VERSION 5.7 ;
  NOWIREEXTENSIONATPIN ON ;
  DIVIDERCHAR "/" ;
  BUSBITCHARS "[]" ;
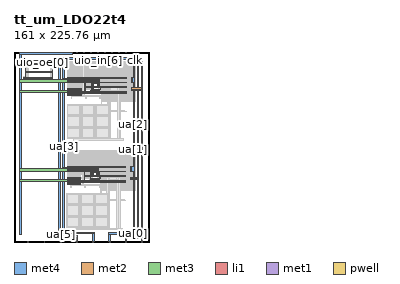
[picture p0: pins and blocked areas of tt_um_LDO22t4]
MACRO tt_um_LDO22t4
  CLASS BLOCK ;
  FOREIGN tt_um_LDO22t4 ;
  ORIGIN 0.000 0.000 ;
  SIZE 161.000 BY 225.760 ;
  PIN clk
    PORT
      LAYER met4 ;
        RECT 143.830 224.760 144.130 225.760 ;
    END
  END clk
  PIN ena
    PORT
      LAYER met4 ;
        RECT 146.590 224.760 146.890 225.760 ;
    END
  END ena
  PIN rst_n
    PORT
      LAYER met4 ;
        RECT 141.070 224.760 141.370 225.760 ;
    END
  END rst_n
  PIN ua[0]
    PORT
      LAYER met2 ;
        RECT 139.680 181.740 153.265 183.020 ;
        RECT 139.700 179.535 153.265 181.740 ;
      LAYER met3 ;
        RECT 151.310 181.805 153.190 182.970 ;
      LAYER met4 ;
        RECT 151.265 0.995 153.265 214.950 ;
        RECT 151.810 0.000 152.710 0.995 ;
    END
  END ua[0]
  PIN ua[1]
    PORT
      LAYER met2 ;
        RECT 138.825 75.945 148.495 77.225 ;
        RECT 138.860 73.740 148.495 75.945 ;
      LAYER met3 ;
        RECT 146.595 76.025 148.470 77.170 ;
      LAYER met4 ;
        RECT 146.495 5.725 148.495 214.950 ;
        RECT 132.110 3.725 148.495 5.725 ;
        RECT 132.110 2.850 134.110 3.725 ;
        RECT 132.110 1.000 134.105 2.850 ;
        RECT 132.490 0.000 133.390 1.000 ;
    END
  END ua[1]
  PIN ua[2]
    PORT
      LAYER li1 ;
        RECT 42.845 213.690 45.005 214.040 ;
      LAYER met1 ;
        RECT 42.870 213.380 44.975 214.340 ;
      LAYER met2 ;
        RECT 44.655 213.380 50.280 214.340 ;
      LAYER met3 ;
        RECT 48.260 213.380 50.280 219.085 ;
        RECT 139.090 189.435 140.555 195.880 ;
        RECT 138.345 83.450 139.665 89.480 ;
      LAYER met4 ;
        RECT 48.260 217.160 143.725 219.085 ;
        RECT 141.725 194.975 143.725 217.160 ;
        RECT 139.245 189.520 143.725 194.975 ;
        RECT 141.725 89.175 143.725 189.520 ;
        RECT 138.410 83.720 143.725 89.175 ;
        RECT 141.725 10.910 143.725 83.720 ;
        RECT 112.690 8.910 143.725 10.910 ;
        RECT 112.690 1.000 114.690 8.910 ;
        RECT 113.170 0.000 114.070 1.000 ;
    END
  END ua[2]
  PIN ua[3]
    ANTENNAGATEAREA 2.000000 ;
    PORT
      LAYER li1 ;
        RECT 67.580 192.650 68.370 192.820 ;
        RECT 68.870 192.650 69.660 192.820 ;
        RECT 67.580 191.600 68.370 191.770 ;
        RECT 68.870 191.600 69.660 191.770 ;
        RECT 66.740 86.855 67.530 87.025 ;
        RECT 68.030 86.855 68.820 87.025 ;
        RECT 66.740 85.805 67.530 85.975 ;
        RECT 68.030 85.805 68.820 85.975 ;
      LAYER met1 ;
        RECT 67.655 192.850 68.295 192.940 ;
        RECT 68.945 192.850 69.585 192.940 ;
        RECT 67.600 192.620 68.350 192.850 ;
        RECT 68.890 192.620 69.640 192.850 ;
        RECT 67.600 191.570 68.350 191.800 ;
        RECT 68.890 191.570 69.640 191.800 ;
        RECT 67.655 191.480 68.295 191.570 ;
        RECT 68.945 191.480 69.585 191.570 ;
        RECT 66.815 87.055 67.455 87.145 ;
        RECT 68.105 87.055 68.745 87.145 ;
        RECT 66.760 86.825 67.510 87.055 ;
        RECT 68.050 86.825 68.800 87.055 ;
        RECT 66.760 85.775 67.510 86.005 ;
        RECT 68.050 85.775 68.800 86.005 ;
        RECT 66.815 85.685 67.455 85.775 ;
        RECT 68.105 85.685 68.745 85.775 ;
      LAYER met2 ;
        RECT 57.830 193.080 68.780 194.150 ;
        RECT 57.830 193.075 64.395 193.080 ;
        RECT 68.460 192.940 68.780 193.080 ;
        RECT 67.655 192.620 69.585 192.940 ;
        RECT 68.415 191.800 68.715 192.620 ;
        RECT 67.655 191.480 69.585 191.800 ;
        RECT 57.830 87.285 67.940 88.355 ;
        RECT 57.830 87.280 64.390 87.285 ;
        RECT 57.830 87.255 63.160 87.280 ;
        RECT 67.620 87.145 67.940 87.285 ;
        RECT 66.815 86.825 68.745 87.145 ;
        RECT 67.575 86.005 67.875 86.825 ;
        RECT 66.815 85.685 68.745 86.005 ;
      LAYER met3 ;
        RECT 57.835 193.100 59.830 193.715 ;
        RECT 57.820 87.280 59.835 87.920 ;
      LAYER met4 ;
        RECT 57.830 12.630 59.830 214.950 ;
        RECT 57.830 11.815 59.835 12.630 ;
        RECT 57.830 9.815 95.175 11.815 ;
        RECT 93.180 0.995 95.175 9.815 ;
        RECT 93.850 0.000 94.750 0.995 ;
    END
  END ua[3]
  PIN ua[4]
    PORT
      LAYER li1 ;
        RECT 42.845 212.860 45.005 213.210 ;
        RECT 42.845 209.000 45.005 209.350 ;
      LAYER met1 ;
        RECT 44.960 213.160 46.310 213.165 ;
        RECT 42.870 212.475 46.310 213.160 ;
        RECT 45.410 209.740 46.310 212.475 ;
        RECT 42.870 209.050 46.310 209.740 ;
        RECT 44.835 209.045 46.310 209.050 ;
      LAYER met2 ;
        RECT 45.460 212.560 45.735 212.570 ;
        RECT 45.425 209.605 55.060 212.560 ;
        RECT 45.460 209.565 45.735 209.605 ;
      LAYER met3 ;
        RECT 53.105 210.420 55.015 212.490 ;
      LAYER met4 ;
        RECT 53.050 7.790 55.060 214.950 ;
        RECT 73.975 7.795 75.980 7.800 ;
        RECT 56.660 7.790 75.980 7.795 ;
        RECT 53.050 5.790 75.980 7.790 ;
        RECT 73.975 1.000 75.980 5.790 ;
        RECT 74.530 0.000 75.430 1.000 ;
    END
  END ua[4]
  PIN ua[5]
    PORT
      LAYER met4 ;
        RECT 55.210 0.000 56.110 0.990 ;
    END
  END ua[5]
  PIN ua[6]
    PORT
      LAYER met4 ;
        RECT 35.890 0.000 36.790 1.000 ;
    END
  END ua[6]
  PIN ua[7]
    PORT
      LAYER met4 ;
        RECT 16.570 0.000 17.470 1.000 ;
    END
  END ua[7]
  PIN ui_in[0]
    PORT
      LAYER met4 ;
        RECT 138.310 224.760 138.610 225.760 ;
    END
  END ui_in[0]
  PIN ui_in[1]
    PORT
      LAYER met4 ;
        RECT 135.550 224.760 135.850 225.760 ;
    END
  END ui_in[1]
  PIN ui_in[2]
    PORT
      LAYER met4 ;
        RECT 132.790 224.760 133.090 225.760 ;
    END
  END ui_in[2]
  PIN ui_in[3]
    PORT
      LAYER met4 ;
        RECT 130.030 224.760 130.330 225.760 ;
    END
  END ui_in[3]
  PIN ui_in[4]
    PORT
      LAYER met4 ;
        RECT 127.270 224.760 127.570 225.760 ;
    END
  END ui_in[4]
  PIN ui_in[5]
    PORT
      LAYER met4 ;
        RECT 124.510 224.760 124.810 225.760 ;
    END
  END ui_in[5]
  PIN ui_in[6]
    PORT
      LAYER met4 ;
        RECT 121.750 224.760 122.050 225.760 ;
    END
  END ui_in[6]
  PIN ui_in[7]
    PORT
      LAYER met4 ;
        RECT 118.990 224.760 119.290 225.760 ;
    END
  END ui_in[7]
  PIN uio_in[0]
    PORT
      LAYER met4 ;
        RECT 116.230 224.760 116.530 225.760 ;
    END
  END uio_in[0]
  PIN uio_in[1]
    PORT
      LAYER met4 ;
        RECT 113.470 224.760 113.770 225.760 ;
    END
  END uio_in[1]
  PIN uio_in[2]
    PORT
      LAYER met4 ;
        RECT 110.710 224.760 111.010 225.760 ;
    END
  END uio_in[2]
  PIN uio_in[3]
    PORT
      LAYER met4 ;
        RECT 107.950 224.760 108.250 225.760 ;
    END
  END uio_in[3]
  PIN uio_in[4]
    PORT
      LAYER met4 ;
        RECT 105.190 224.760 105.490 225.760 ;
    END
  END uio_in[4]
  PIN uio_in[5]
    PORT
      LAYER met4 ;
        RECT 102.430 224.760 102.730 225.760 ;
    END
  END uio_in[5]
  PIN uio_in[6]
    PORT
      LAYER met4 ;
        RECT 99.670 224.760 99.970 225.760 ;
    END
  END uio_in[6]
  PIN uio_in[7]
    PORT
      LAYER met4 ;
        RECT 96.910 224.760 97.210 225.760 ;
    END
  END uio_in[7]
  PIN uio_oe[0]
    ANTENNAGATEAREA 80.379997 ;
    ANTENNADIFFAREA 155.779800 ;
    PORT
      LAYER pwell ;
        RECT 13.815 215.220 45.785 215.650 ;
        RECT 13.815 211.680 14.245 215.220 ;
        RECT 45.355 211.680 45.785 215.220 ;
        RECT 13.815 211.250 45.785 211.680 ;
        RECT 13.815 210.530 45.785 210.960 ;
        RECT 13.815 202.840 14.245 210.530 ;
        RECT 45.355 202.840 45.785 210.530 ;
        RECT 13.815 202.410 45.785 202.840 ;
        RECT 13.815 201.690 45.785 202.120 ;
        RECT 13.815 194.830 14.245 201.690 ;
        RECT 45.355 194.830 45.785 201.690 ;
        RECT 13.815 194.400 45.785 194.830 ;
        RECT 63.975 194.620 101.335 195.050 ;
        RECT 63.975 189.800 64.405 194.620 ;
        RECT 72.855 189.800 73.285 194.620 ;
        RECT 89.465 189.800 89.895 194.620 ;
        RECT 100.905 189.800 101.335 194.620 ;
        RECT 63.975 189.370 101.335 189.800 ;
        RECT 64.135 176.320 79.615 182.415 ;
        RECT 64.135 176.230 65.275 176.320 ;
        RECT 76.825 176.230 79.615 176.320 ;
        RECT 64.095 174.220 71.665 176.230 ;
        RECT 72.220 174.220 79.790 176.230 ;
        RECT 63.135 88.825 100.495 89.255 ;
        RECT 63.135 84.005 63.565 88.825 ;
        RECT 72.015 84.005 72.445 88.825 ;
        RECT 88.625 84.005 89.055 88.825 ;
        RECT 100.065 84.005 100.495 88.825 ;
        RECT 63.135 83.575 100.495 84.005 ;
        RECT 63.295 70.525 78.775 76.620 ;
        RECT 63.295 70.435 64.435 70.525 ;
        RECT 75.985 70.435 78.775 70.525 ;
        RECT 63.255 68.425 70.825 70.435 ;
        RECT 71.380 68.425 78.950 70.435 ;
      LAYER li1 ;
        RECT 14.585 215.520 45.020 215.525 ;
        RECT 13.945 215.350 45.655 215.520 ;
        RECT 13.945 211.550 14.115 215.350 ;
        RECT 45.485 211.550 45.655 215.350 ;
        RECT 13.945 210.660 45.655 211.550 ;
        RECT 13.945 202.710 14.115 210.660 ;
        RECT 45.485 202.710 45.655 210.660 ;
        RECT 13.945 201.820 45.655 202.710 ;
        RECT 13.945 194.700 14.115 201.820 ;
        RECT 45.485 194.700 45.655 201.820 ;
        RECT 13.945 194.530 45.655 194.700 ;
        RECT 64.105 194.750 101.205 194.920 ;
        RECT 64.105 189.670 64.275 194.750 ;
        RECT 64.665 194.410 64.835 194.750 ;
        RECT 65.955 194.410 66.125 194.750 ;
        RECT 67.245 194.410 67.415 194.750 ;
        RECT 68.535 194.410 68.705 194.750 ;
        RECT 69.825 194.410 69.995 194.750 ;
        RECT 71.115 194.410 71.285 194.750 ;
        RECT 72.405 194.410 72.575 194.750 ;
        RECT 64.665 194.240 72.575 194.410 ;
        RECT 64.665 193.360 64.835 194.240 ;
        RECT 65.955 193.360 66.125 194.240 ;
        RECT 67.245 193.360 67.415 194.240 ;
        RECT 68.535 193.360 68.705 194.240 ;
        RECT 69.825 193.360 69.995 194.240 ;
        RECT 71.115 193.360 71.285 194.240 ;
        RECT 72.405 193.360 72.575 194.240 ;
        RECT 64.665 193.190 72.575 193.360 ;
        RECT 64.665 191.060 72.575 191.230 ;
        RECT 64.665 190.180 64.835 191.060 ;
        RECT 65.955 190.180 66.125 191.060 ;
        RECT 67.245 190.180 67.415 191.060 ;
        RECT 68.535 190.180 68.705 191.060 ;
        RECT 69.825 190.180 69.995 191.060 ;
        RECT 71.115 190.180 71.285 191.060 ;
        RECT 72.405 190.180 72.575 191.060 ;
        RECT 64.665 190.010 72.575 190.180 ;
        RECT 64.665 189.670 64.835 190.010 ;
        RECT 65.955 189.670 66.125 190.010 ;
        RECT 67.245 189.670 67.415 190.010 ;
        RECT 68.535 189.670 68.705 190.010 ;
        RECT 69.825 189.670 69.995 190.010 ;
        RECT 71.115 189.670 71.285 190.010 ;
        RECT 72.985 189.670 73.155 194.750 ;
        RECT 73.535 194.410 73.705 194.750 ;
        RECT 74.825 194.410 74.995 194.750 ;
        RECT 76.115 194.410 76.285 194.750 ;
        RECT 77.405 194.410 77.575 194.750 ;
        RECT 78.695 194.410 78.865 194.750 ;
        RECT 79.985 194.410 80.155 194.750 ;
        RECT 82.565 194.410 82.735 194.750 ;
        RECT 83.855 194.410 84.025 194.750 ;
        RECT 85.145 194.410 85.315 194.750 ;
        RECT 86.435 194.410 86.605 194.750 ;
        RECT 87.725 194.410 87.895 194.750 ;
        RECT 89.015 194.410 89.185 194.750 ;
        RECT 73.535 194.240 89.185 194.410 ;
        RECT 73.535 193.360 73.705 194.240 ;
        RECT 74.825 193.360 74.995 194.240 ;
        RECT 76.115 193.360 76.285 194.240 ;
        RECT 77.405 193.360 77.575 194.240 ;
        RECT 78.695 193.360 78.865 194.240 ;
        RECT 79.985 193.360 80.155 194.240 ;
        RECT 81.275 193.360 81.445 194.240 ;
        RECT 82.565 193.360 82.735 194.240 ;
        RECT 83.855 193.360 84.025 194.240 ;
        RECT 85.145 193.360 85.315 194.240 ;
        RECT 86.435 193.360 86.605 194.240 ;
        RECT 87.725 193.360 87.895 194.240 ;
        RECT 89.015 193.360 89.185 194.240 ;
        RECT 73.535 193.190 89.185 193.360 ;
        RECT 73.870 192.650 74.660 192.820 ;
        RECT 88.060 192.650 88.850 192.820 ;
        RECT 73.535 191.940 73.705 192.480 ;
        RECT 74.825 191.940 74.995 192.480 ;
        RECT 77.405 191.940 77.575 192.480 ;
        RECT 79.985 191.940 80.155 192.480 ;
        RECT 82.565 191.940 82.735 192.480 ;
        RECT 85.145 191.940 85.315 192.480 ;
        RECT 87.725 191.940 87.895 192.480 ;
        RECT 89.015 191.940 89.185 192.480 ;
        RECT 73.870 191.600 74.660 191.770 ;
        RECT 88.060 191.600 88.850 191.770 ;
        RECT 73.535 191.060 89.185 191.230 ;
        RECT 73.535 190.180 73.705 191.060 ;
        RECT 74.825 190.180 74.995 191.060 ;
        RECT 76.115 190.180 76.285 191.060 ;
        RECT 77.405 190.180 77.575 191.060 ;
        RECT 78.695 190.180 78.865 191.060 ;
        RECT 79.985 190.180 80.155 191.060 ;
        RECT 81.275 190.180 81.445 191.060 ;
        RECT 82.565 190.180 82.735 191.060 ;
        RECT 83.855 190.180 84.025 191.060 ;
        RECT 85.145 190.180 85.315 191.060 ;
        RECT 86.435 190.180 86.605 191.060 ;
        RECT 87.725 190.180 87.895 191.060 ;
        RECT 89.015 190.180 89.185 191.060 ;
        RECT 73.535 190.010 89.185 190.180 ;
        RECT 73.535 189.670 73.705 190.010 ;
        RECT 74.825 189.670 74.995 190.010 ;
        RECT 76.115 189.670 76.285 190.010 ;
        RECT 77.405 189.670 77.575 190.010 ;
        RECT 78.695 189.670 78.865 190.010 ;
        RECT 79.985 189.670 80.155 190.010 ;
        RECT 81.275 189.670 81.445 190.010 ;
        RECT 82.565 189.670 82.735 190.010 ;
        RECT 83.855 189.670 84.025 190.010 ;
        RECT 85.145 189.670 85.315 190.010 ;
        RECT 86.435 189.670 86.605 190.010 ;
        RECT 87.725 189.670 87.895 190.010 ;
        RECT 89.015 189.670 89.185 190.010 ;
        RECT 89.595 189.670 89.765 194.750 ;
        RECT 90.135 194.410 90.305 194.750 ;
        RECT 91.425 194.410 91.595 194.750 ;
        RECT 92.715 194.410 92.885 194.750 ;
        RECT 94.005 194.410 94.175 194.750 ;
        RECT 95.295 194.410 95.465 194.750 ;
        RECT 96.585 194.410 96.755 194.750 ;
        RECT 97.875 194.410 98.045 194.750 ;
        RECT 99.165 194.410 99.335 194.750 ;
        RECT 100.455 194.410 100.625 194.750 ;
        RECT 90.135 194.240 100.625 194.410 ;
        RECT 90.135 193.360 90.305 194.240 ;
        RECT 91.425 193.360 91.595 194.240 ;
        RECT 92.715 193.360 92.885 194.240 ;
        RECT 94.005 193.360 94.175 194.240 ;
        RECT 95.295 193.360 95.465 194.240 ;
        RECT 96.585 193.360 96.755 194.240 ;
        RECT 97.875 193.360 98.045 194.240 ;
        RECT 99.165 193.360 99.335 194.240 ;
        RECT 100.455 193.360 100.625 194.240 ;
        RECT 90.135 193.190 100.625 193.360 ;
        RECT 90.470 192.650 91.260 192.820 ;
        RECT 99.500 192.650 100.290 192.820 ;
        RECT 90.135 191.940 90.305 192.480 ;
        RECT 91.425 191.940 91.595 192.480 ;
        RECT 94.005 191.940 94.175 192.480 ;
        RECT 96.585 191.940 96.755 192.480 ;
        RECT 99.165 191.940 99.335 192.480 ;
        RECT 100.455 191.940 100.625 192.480 ;
        RECT 90.470 191.600 91.260 191.770 ;
        RECT 99.500 191.600 100.290 191.770 ;
        RECT 90.135 191.060 100.625 191.230 ;
        RECT 90.135 190.180 90.305 191.060 ;
        RECT 91.425 190.180 91.595 191.060 ;
        RECT 92.715 190.180 92.885 191.060 ;
        RECT 94.005 190.180 94.175 191.060 ;
        RECT 95.295 190.180 95.465 191.060 ;
        RECT 96.585 190.180 96.755 191.060 ;
        RECT 97.875 190.180 98.045 191.060 ;
        RECT 99.165 190.180 99.335 191.060 ;
        RECT 100.455 190.180 100.625 191.060 ;
        RECT 90.135 190.010 100.625 190.180 ;
        RECT 90.135 189.670 90.305 190.010 ;
        RECT 91.425 189.670 91.595 190.010 ;
        RECT 92.715 189.670 92.885 190.010 ;
        RECT 94.005 189.670 94.175 190.010 ;
        RECT 95.295 189.670 95.465 190.010 ;
        RECT 96.585 189.670 96.755 190.010 ;
        RECT 97.875 189.670 98.045 190.010 ;
        RECT 99.165 189.670 99.335 190.010 ;
        RECT 100.455 189.670 100.625 190.010 ;
        RECT 101.035 189.670 101.205 194.750 ;
        RECT 64.105 189.500 101.205 189.670 ;
        RECT 92.085 187.840 101.925 188.010 ;
        RECT 92.085 187.360 92.255 187.840 ;
        RECT 101.755 187.360 101.925 187.840 ;
        RECT 92.085 187.010 94.895 187.360 ;
        RECT 99.115 187.010 101.925 187.360 ;
        RECT 92.085 185.700 92.255 187.010 ;
        RECT 101.755 185.700 101.925 187.010 ;
        RECT 92.085 185.350 94.895 185.700 ;
        RECT 99.115 185.350 101.925 185.700 ;
        RECT 92.085 184.870 92.255 185.350 ;
        RECT 101.755 184.870 101.925 185.350 ;
        RECT 92.085 184.150 101.925 184.870 ;
        RECT 91.555 183.980 103.145 184.150 ;
        RECT 91.555 183.500 91.725 183.980 ;
        RECT 91.555 183.150 94.365 183.500 ;
        RECT 64.275 182.115 79.610 182.285 ;
        RECT 64.275 176.515 64.445 182.115 ;
        RECT 65.190 181.600 68.890 181.770 ;
        RECT 64.850 180.720 65.020 181.430 ;
        RECT 66.140 180.720 66.310 181.430 ;
        RECT 67.430 180.550 67.600 181.600 ;
        RECT 68.720 180.550 68.890 181.600 ;
        RECT 65.190 180.380 68.890 180.550 ;
        RECT 69.280 181.520 77.410 181.690 ;
        RECT 77.920 181.520 78.700 181.690 ;
        RECT 69.280 180.640 69.450 181.520 ;
        RECT 70.570 180.640 70.740 181.520 ;
        RECT 71.860 180.640 72.030 181.520 ;
        RECT 73.150 180.640 73.320 181.520 ;
        RECT 74.440 180.640 74.610 181.520 ;
        RECT 75.000 180.640 75.170 181.520 ;
        RECT 76.290 180.640 76.460 181.520 ;
        RECT 77.580 180.810 77.750 181.350 ;
        RECT 78.870 180.810 79.040 181.350 ;
        RECT 69.280 180.470 77.410 180.640 ;
        RECT 77.920 180.470 78.700 180.640 ;
        RECT 65.190 179.840 65.970 180.010 ;
        RECT 77.920 179.760 78.700 179.930 ;
        RECT 64.850 178.960 65.020 179.670 ;
        RECT 66.140 178.960 66.310 179.670 ;
        RECT 70.570 179.050 70.740 179.590 ;
        RECT 73.150 179.050 73.320 179.590 ;
        RECT 77.580 179.050 77.750 179.590 ;
        RECT 78.870 179.050 79.040 179.590 ;
        RECT 65.190 178.620 65.970 178.790 ;
        RECT 77.920 178.710 78.700 178.880 ;
        RECT 65.190 178.080 68.890 178.250 ;
        RECT 64.850 177.200 65.020 177.910 ;
        RECT 66.140 177.200 66.310 177.910 ;
        RECT 67.430 177.030 67.600 178.080 ;
        RECT 68.720 177.030 68.890 178.080 ;
        RECT 65.190 176.860 68.890 177.030 ;
        RECT 69.280 178.000 77.410 178.170 ;
        RECT 77.890 178.000 78.730 178.170 ;
        RECT 69.280 177.120 69.450 178.000 ;
        RECT 70.570 177.120 70.740 178.000 ;
        RECT 71.860 177.120 72.030 178.000 ;
        RECT 73.150 177.120 73.320 178.000 ;
        RECT 74.440 177.120 74.610 178.000 ;
        RECT 75.000 177.120 75.170 178.000 ;
        RECT 76.290 177.120 76.460 178.000 ;
        RECT 77.580 177.290 77.750 177.830 ;
        RECT 78.870 177.290 79.040 177.830 ;
        RECT 69.280 176.950 77.410 177.120 ;
        RECT 77.890 176.950 78.730 177.120 ;
        RECT 79.440 176.515 79.610 182.115 ;
        RECT 91.555 181.840 91.725 183.150 ;
        RECT 91.555 181.490 94.365 181.840 ;
        RECT 91.555 181.010 91.725 181.490 ;
        RECT 102.975 181.010 103.145 183.980 ;
        RECT 91.555 180.840 103.145 181.010 ;
        RECT 91.555 180.290 101.995 180.840 ;
        RECT 91.285 180.120 101.995 180.290 ;
        RECT 91.285 179.640 91.455 180.120 ;
        RECT 101.825 179.640 101.995 180.120 ;
        RECT 91.285 179.290 94.095 179.640 ;
        RECT 99.185 179.290 101.995 179.640 ;
        RECT 91.285 177.980 91.455 179.290 ;
        RECT 101.825 178.810 101.995 179.290 ;
        RECT 99.185 178.460 101.995 178.810 ;
        RECT 101.825 177.980 101.995 178.460 ;
        RECT 91.285 177.630 94.095 177.980 ;
        RECT 99.185 177.630 101.995 177.980 ;
        RECT 91.285 177.150 91.455 177.630 ;
        RECT 101.825 177.150 101.995 177.630 ;
        RECT 91.285 176.980 101.995 177.150 ;
        RECT 64.275 176.045 79.610 176.515 ;
        RECT 64.275 175.880 71.485 176.045 ;
        RECT 64.275 174.570 64.445 175.880 ;
        RECT 71.315 174.570 71.485 175.880 ;
        RECT 64.275 174.400 71.485 174.570 ;
        RECT 72.400 175.880 79.610 176.045 ;
        RECT 72.400 174.570 72.570 175.880 ;
        RECT 79.440 174.570 79.610 175.880 ;
        RECT 72.400 174.400 79.610 174.570 ;
        RECT 63.265 88.955 100.365 89.125 ;
        RECT 63.265 83.875 63.435 88.955 ;
        RECT 63.825 88.615 63.995 88.955 ;
        RECT 65.115 88.615 65.285 88.955 ;
        RECT 66.405 88.615 66.575 88.955 ;
        RECT 67.695 88.615 67.865 88.955 ;
        RECT 68.985 88.615 69.155 88.955 ;
        RECT 70.275 88.615 70.445 88.955 ;
        RECT 71.565 88.615 71.735 88.955 ;
        RECT 63.825 88.445 71.735 88.615 ;
        RECT 63.825 87.565 63.995 88.445 ;
        RECT 65.115 87.565 65.285 88.445 ;
        RECT 66.405 87.565 66.575 88.445 ;
        RECT 67.695 87.565 67.865 88.445 ;
        RECT 68.985 87.565 69.155 88.445 ;
        RECT 70.275 87.565 70.445 88.445 ;
        RECT 71.565 87.565 71.735 88.445 ;
        RECT 63.825 87.395 71.735 87.565 ;
        RECT 63.825 85.265 71.735 85.435 ;
        RECT 63.825 84.385 63.995 85.265 ;
        RECT 65.115 84.385 65.285 85.265 ;
        RECT 66.405 84.385 66.575 85.265 ;
        RECT 67.695 84.385 67.865 85.265 ;
        RECT 68.985 84.385 69.155 85.265 ;
        RECT 70.275 84.385 70.445 85.265 ;
        RECT 71.565 84.385 71.735 85.265 ;
        RECT 63.825 84.215 71.735 84.385 ;
        RECT 63.825 83.875 63.995 84.215 ;
        RECT 65.115 83.875 65.285 84.215 ;
        RECT 66.405 83.875 66.575 84.215 ;
        RECT 67.695 83.875 67.865 84.215 ;
        RECT 68.985 83.875 69.155 84.215 ;
        RECT 70.275 83.875 70.445 84.215 ;
        RECT 72.145 83.875 72.315 88.955 ;
        RECT 72.695 88.615 72.865 88.955 ;
        RECT 73.985 88.615 74.155 88.955 ;
        RECT 75.275 88.615 75.445 88.955 ;
        RECT 76.565 88.615 76.735 88.955 ;
        RECT 77.855 88.615 78.025 88.955 ;
        RECT 79.145 88.615 79.315 88.955 ;
        RECT 81.725 88.615 81.895 88.955 ;
        RECT 83.015 88.615 83.185 88.955 ;
        RECT 84.305 88.615 84.475 88.955 ;
        RECT 85.595 88.615 85.765 88.955 ;
        RECT 86.885 88.615 87.055 88.955 ;
        RECT 88.175 88.615 88.345 88.955 ;
        RECT 72.695 88.445 88.345 88.615 ;
        RECT 72.695 87.565 72.865 88.445 ;
        RECT 73.985 87.565 74.155 88.445 ;
        RECT 75.275 87.565 75.445 88.445 ;
        RECT 76.565 87.565 76.735 88.445 ;
        RECT 77.855 87.565 78.025 88.445 ;
        RECT 79.145 87.565 79.315 88.445 ;
        RECT 80.435 87.565 80.605 88.445 ;
        RECT 81.725 87.565 81.895 88.445 ;
        RECT 83.015 87.565 83.185 88.445 ;
        RECT 84.305 87.565 84.475 88.445 ;
        RECT 85.595 87.565 85.765 88.445 ;
        RECT 86.885 87.565 87.055 88.445 ;
        RECT 88.175 87.565 88.345 88.445 ;
        RECT 72.695 87.395 88.345 87.565 ;
        RECT 73.030 86.855 73.820 87.025 ;
        RECT 87.220 86.855 88.010 87.025 ;
        RECT 72.695 86.145 72.865 86.685 ;
        RECT 73.985 86.145 74.155 86.685 ;
        RECT 76.565 86.145 76.735 86.685 ;
        RECT 79.145 86.145 79.315 86.685 ;
        RECT 81.725 86.145 81.895 86.685 ;
        RECT 84.305 86.145 84.475 86.685 ;
        RECT 86.885 86.145 87.055 86.685 ;
        RECT 88.175 86.145 88.345 86.685 ;
        RECT 73.030 85.805 73.820 85.975 ;
        RECT 87.220 85.805 88.010 85.975 ;
        RECT 72.695 85.265 88.345 85.435 ;
        RECT 72.695 84.385 72.865 85.265 ;
        RECT 73.985 84.385 74.155 85.265 ;
        RECT 75.275 84.385 75.445 85.265 ;
        RECT 76.565 84.385 76.735 85.265 ;
        RECT 77.855 84.385 78.025 85.265 ;
        RECT 79.145 84.385 79.315 85.265 ;
        RECT 80.435 84.385 80.605 85.265 ;
        RECT 81.725 84.385 81.895 85.265 ;
        RECT 83.015 84.385 83.185 85.265 ;
        RECT 84.305 84.385 84.475 85.265 ;
        RECT 85.595 84.385 85.765 85.265 ;
        RECT 86.885 84.385 87.055 85.265 ;
        RECT 88.175 84.385 88.345 85.265 ;
        RECT 72.695 84.215 88.345 84.385 ;
        RECT 72.695 83.875 72.865 84.215 ;
        RECT 73.985 83.875 74.155 84.215 ;
        RECT 75.275 83.875 75.445 84.215 ;
        RECT 76.565 83.875 76.735 84.215 ;
        RECT 77.855 83.875 78.025 84.215 ;
        RECT 79.145 83.875 79.315 84.215 ;
        RECT 80.435 83.875 80.605 84.215 ;
        RECT 81.725 83.875 81.895 84.215 ;
        RECT 83.015 83.875 83.185 84.215 ;
        RECT 84.305 83.875 84.475 84.215 ;
        RECT 85.595 83.875 85.765 84.215 ;
        RECT 86.885 83.875 87.055 84.215 ;
        RECT 88.175 83.875 88.345 84.215 ;
        RECT 88.755 83.875 88.925 88.955 ;
        RECT 89.295 88.615 89.465 88.955 ;
        RECT 90.585 88.615 90.755 88.955 ;
        RECT 91.875 88.615 92.045 88.955 ;
        RECT 93.165 88.615 93.335 88.955 ;
        RECT 94.455 88.615 94.625 88.955 ;
        RECT 95.745 88.615 95.915 88.955 ;
        RECT 97.035 88.615 97.205 88.955 ;
        RECT 98.325 88.615 98.495 88.955 ;
        RECT 99.615 88.615 99.785 88.955 ;
        RECT 89.295 88.445 99.785 88.615 ;
        RECT 89.295 87.565 89.465 88.445 ;
        RECT 90.585 87.565 90.755 88.445 ;
        RECT 91.875 87.565 92.045 88.445 ;
        RECT 93.165 87.565 93.335 88.445 ;
        RECT 94.455 87.565 94.625 88.445 ;
        RECT 95.745 87.565 95.915 88.445 ;
        RECT 97.035 87.565 97.205 88.445 ;
        RECT 98.325 87.565 98.495 88.445 ;
        RECT 99.615 87.565 99.785 88.445 ;
        RECT 89.295 87.395 99.785 87.565 ;
        RECT 89.630 86.855 90.420 87.025 ;
        RECT 98.660 86.855 99.450 87.025 ;
        RECT 89.295 86.145 89.465 86.685 ;
        RECT 90.585 86.145 90.755 86.685 ;
        RECT 93.165 86.145 93.335 86.685 ;
        RECT 95.745 86.145 95.915 86.685 ;
        RECT 98.325 86.145 98.495 86.685 ;
        RECT 99.615 86.145 99.785 86.685 ;
        RECT 89.630 85.805 90.420 85.975 ;
        RECT 98.660 85.805 99.450 85.975 ;
        RECT 89.295 85.265 99.785 85.435 ;
        RECT 89.295 84.385 89.465 85.265 ;
        RECT 90.585 84.385 90.755 85.265 ;
        RECT 91.875 84.385 92.045 85.265 ;
        RECT 93.165 84.385 93.335 85.265 ;
        RECT 94.455 84.385 94.625 85.265 ;
        RECT 95.745 84.385 95.915 85.265 ;
        RECT 97.035 84.385 97.205 85.265 ;
        RECT 98.325 84.385 98.495 85.265 ;
        RECT 99.615 84.385 99.785 85.265 ;
        RECT 89.295 84.215 99.785 84.385 ;
        RECT 89.295 83.875 89.465 84.215 ;
        RECT 90.585 83.875 90.755 84.215 ;
        RECT 91.875 83.875 92.045 84.215 ;
        RECT 93.165 83.875 93.335 84.215 ;
        RECT 94.455 83.875 94.625 84.215 ;
        RECT 95.745 83.875 95.915 84.215 ;
        RECT 97.035 83.875 97.205 84.215 ;
        RECT 98.325 83.875 98.495 84.215 ;
        RECT 99.615 83.875 99.785 84.215 ;
        RECT 100.195 83.875 100.365 88.955 ;
        RECT 63.265 83.705 100.365 83.875 ;
        RECT 91.245 82.045 101.085 82.215 ;
        RECT 91.245 81.565 91.415 82.045 ;
        RECT 100.915 81.565 101.085 82.045 ;
        RECT 91.245 81.215 94.055 81.565 ;
        RECT 98.275 81.215 101.085 81.565 ;
        RECT 91.245 79.905 91.415 81.215 ;
        RECT 100.915 79.905 101.085 81.215 ;
        RECT 91.245 79.555 94.055 79.905 ;
        RECT 98.275 79.555 101.085 79.905 ;
        RECT 91.245 79.075 91.415 79.555 ;
        RECT 100.915 79.075 101.085 79.555 ;
        RECT 91.245 78.355 101.085 79.075 ;
        RECT 90.715 78.185 102.305 78.355 ;
        RECT 90.715 77.705 90.885 78.185 ;
        RECT 90.715 77.355 93.525 77.705 ;
        RECT 63.435 76.320 78.770 76.490 ;
        RECT 63.435 70.720 63.605 76.320 ;
        RECT 64.350 75.805 68.050 75.975 ;
        RECT 64.010 74.925 64.180 75.635 ;
        RECT 65.300 74.925 65.470 75.635 ;
        RECT 66.590 74.755 66.760 75.805 ;
        RECT 67.880 74.755 68.050 75.805 ;
        RECT 64.350 74.585 68.050 74.755 ;
        RECT 68.440 75.725 76.570 75.895 ;
        RECT 77.080 75.725 77.860 75.895 ;
        RECT 68.440 74.845 68.610 75.725 ;
        RECT 69.730 74.845 69.900 75.725 ;
        RECT 71.020 74.845 71.190 75.725 ;
        RECT 72.310 74.845 72.480 75.725 ;
        RECT 73.600 74.845 73.770 75.725 ;
        RECT 74.160 74.845 74.330 75.725 ;
        RECT 75.450 74.845 75.620 75.725 ;
        RECT 76.740 75.015 76.910 75.555 ;
        RECT 78.030 75.015 78.200 75.555 ;
        RECT 68.440 74.675 76.570 74.845 ;
        RECT 77.080 74.675 77.860 74.845 ;
        RECT 64.350 74.045 65.130 74.215 ;
        RECT 77.080 73.965 77.860 74.135 ;
        RECT 64.010 73.165 64.180 73.875 ;
        RECT 65.300 73.165 65.470 73.875 ;
        RECT 69.730 73.255 69.900 73.795 ;
        RECT 72.310 73.255 72.480 73.795 ;
        RECT 76.740 73.255 76.910 73.795 ;
        RECT 78.030 73.255 78.200 73.795 ;
        RECT 64.350 72.825 65.130 72.995 ;
        RECT 77.080 72.915 77.860 73.085 ;
        RECT 64.350 72.285 68.050 72.455 ;
        RECT 64.010 71.405 64.180 72.115 ;
        RECT 65.300 71.405 65.470 72.115 ;
        RECT 66.590 71.235 66.760 72.285 ;
        RECT 67.880 71.235 68.050 72.285 ;
        RECT 64.350 71.065 68.050 71.235 ;
        RECT 68.440 72.205 76.570 72.375 ;
        RECT 77.050 72.205 77.890 72.375 ;
        RECT 68.440 71.325 68.610 72.205 ;
        RECT 69.730 71.325 69.900 72.205 ;
        RECT 71.020 71.325 71.190 72.205 ;
        RECT 72.310 71.325 72.480 72.205 ;
        RECT 73.600 71.325 73.770 72.205 ;
        RECT 74.160 71.325 74.330 72.205 ;
        RECT 75.450 71.325 75.620 72.205 ;
        RECT 76.740 71.495 76.910 72.035 ;
        RECT 78.030 71.495 78.200 72.035 ;
        RECT 68.440 71.155 76.570 71.325 ;
        RECT 77.050 71.155 77.890 71.325 ;
        RECT 78.600 70.720 78.770 76.320 ;
        RECT 90.715 76.045 90.885 77.355 ;
        RECT 90.715 75.695 93.525 76.045 ;
        RECT 90.715 75.215 90.885 75.695 ;
        RECT 102.135 75.215 102.305 78.185 ;
        RECT 90.715 75.045 102.305 75.215 ;
        RECT 90.715 74.495 101.155 75.045 ;
        RECT 90.445 74.325 101.155 74.495 ;
        RECT 90.445 73.845 90.615 74.325 ;
        RECT 100.985 73.845 101.155 74.325 ;
        RECT 90.445 73.495 93.255 73.845 ;
        RECT 98.345 73.495 101.155 73.845 ;
        RECT 90.445 72.185 90.615 73.495 ;
        RECT 100.985 73.015 101.155 73.495 ;
        RECT 98.345 72.665 101.155 73.015 ;
        RECT 100.985 72.185 101.155 72.665 ;
        RECT 90.445 71.835 93.255 72.185 ;
        RECT 98.345 71.835 101.155 72.185 ;
        RECT 90.445 71.355 90.615 71.835 ;
        RECT 100.985 71.355 101.155 71.835 ;
        RECT 90.445 71.185 101.155 71.355 ;
        RECT 63.435 70.250 78.770 70.720 ;
        RECT 63.435 70.085 70.645 70.250 ;
        RECT 63.435 68.775 63.605 70.085 ;
        RECT 70.475 68.775 70.645 70.085 ;
        RECT 63.435 68.605 70.645 68.775 ;
        RECT 71.560 70.085 78.770 70.250 ;
        RECT 71.560 68.775 71.730 70.085 ;
        RECT 78.600 68.775 78.770 70.085 ;
        RECT 71.560 68.605 78.770 68.775 ;
      LAYER met1 ;
        RECT 14.485 215.235 45.070 215.655 ;
        RECT 67.170 194.995 67.490 195.000 ;
        RECT 14.315 194.390 45.120 194.830 ;
        RECT 63.990 189.755 64.350 194.995 ;
        RECT 66.300 194.690 68.365 194.995 ;
        RECT 68.875 194.690 70.950 194.995 ;
        RECT 71.620 194.690 80.860 194.995 ;
        RECT 81.770 194.700 91.670 194.995 ;
        RECT 67.170 194.680 67.490 194.690 ;
        RECT 69.750 194.675 70.070 194.690 ;
        RECT 72.900 194.600 73.220 194.690 ;
        RECT 64.635 191.030 66.155 191.260 ;
        RECT 64.635 190.210 64.865 191.030 ;
        RECT 65.925 190.210 66.155 191.030 ;
        RECT 64.635 189.980 66.155 190.210 ;
        RECT 64.635 189.755 64.865 189.980 ;
        RECT 65.925 189.755 66.155 189.980 ;
        RECT 68.505 189.755 68.735 191.785 ;
        RECT 71.085 191.030 72.605 191.260 ;
        RECT 71.085 190.210 71.315 191.030 ;
        RECT 72.375 190.210 72.605 191.030 ;
        RECT 71.085 189.980 72.605 190.210 ;
        RECT 72.955 190.070 73.185 194.600 ;
        RECT 73.460 194.440 73.780 194.690 ;
        RECT 74.750 194.440 75.070 194.690 ;
        RECT 77.330 194.440 77.650 194.690 ;
        RECT 79.910 194.440 80.230 194.690 ;
        RECT 82.495 194.440 82.815 194.700 ;
        RECT 85.070 194.440 85.390 194.700 ;
        RECT 87.650 194.440 87.970 194.700 ;
        RECT 88.940 194.440 89.260 194.700 ;
        RECT 73.460 194.355 81.090 194.440 ;
        RECT 73.505 194.210 81.090 194.355 ;
        RECT 81.630 194.355 89.260 194.440 ;
        RECT 81.630 194.210 89.215 194.355 ;
        RECT 73.505 193.390 73.735 194.210 ;
        RECT 74.795 193.390 75.025 194.210 ;
        RECT 76.085 193.390 76.315 194.210 ;
        RECT 77.375 193.390 77.605 194.210 ;
        RECT 78.665 193.390 78.895 194.210 ;
        RECT 79.955 193.390 80.185 194.210 ;
        RECT 82.535 193.390 82.765 194.210 ;
        RECT 83.825 193.390 84.055 194.210 ;
        RECT 85.115 193.390 85.345 194.210 ;
        RECT 86.405 193.390 86.635 194.210 ;
        RECT 87.695 193.390 87.925 194.210 ;
        RECT 88.985 193.390 89.215 194.210 ;
        RECT 73.505 193.160 81.110 193.390 ;
        RECT 81.630 193.160 89.215 193.390 ;
        RECT 73.505 192.850 73.735 193.160 ;
        RECT 74.795 192.850 75.025 193.160 ;
        RECT 73.505 192.620 75.025 192.850 ;
        RECT 73.505 191.800 73.735 192.620 ;
        RECT 74.795 191.800 75.025 192.620 ;
        RECT 73.505 191.570 75.025 191.800 ;
        RECT 73.505 191.260 73.735 191.570 ;
        RECT 74.795 191.260 75.025 191.570 ;
        RECT 73.505 191.030 75.025 191.260 ;
        RECT 73.505 190.210 73.735 191.030 ;
        RECT 74.795 190.210 75.025 191.030 ;
        RECT 73.505 190.070 75.025 190.210 ;
        RECT 77.375 190.070 77.605 193.160 ;
        RECT 79.955 190.070 80.185 193.160 ;
        RECT 82.535 190.070 82.765 193.160 ;
        RECT 85.115 190.070 85.345 193.160 ;
        RECT 87.695 192.850 87.925 193.160 ;
        RECT 88.985 192.850 89.215 193.160 ;
        RECT 87.695 192.620 89.215 192.850 ;
        RECT 87.695 191.800 87.925 192.620 ;
        RECT 88.985 191.800 89.215 192.620 ;
        RECT 87.695 191.570 89.215 191.800 ;
        RECT 87.695 191.260 87.925 191.570 ;
        RECT 88.985 191.260 89.215 191.570 ;
        RECT 87.695 191.030 89.215 191.260 ;
        RECT 87.695 190.210 87.925 191.030 ;
        RECT 88.985 190.210 89.215 191.030 ;
        RECT 87.695 190.070 89.215 190.210 ;
        RECT 71.085 189.755 71.315 189.980 ;
        RECT 72.375 189.755 72.605 189.980 ;
        RECT 72.900 189.755 73.220 190.070 ;
        RECT 73.450 189.980 75.060 190.070 ;
        RECT 73.450 189.755 73.770 189.980 ;
        RECT 74.740 189.755 75.060 189.980 ;
        RECT 77.320 189.755 77.640 190.070 ;
        RECT 79.900 189.755 80.220 190.070 ;
        RECT 82.485 189.755 82.805 190.070 ;
        RECT 85.065 189.755 85.385 190.070 ;
        RECT 87.645 189.980 89.255 190.070 ;
        RECT 87.645 189.755 87.965 189.980 ;
        RECT 88.935 189.755 89.255 189.980 ;
        RECT 89.565 189.755 89.795 194.700 ;
        RECT 90.060 194.440 90.380 194.700 ;
        RECT 91.350 194.440 91.670 194.700 ;
        RECT 93.065 194.695 95.115 194.995 ;
        RECT 95.655 194.695 97.705 194.995 ;
        RECT 98.245 194.700 101.300 195.000 ;
        RECT 90.060 194.355 91.670 194.440 ;
        RECT 93.930 194.355 94.250 194.695 ;
        RECT 96.515 194.355 96.835 194.695 ;
        RECT 99.090 194.495 99.410 194.700 ;
        RECT 100.375 194.495 100.695 194.700 ;
        RECT 99.090 194.355 100.695 194.495 ;
        RECT 90.105 194.210 91.625 194.355 ;
        RECT 90.105 193.390 90.335 194.210 ;
        RECT 91.395 193.390 91.625 194.210 ;
        RECT 90.105 193.160 91.625 193.390 ;
        RECT 90.105 192.850 90.335 193.160 ;
        RECT 91.395 192.850 91.625 193.160 ;
        RECT 90.105 192.620 91.625 192.850 ;
        RECT 90.105 191.800 90.335 192.620 ;
        RECT 91.395 191.800 91.625 192.620 ;
        RECT 90.105 191.570 91.625 191.800 ;
        RECT 90.105 191.260 90.335 191.570 ;
        RECT 91.395 191.260 91.625 191.570 ;
        RECT 90.105 191.030 91.625 191.260 ;
        RECT 90.105 190.210 90.335 191.030 ;
        RECT 91.395 190.210 91.625 191.030 ;
        RECT 90.105 190.070 91.625 190.210 ;
        RECT 93.975 190.070 94.205 194.355 ;
        RECT 96.555 190.070 96.785 194.355 ;
        RECT 99.135 194.210 100.655 194.355 ;
        RECT 99.135 193.390 99.365 194.210 ;
        RECT 100.425 193.390 100.655 194.210 ;
        RECT 99.135 193.160 100.655 193.390 ;
        RECT 99.135 192.850 99.365 193.160 ;
        RECT 100.425 192.850 100.655 193.160 ;
        RECT 99.135 192.620 100.655 192.850 ;
        RECT 99.135 191.800 99.365 192.620 ;
        RECT 100.425 191.800 100.655 192.620 ;
        RECT 99.135 191.570 100.655 191.800 ;
        RECT 99.135 191.260 99.365 191.570 ;
        RECT 100.425 191.260 100.655 191.570 ;
        RECT 99.135 191.030 100.655 191.260 ;
        RECT 99.135 190.210 99.365 191.030 ;
        RECT 100.425 190.210 100.655 191.030 ;
        RECT 99.135 190.070 100.655 190.210 ;
        RECT 90.060 189.980 91.665 190.070 ;
        RECT 90.060 189.755 90.380 189.980 ;
        RECT 91.345 189.755 91.665 189.980 ;
        RECT 93.925 189.755 94.245 190.070 ;
        RECT 96.505 189.755 96.825 190.070 ;
        RECT 99.090 189.980 100.700 190.070 ;
        RECT 99.090 189.755 99.410 189.980 ;
        RECT 100.380 189.755 100.700 189.980 ;
        RECT 63.990 189.430 80.895 189.755 ;
        RECT 81.700 189.435 100.700 189.755 ;
        RECT 100.940 189.435 101.300 194.700 ;
        RECT 82.485 189.430 82.805 189.435 ;
        RECT 79.955 189.420 80.185 189.430 ;
        RECT 64.190 182.340 64.510 182.395 ;
        RECT 64.190 182.050 65.235 182.340 ;
        RECT 65.880 182.335 66.500 182.345 ;
        RECT 65.870 182.065 66.500 182.335 ;
        RECT 70.480 182.085 70.830 182.345 ;
        RECT 65.880 182.055 66.500 182.065 ;
        RECT 64.190 176.570 64.510 182.050 ;
        RECT 64.820 181.800 65.050 182.050 ;
        RECT 66.110 181.800 66.350 182.055 ;
        RECT 64.820 181.570 66.350 181.800 ;
        RECT 64.820 180.580 65.050 181.570 ;
        RECT 66.110 180.580 66.350 181.570 ;
        RECT 64.820 180.350 66.350 180.580 ;
        RECT 64.820 180.040 65.050 180.350 ;
        RECT 66.110 180.040 66.350 180.350 ;
        RECT 64.820 179.810 66.350 180.040 ;
        RECT 64.820 178.820 65.050 179.810 ;
        RECT 66.110 178.830 66.350 179.810 ;
        RECT 66.110 178.820 66.340 178.830 ;
        RECT 64.820 178.590 66.340 178.820 ;
        RECT 64.820 178.280 65.050 178.590 ;
        RECT 66.110 178.280 66.340 178.590 ;
        RECT 64.820 178.050 66.340 178.280 ;
        RECT 64.820 177.255 65.050 178.050 ;
        RECT 64.760 177.060 65.080 177.255 ;
        RECT 66.110 177.220 66.340 178.050 ;
        RECT 70.540 177.270 70.770 182.085 ;
        RECT 72.925 182.060 73.545 182.350 ;
        RECT 73.120 177.270 73.350 182.060 ;
        RECT 77.355 182.055 77.975 182.345 ;
        RECT 78.635 182.070 79.680 182.360 ;
        RECT 77.520 181.720 77.780 182.055 ;
        RECT 78.840 181.720 79.070 182.070 ;
        RECT 76.645 181.490 79.070 181.720 ;
        RECT 77.520 180.670 77.780 181.490 ;
        RECT 78.840 180.670 79.070 181.490 ;
        RECT 76.645 180.440 79.070 180.670 ;
        RECT 77.520 179.960 77.780 180.440 ;
        RECT 78.840 179.960 79.070 180.440 ;
        RECT 77.520 179.730 79.070 179.960 ;
        RECT 77.520 178.910 77.780 179.730 ;
        RECT 78.840 178.910 79.070 179.730 ;
        RECT 77.520 178.680 79.070 178.910 ;
        RECT 77.520 178.200 77.780 178.680 ;
        RECT 78.840 178.200 79.070 178.680 ;
        RECT 76.645 177.970 79.070 178.200 ;
        RECT 77.520 177.270 77.780 177.970 ;
        RECT 78.840 177.285 79.070 177.970 ;
        RECT 66.065 177.060 66.385 177.220 ;
        RECT 64.760 176.830 66.385 177.060 ;
        RECT 70.505 176.950 70.825 177.270 ;
        RECT 64.760 176.570 65.080 176.830 ;
        RECT 66.065 176.575 66.385 176.830 ;
        RECT 64.190 176.280 65.265 176.570 ;
        RECT 65.920 176.310 66.510 176.575 ;
        RECT 70.500 176.565 70.820 176.950 ;
        RECT 73.075 176.565 73.395 177.270 ;
        RECT 77.490 177.150 77.810 177.270 ;
        RECT 78.795 177.150 79.115 177.285 ;
        RECT 76.645 176.965 79.115 177.150 ;
        RECT 76.645 176.920 79.120 176.965 ;
        RECT 77.490 176.575 77.810 176.920 ;
        RECT 78.800 176.585 79.120 176.920 ;
        RECT 79.360 176.585 79.680 182.070 ;
        RECT 70.350 176.315 70.940 176.565 ;
        RECT 72.940 176.310 73.530 176.565 ;
        RECT 77.350 176.285 77.940 176.575 ;
        RECT 78.640 176.295 79.680 176.585 ;
        RECT 84.295 176.550 84.615 189.435 ;
        RECT 85.065 189.430 85.385 189.435 ;
        RECT 87.645 189.430 87.965 189.435 ;
        RECT 88.935 189.430 89.255 189.435 ;
        RECT 90.060 189.430 90.380 189.435 ;
        RECT 91.345 189.430 91.665 189.435 ;
        RECT 93.925 189.430 94.245 189.435 ;
        RECT 96.505 189.430 96.825 189.435 ;
        RECT 99.090 189.430 99.410 189.435 ;
        RECT 100.380 189.430 100.700 189.435 ;
        RECT 92.165 184.150 101.795 184.810 ;
        RECT 99.210 178.510 101.315 178.760 ;
        RECT 91.965 177.680 94.070 177.930 ;
        RECT 99.210 177.680 101.315 177.930 ;
        RECT 91.525 176.905 101.755 177.220 ;
        RECT 64.190 174.845 64.510 176.280 ;
        RECT 79.360 174.810 79.680 176.295 ;
        RECT 66.330 89.200 66.650 89.205 ;
        RECT 63.150 83.960 63.510 89.200 ;
        RECT 65.460 88.895 67.525 89.200 ;
        RECT 68.035 88.895 70.110 89.200 ;
        RECT 70.780 88.895 80.020 89.200 ;
        RECT 80.930 88.905 90.830 89.200 ;
        RECT 66.330 88.885 66.650 88.895 ;
        RECT 68.910 88.880 69.230 88.895 ;
        RECT 72.060 88.805 72.380 88.895 ;
        RECT 63.795 85.235 65.315 85.465 ;
        RECT 63.795 84.415 64.025 85.235 ;
        RECT 65.085 84.415 65.315 85.235 ;
        RECT 63.795 84.185 65.315 84.415 ;
        RECT 63.795 83.960 64.025 84.185 ;
        RECT 65.085 83.960 65.315 84.185 ;
        RECT 67.665 83.960 67.895 85.990 ;
        RECT 70.245 85.235 71.765 85.465 ;
        RECT 70.245 84.415 70.475 85.235 ;
        RECT 71.535 84.415 71.765 85.235 ;
        RECT 70.245 84.185 71.765 84.415 ;
        RECT 72.115 84.275 72.345 88.805 ;
        RECT 72.620 88.645 72.940 88.895 ;
        RECT 73.910 88.645 74.230 88.895 ;
        RECT 76.490 88.645 76.810 88.895 ;
        RECT 79.070 88.645 79.390 88.895 ;
        RECT 81.655 88.645 81.975 88.905 ;
        RECT 84.230 88.645 84.550 88.905 ;
        RECT 86.810 88.645 87.130 88.905 ;
        RECT 88.100 88.645 88.420 88.905 ;
        RECT 72.620 88.560 80.250 88.645 ;
        RECT 72.665 88.415 80.250 88.560 ;
        RECT 80.790 88.560 88.420 88.645 ;
        RECT 80.790 88.415 88.375 88.560 ;
        RECT 72.665 87.595 72.895 88.415 ;
        RECT 73.955 87.595 74.185 88.415 ;
        RECT 75.245 87.595 75.475 88.415 ;
        RECT 76.535 87.595 76.765 88.415 ;
        RECT 77.825 87.595 78.055 88.415 ;
        RECT 79.115 87.595 79.345 88.415 ;
        RECT 81.695 87.595 81.925 88.415 ;
        RECT 82.985 87.595 83.215 88.415 ;
        RECT 84.275 87.595 84.505 88.415 ;
        RECT 85.565 87.595 85.795 88.415 ;
        RECT 86.855 87.595 87.085 88.415 ;
        RECT 88.145 87.595 88.375 88.415 ;
        RECT 72.665 87.365 80.270 87.595 ;
        RECT 80.790 87.365 88.375 87.595 ;
        RECT 72.665 87.055 72.895 87.365 ;
        RECT 73.955 87.055 74.185 87.365 ;
        RECT 72.665 86.825 74.185 87.055 ;
        RECT 72.665 86.005 72.895 86.825 ;
        RECT 73.955 86.005 74.185 86.825 ;
        RECT 72.665 85.775 74.185 86.005 ;
        RECT 72.665 85.465 72.895 85.775 ;
        RECT 73.955 85.465 74.185 85.775 ;
        RECT 72.665 85.235 74.185 85.465 ;
        RECT 72.665 84.415 72.895 85.235 ;
        RECT 73.955 84.415 74.185 85.235 ;
        RECT 72.665 84.275 74.185 84.415 ;
        RECT 76.535 84.275 76.765 87.365 ;
        RECT 79.115 84.275 79.345 87.365 ;
        RECT 81.695 84.275 81.925 87.365 ;
        RECT 84.275 84.275 84.505 87.365 ;
        RECT 86.855 87.055 87.085 87.365 ;
        RECT 88.145 87.055 88.375 87.365 ;
        RECT 86.855 86.825 88.375 87.055 ;
        RECT 86.855 86.005 87.085 86.825 ;
        RECT 88.145 86.005 88.375 86.825 ;
        RECT 86.855 85.775 88.375 86.005 ;
        RECT 86.855 85.465 87.085 85.775 ;
        RECT 88.145 85.465 88.375 85.775 ;
        RECT 86.855 85.235 88.375 85.465 ;
        RECT 86.855 84.415 87.085 85.235 ;
        RECT 88.145 84.415 88.375 85.235 ;
        RECT 86.855 84.275 88.375 84.415 ;
        RECT 70.245 83.960 70.475 84.185 ;
        RECT 71.535 83.960 71.765 84.185 ;
        RECT 72.060 83.960 72.380 84.275 ;
        RECT 72.610 84.185 74.220 84.275 ;
        RECT 72.610 83.960 72.930 84.185 ;
        RECT 73.900 83.960 74.220 84.185 ;
        RECT 76.480 83.960 76.800 84.275 ;
        RECT 79.060 83.960 79.380 84.275 ;
        RECT 81.645 83.960 81.965 84.275 ;
        RECT 84.225 83.960 84.545 84.275 ;
        RECT 86.805 84.185 88.415 84.275 ;
        RECT 86.805 83.960 87.125 84.185 ;
        RECT 88.095 83.960 88.415 84.185 ;
        RECT 88.725 83.960 88.955 88.905 ;
        RECT 89.220 88.645 89.540 88.905 ;
        RECT 90.510 88.645 90.830 88.905 ;
        RECT 92.225 88.900 94.275 89.200 ;
        RECT 94.815 88.900 96.865 89.200 ;
        RECT 97.405 88.905 100.460 89.205 ;
        RECT 89.220 88.560 90.830 88.645 ;
        RECT 93.090 88.560 93.410 88.900 ;
        RECT 95.675 88.560 95.995 88.900 ;
        RECT 98.250 88.700 98.570 88.905 ;
        RECT 99.535 88.700 99.855 88.905 ;
        RECT 98.250 88.560 99.855 88.700 ;
        RECT 89.265 88.415 90.785 88.560 ;
        RECT 89.265 87.595 89.495 88.415 ;
        RECT 90.555 87.595 90.785 88.415 ;
        RECT 89.265 87.365 90.785 87.595 ;
        RECT 89.265 87.055 89.495 87.365 ;
        RECT 90.555 87.055 90.785 87.365 ;
        RECT 89.265 86.825 90.785 87.055 ;
        RECT 89.265 86.005 89.495 86.825 ;
        RECT 90.555 86.005 90.785 86.825 ;
        RECT 89.265 85.775 90.785 86.005 ;
        RECT 89.265 85.465 89.495 85.775 ;
        RECT 90.555 85.465 90.785 85.775 ;
        RECT 89.265 85.235 90.785 85.465 ;
        RECT 89.265 84.415 89.495 85.235 ;
        RECT 90.555 84.415 90.785 85.235 ;
        RECT 89.265 84.275 90.785 84.415 ;
        RECT 93.135 84.275 93.365 88.560 ;
        RECT 95.715 84.275 95.945 88.560 ;
        RECT 98.295 88.415 99.815 88.560 ;
        RECT 98.295 87.595 98.525 88.415 ;
        RECT 99.585 87.595 99.815 88.415 ;
        RECT 98.295 87.365 99.815 87.595 ;
        RECT 98.295 87.055 98.525 87.365 ;
        RECT 99.585 87.055 99.815 87.365 ;
        RECT 98.295 86.825 99.815 87.055 ;
        RECT 98.295 86.005 98.525 86.825 ;
        RECT 99.585 86.005 99.815 86.825 ;
        RECT 98.295 85.775 99.815 86.005 ;
        RECT 98.295 85.465 98.525 85.775 ;
        RECT 99.585 85.465 99.815 85.775 ;
        RECT 98.295 85.235 99.815 85.465 ;
        RECT 98.295 84.415 98.525 85.235 ;
        RECT 99.585 84.415 99.815 85.235 ;
        RECT 98.295 84.275 99.815 84.415 ;
        RECT 89.220 84.185 90.825 84.275 ;
        RECT 89.220 83.960 89.540 84.185 ;
        RECT 90.505 83.960 90.825 84.185 ;
        RECT 93.085 83.960 93.405 84.275 ;
        RECT 95.665 83.960 95.985 84.275 ;
        RECT 98.250 84.185 99.860 84.275 ;
        RECT 98.250 83.960 98.570 84.185 ;
        RECT 99.540 83.960 99.860 84.185 ;
        RECT 63.150 83.635 80.055 83.960 ;
        RECT 80.860 83.640 99.860 83.960 ;
        RECT 100.100 83.640 100.460 88.905 ;
        RECT 81.645 83.635 81.965 83.640 ;
        RECT 79.115 83.625 79.345 83.635 ;
        RECT 63.350 76.545 63.670 76.600 ;
        RECT 63.350 76.255 64.395 76.545 ;
        RECT 65.040 76.540 65.660 76.550 ;
        RECT 65.030 76.270 65.660 76.540 ;
        RECT 69.640 76.290 69.990 76.550 ;
        RECT 65.040 76.260 65.660 76.270 ;
        RECT 63.350 70.775 63.670 76.255 ;
        RECT 63.980 76.005 64.210 76.255 ;
        RECT 65.270 76.005 65.510 76.260 ;
        RECT 63.980 75.775 65.510 76.005 ;
        RECT 63.980 74.785 64.210 75.775 ;
        RECT 65.270 74.785 65.510 75.775 ;
        RECT 63.980 74.555 65.510 74.785 ;
        RECT 63.980 74.245 64.210 74.555 ;
        RECT 65.270 74.245 65.510 74.555 ;
        RECT 63.980 74.015 65.510 74.245 ;
        RECT 63.980 73.025 64.210 74.015 ;
        RECT 65.270 73.035 65.510 74.015 ;
        RECT 65.270 73.025 65.500 73.035 ;
        RECT 63.980 72.795 65.500 73.025 ;
        RECT 63.980 72.485 64.210 72.795 ;
        RECT 65.270 72.485 65.500 72.795 ;
        RECT 63.980 72.255 65.500 72.485 ;
        RECT 63.980 71.460 64.210 72.255 ;
        RECT 63.920 71.265 64.240 71.460 ;
        RECT 65.270 71.425 65.500 72.255 ;
        RECT 69.700 71.475 69.930 76.290 ;
        RECT 72.085 76.265 72.705 76.555 ;
        RECT 72.280 71.475 72.510 76.265 ;
        RECT 76.515 76.260 77.135 76.550 ;
        RECT 77.795 76.275 78.840 76.565 ;
        RECT 76.680 75.925 76.940 76.260 ;
        RECT 78.000 75.925 78.230 76.275 ;
        RECT 75.805 75.695 78.230 75.925 ;
        RECT 76.680 74.875 76.940 75.695 ;
        RECT 78.000 74.875 78.230 75.695 ;
        RECT 75.805 74.645 78.230 74.875 ;
        RECT 76.680 74.165 76.940 74.645 ;
        RECT 78.000 74.165 78.230 74.645 ;
        RECT 76.680 73.935 78.230 74.165 ;
        RECT 76.680 73.115 76.940 73.935 ;
        RECT 78.000 73.115 78.230 73.935 ;
        RECT 76.680 72.885 78.230 73.115 ;
        RECT 76.680 72.405 76.940 72.885 ;
        RECT 78.000 72.405 78.230 72.885 ;
        RECT 75.805 72.175 78.230 72.405 ;
        RECT 76.680 71.475 76.940 72.175 ;
        RECT 78.000 71.490 78.230 72.175 ;
        RECT 65.225 71.265 65.545 71.425 ;
        RECT 63.920 71.035 65.545 71.265 ;
        RECT 69.665 71.155 69.985 71.475 ;
        RECT 63.920 70.775 64.240 71.035 ;
        RECT 65.225 70.780 65.545 71.035 ;
        RECT 63.350 70.485 64.425 70.775 ;
        RECT 65.080 70.515 65.670 70.780 ;
        RECT 69.660 70.770 69.980 71.155 ;
        RECT 72.235 70.770 72.555 71.475 ;
        RECT 76.650 71.355 76.970 71.475 ;
        RECT 77.955 71.355 78.275 71.490 ;
        RECT 75.805 71.170 78.275 71.355 ;
        RECT 75.805 71.125 78.280 71.170 ;
        RECT 76.650 70.780 76.970 71.125 ;
        RECT 77.960 70.790 78.280 71.125 ;
        RECT 78.520 70.790 78.840 76.275 ;
        RECT 69.510 70.520 70.100 70.770 ;
        RECT 72.100 70.515 72.690 70.770 ;
        RECT 76.510 70.490 77.100 70.780 ;
        RECT 77.800 70.500 78.840 70.790 ;
        RECT 83.455 70.755 83.775 83.640 ;
        RECT 84.225 83.635 84.545 83.640 ;
        RECT 86.805 83.635 87.125 83.640 ;
        RECT 88.095 83.635 88.415 83.640 ;
        RECT 89.220 83.635 89.540 83.640 ;
        RECT 90.505 83.635 90.825 83.640 ;
        RECT 93.085 83.635 93.405 83.640 ;
        RECT 95.665 83.635 95.985 83.640 ;
        RECT 98.250 83.635 98.570 83.640 ;
        RECT 99.540 83.635 99.860 83.640 ;
        RECT 91.325 78.355 100.955 79.015 ;
        RECT 98.370 72.715 100.475 72.965 ;
        RECT 91.125 71.885 93.230 72.135 ;
        RECT 98.370 71.885 100.475 72.135 ;
        RECT 90.685 71.110 100.915 71.425 ;
        RECT 63.350 69.050 63.670 70.485 ;
        RECT 78.520 69.015 78.840 70.500 ;
      LAYER met2 ;
        RECT 6.845 215.705 8.700 215.725 ;
        RECT 6.770 215.185 45.020 215.705 ;
        RECT 6.845 215.175 8.700 215.185 ;
        RECT 67.170 194.995 67.490 195.000 ;
        RECT 10.700 194.340 45.070 194.880 ;
        RECT 63.915 194.355 133.800 194.995 ;
        RECT 63.915 189.430 133.800 190.070 ;
        RECT 84.295 183.715 133.800 185.005 ;
        RECT 77.560 178.150 133.800 178.820 ;
        RECT 63.915 176.550 133.800 177.350 ;
        RECT 66.330 89.200 66.650 89.205 ;
        RECT 63.075 88.560 132.960 89.200 ;
        RECT 63.075 83.635 132.960 84.275 ;
        RECT 83.455 77.920 132.960 79.210 ;
        RECT 76.720 72.355 132.960 73.025 ;
        RECT 63.075 70.755 132.960 71.555 ;
      LAYER met3 ;
        RECT 6.795 215.190 8.750 215.735 ;
        RECT 63.915 192.795 64.380 195.060 ;
        RECT 6.770 189.900 64.380 192.795 ;
        RECT 63.915 189.430 64.380 189.900 ;
        RECT 64.680 189.430 65.145 195.060 ;
        RECT 65.445 189.430 65.910 195.060 ;
        RECT 66.210 193.855 66.675 195.060 ;
        RECT 67.185 189.430 67.650 195.060 ;
        RECT 67.950 189.430 68.415 195.060 ;
        RECT 68.715 189.430 69.180 195.060 ;
        RECT 69.480 189.430 69.945 195.060 ;
        RECT 70.245 193.860 70.710 195.060 ;
        RECT 71.055 189.430 71.520 195.060 ;
        RECT 71.820 189.430 72.285 195.060 ;
        RECT 72.585 189.430 73.050 195.060 ;
        RECT 73.350 189.430 73.815 195.060 ;
        RECT 74.115 189.430 74.580 195.060 ;
        RECT 75.235 193.860 75.700 195.060 ;
        RECT 76.410 189.430 76.875 195.060 ;
        RECT 77.175 189.430 77.640 195.060 ;
        RECT 77.940 189.430 78.405 195.060 ;
        RECT 78.705 189.430 79.170 195.060 ;
        RECT 79.470 189.430 79.935 195.060 ;
        RECT 80.235 189.430 80.700 195.060 ;
        RECT 81.000 189.430 81.465 195.060 ;
        RECT 83.800 189.430 84.265 195.060 ;
        RECT 84.565 189.430 85.030 195.060 ;
        RECT 85.330 189.430 85.795 195.060 ;
        RECT 86.095 189.430 86.560 195.060 ;
        RECT 86.875 193.860 87.340 195.060 ;
        RECT 87.645 189.430 88.110 195.060 ;
        RECT 88.410 189.430 88.875 195.060 ;
        RECT 89.175 189.430 89.640 195.060 ;
        RECT 89.940 189.430 90.405 195.060 ;
        RECT 90.705 189.430 91.170 195.060 ;
        RECT 91.470 189.430 91.935 195.060 ;
        RECT 92.235 189.430 92.700 195.060 ;
        RECT 93.000 189.430 93.465 195.060 ;
        RECT 93.765 189.430 94.230 195.060 ;
        RECT 94.530 189.430 94.995 195.060 ;
        RECT 95.295 189.430 95.760 195.060 ;
        RECT 96.060 189.430 96.525 195.060 ;
        RECT 96.825 189.430 97.290 195.060 ;
        RECT 97.590 189.430 98.055 195.060 ;
        RECT 98.355 189.430 98.820 195.060 ;
        RECT 99.120 189.430 99.585 195.060 ;
        RECT 99.885 189.430 100.350 195.060 ;
        RECT 100.650 189.430 101.115 195.060 ;
        RECT 9.400 180.435 57.000 180.440 ;
        RECT 63.915 180.435 64.380 182.295 ;
        RECT 6.770 177.540 64.380 180.435 ;
        RECT 63.915 174.865 64.380 177.540 ;
        RECT 64.680 174.865 65.145 182.295 ;
        RECT 65.445 174.865 65.910 182.295 ;
        RECT 66.305 174.865 66.770 180.795 ;
        RECT 67.185 174.865 67.650 182.295 ;
        RECT 67.950 174.865 68.415 182.295 ;
        RECT 68.715 174.865 69.180 182.295 ;
        RECT 69.480 174.865 69.945 182.295 ;
        RECT 70.245 174.865 70.710 180.795 ;
        RECT 71.055 174.865 71.520 182.295 ;
        RECT 71.820 174.865 72.285 182.295 ;
        RECT 72.585 174.865 73.050 182.295 ;
        RECT 73.350 174.865 73.815 182.295 ;
        RECT 74.115 174.865 74.580 182.295 ;
        RECT 74.880 174.865 75.345 182.295 ;
        RECT 75.645 174.865 76.110 182.295 ;
        RECT 76.410 174.865 76.875 182.295 ;
        RECT 77.175 174.865 77.640 182.295 ;
        RECT 77.940 174.865 78.405 182.295 ;
        RECT 78.705 174.865 79.170 182.295 ;
        RECT 79.470 174.865 79.935 182.295 ;
        RECT 9.645 86.905 57.245 86.910 ;
        RECT 63.075 86.905 63.540 89.265 ;
        RECT 6.770 84.010 63.540 86.905 ;
        RECT 63.075 83.635 63.540 84.010 ;
        RECT 63.840 83.635 64.305 89.265 ;
        RECT 64.605 83.635 65.070 89.265 ;
        RECT 65.370 88.060 65.835 89.265 ;
        RECT 66.345 83.635 66.810 89.265 ;
        RECT 67.110 83.635 67.575 89.265 ;
        RECT 67.875 83.635 68.340 89.265 ;
        RECT 68.640 83.635 69.105 89.265 ;
        RECT 69.405 88.065 69.870 89.265 ;
        RECT 70.215 83.635 70.680 89.265 ;
        RECT 70.980 83.635 71.445 89.265 ;
        RECT 71.745 83.635 72.210 89.265 ;
        RECT 72.510 83.635 72.975 89.265 ;
        RECT 73.275 83.635 73.740 89.265 ;
        RECT 74.395 88.065 74.860 89.265 ;
        RECT 75.570 83.635 76.035 89.265 ;
        RECT 76.335 83.635 76.800 89.265 ;
        RECT 77.100 83.635 77.565 89.265 ;
        RECT 77.865 83.635 78.330 89.265 ;
        RECT 78.630 83.635 79.095 89.265 ;
        RECT 79.395 83.635 79.860 89.265 ;
        RECT 80.160 83.635 80.625 89.265 ;
        RECT 82.960 83.635 83.425 89.265 ;
        RECT 83.725 83.635 84.190 89.265 ;
        RECT 84.490 83.635 84.955 89.265 ;
        RECT 85.255 83.635 85.720 89.265 ;
        RECT 86.035 88.065 86.500 89.265 ;
        RECT 86.805 83.635 87.270 89.265 ;
        RECT 87.570 83.635 88.035 89.265 ;
        RECT 88.335 83.635 88.800 89.265 ;
        RECT 89.100 83.635 89.565 89.265 ;
        RECT 89.865 83.635 90.330 89.265 ;
        RECT 90.630 83.635 91.095 89.265 ;
        RECT 91.395 83.635 91.860 89.265 ;
        RECT 92.160 83.635 92.625 89.265 ;
        RECT 92.925 83.635 93.390 89.265 ;
        RECT 93.690 83.635 94.155 89.265 ;
        RECT 94.455 83.635 94.920 89.265 ;
        RECT 95.220 83.635 95.685 89.265 ;
        RECT 95.985 83.635 96.450 89.265 ;
        RECT 96.750 83.635 97.215 89.265 ;
        RECT 97.515 83.635 97.980 89.265 ;
        RECT 98.280 83.635 98.745 89.265 ;
        RECT 99.045 83.635 99.510 89.265 ;
        RECT 99.810 83.635 100.275 89.265 ;
        RECT 9.645 74.485 57.245 74.490 ;
        RECT 63.075 74.485 63.540 76.500 ;
        RECT 6.770 71.590 63.540 74.485 ;
        RECT 63.075 69.070 63.540 71.590 ;
        RECT 63.840 69.070 64.305 76.500 ;
        RECT 64.605 69.070 65.070 76.500 ;
        RECT 65.465 69.070 65.930 75.000 ;
        RECT 66.345 69.070 66.810 76.500 ;
        RECT 67.110 69.070 67.575 76.500 ;
        RECT 67.875 69.070 68.340 76.500 ;
        RECT 68.640 69.070 69.105 76.500 ;
        RECT 69.405 69.070 69.870 75.000 ;
        RECT 70.215 69.070 70.680 76.500 ;
        RECT 70.980 69.070 71.445 76.500 ;
        RECT 71.745 69.070 72.210 76.500 ;
        RECT 72.510 69.070 72.975 76.500 ;
        RECT 73.275 69.070 73.740 76.500 ;
        RECT 74.040 69.070 74.505 76.500 ;
        RECT 74.805 69.070 75.270 76.500 ;
        RECT 75.570 69.070 76.035 76.500 ;
        RECT 76.335 69.070 76.800 76.500 ;
        RECT 77.100 69.070 77.565 76.500 ;
        RECT 77.865 69.070 78.330 76.500 ;
        RECT 78.630 69.070 79.095 76.500 ;
      LAYER met4 ;
        RECT 30.670 224.760 30.970 225.760 ;
        RECT 33.430 224.760 33.730 225.760 ;
        RECT 36.190 224.760 36.490 225.760 ;
        RECT 38.950 224.760 39.250 225.760 ;
        RECT 41.710 224.760 42.010 225.760 ;
        RECT 44.470 224.760 44.770 225.760 ;
        RECT 47.230 224.760 47.530 225.760 ;
        RECT 49.990 224.760 50.290 225.760 ;
        RECT 52.750 224.760 53.050 225.760 ;
        RECT 55.510 224.760 55.810 225.760 ;
        RECT 58.270 224.760 58.570 225.760 ;
        RECT 61.030 224.760 61.330 225.760 ;
        RECT 63.790 224.760 64.090 225.760 ;
        RECT 66.550 224.760 66.850 225.760 ;
        RECT 69.310 224.760 69.610 225.760 ;
        RECT 6.770 222.835 69.610 224.760 ;
        RECT 6.770 8.490 8.770 222.835 ;
    END
  END uio_oe[0]
  PIN uio_out[0]
    PORT
      LAYER met4 ;
        RECT 72.070 224.760 72.370 225.760 ;
    END
  END uio_out[0]
  PIN uo_out[0]
    PORT
      LAYER met4 ;
        RECT 94.150 224.760 94.450 225.760 ;
    END
  END uo_out[0]
  PIN uo_out[1]
    PORT
      LAYER met4 ;
        RECT 91.390 224.760 91.690 225.760 ;
    END
  END uo_out[1]
  PIN uo_out[2]
    PORT
      LAYER met4 ;
        RECT 88.630 224.760 88.930 225.760 ;
    END
  END uo_out[2]
  PIN uo_out[3]
    PORT
      LAYER met4 ;
        RECT 85.870 224.760 86.170 225.760 ;
    END
  END uo_out[3]
  PIN uo_out[4]
    PORT
      LAYER met4 ;
        RECT 83.110 224.760 83.410 225.760 ;
    END
  END uo_out[4]
  PIN uo_out[5]
    PORT
      LAYER met4 ;
        RECT 80.350 224.760 80.650 225.760 ;
    END
  END uo_out[5]
  PIN uo_out[6]
    PORT
      LAYER met4 ;
        RECT 77.590 224.760 77.890 225.760 ;
    END
  END uo_out[6]
  PIN uo_out[7]
    PORT
      LAYER met4 ;
        RECT 74.830 224.760 75.130 225.760 ;
    END
  END uo_out[7]
  OBS
      LAYER nwell ;
        RECT 63.915 195.050 144.625 214.600 ;
      LAYER pwell ;
        RECT 64.475 193.420 72.765 194.180 ;
        RECT 73.345 193.420 89.375 194.180 ;
        RECT 89.945 193.420 100.815 194.180 ;
        RECT 64.475 191.830 72.765 192.590 ;
        RECT 73.345 191.830 89.375 192.590 ;
        RECT 89.945 191.830 100.815 192.590 ;
        RECT 64.475 190.240 72.765 191.000 ;
        RECT 73.345 190.240 89.375 191.000 ;
        RECT 89.945 190.240 100.815 191.000 ;
      LAYER nwell ;
        RECT 64.650 182.415 79.610 189.370 ;
        RECT 103.875 166.410 144.625 195.050 ;
        RECT 63.075 89.255 143.785 108.805 ;
      LAYER pwell ;
        RECT 63.635 87.625 71.925 88.385 ;
        RECT 72.505 87.625 88.535 88.385 ;
        RECT 89.105 87.625 99.975 88.385 ;
        RECT 63.635 86.035 71.925 86.795 ;
        RECT 72.505 86.035 88.535 86.795 ;
        RECT 89.105 86.035 99.975 86.795 ;
        RECT 63.635 84.445 71.925 85.205 ;
        RECT 72.505 84.445 88.535 85.205 ;
        RECT 89.105 84.445 99.975 85.205 ;
      LAYER nwell ;
        RECT 63.810 76.620 78.770 83.575 ;
        RECT 103.035 60.615 143.785 89.255 ;
      LAYER li1 ;
        RECT 14.595 214.520 16.755 214.870 ;
        RECT 42.845 214.520 45.005 214.870 ;
        RECT 64.095 214.250 103.785 214.420 ;
        RECT 14.595 213.690 16.755 214.040 ;
        RECT 14.595 212.860 16.755 213.210 ;
        RECT 14.595 212.030 16.755 212.380 ;
        RECT 42.845 212.030 45.005 212.380 ;
        RECT 14.595 209.830 16.755 210.180 ;
        RECT 42.845 209.830 45.005 210.180 ;
        RECT 14.595 209.000 16.755 209.350 ;
        RECT 14.595 208.170 16.755 208.520 ;
        RECT 42.845 208.170 45.005 208.520 ;
        RECT 14.595 207.340 16.755 207.690 ;
        RECT 42.845 207.340 45.005 207.690 ;
        RECT 14.595 206.510 16.755 206.860 ;
        RECT 42.845 206.510 45.005 206.860 ;
        RECT 14.595 205.680 16.755 206.030 ;
        RECT 42.845 205.680 45.005 206.030 ;
        RECT 14.595 204.850 16.755 205.200 ;
        RECT 42.845 204.850 45.005 205.200 ;
        RECT 14.595 204.020 16.755 204.370 ;
        RECT 42.845 204.020 45.005 204.370 ;
        RECT 14.595 203.190 16.755 203.540 ;
        RECT 42.845 203.190 45.005 203.540 ;
        RECT 64.095 201.550 64.265 214.250 ;
        RECT 64.975 213.740 65.815 213.910 ;
        RECT 66.265 213.740 67.105 213.910 ;
        RECT 67.475 213.740 69.765 213.910 ;
        RECT 70.055 213.740 71.055 213.910 ;
        RECT 71.345 213.740 72.345 213.910 ;
        RECT 64.665 208.485 64.835 213.525 ;
        RECT 65.955 208.485 66.125 213.525 ;
        RECT 67.245 208.485 67.415 213.525 ;
        RECT 68.535 208.270 68.705 213.740 ;
        RECT 69.825 208.485 69.995 213.525 ;
        RECT 71.115 208.485 71.285 213.525 ;
        RECT 72.405 208.485 72.575 213.525 ;
        RECT 64.975 208.100 65.815 208.270 ;
        RECT 66.265 208.100 67.105 208.270 ;
        RECT 67.475 208.100 69.765 208.270 ;
        RECT 70.055 208.100 71.055 208.270 ;
        RECT 71.345 208.100 72.345 208.270 ;
        RECT 64.895 207.560 65.895 207.730 ;
        RECT 66.290 207.560 67.080 207.730 ;
        RECT 67.580 207.560 68.370 207.730 ;
        RECT 68.870 207.560 69.660 207.730 ;
        RECT 70.160 207.560 70.950 207.730 ;
        RECT 71.345 207.560 72.345 207.730 ;
        RECT 64.665 202.305 64.835 207.345 ;
        RECT 65.955 202.305 66.125 207.345 ;
        RECT 67.245 202.305 67.415 207.345 ;
        RECT 68.535 202.305 68.705 207.345 ;
        RECT 69.825 202.305 69.995 207.345 ;
        RECT 71.115 202.305 71.285 207.345 ;
        RECT 72.405 202.305 72.575 207.345 ;
        RECT 64.895 201.920 65.895 202.090 ;
        RECT 66.290 201.920 67.080 202.090 ;
        RECT 67.580 201.920 68.370 202.090 ;
        RECT 68.870 201.920 69.660 202.090 ;
        RECT 70.160 201.920 70.950 202.090 ;
        RECT 71.345 201.920 72.345 202.090 ;
        RECT 72.975 201.550 73.145 214.250 ;
        RECT 73.545 213.910 73.715 214.250 ;
        RECT 76.125 213.910 76.295 214.250 ;
        RECT 77.415 213.910 77.585 214.250 ;
        RECT 78.705 213.910 78.875 214.250 ;
        RECT 79.995 213.910 80.165 214.250 ;
        RECT 81.285 213.910 81.455 214.250 ;
        RECT 82.575 213.910 82.745 214.250 ;
        RECT 83.865 213.910 84.035 214.250 ;
        RECT 85.155 213.910 85.325 214.250 ;
        RECT 86.445 213.910 86.615 214.250 ;
        RECT 87.735 213.910 87.905 214.250 ;
        RECT 89.025 213.910 89.195 214.250 ;
        RECT 90.315 213.910 90.485 214.250 ;
        RECT 91.605 213.910 91.775 214.250 ;
        RECT 73.545 213.740 91.775 213.910 ;
        RECT 73.545 208.270 73.715 213.740 ;
        RECT 74.835 208.485 75.005 213.525 ;
        RECT 76.125 208.270 76.295 213.740 ;
        RECT 77.415 208.270 77.585 213.740 ;
        RECT 78.705 208.270 78.875 213.740 ;
        RECT 79.995 208.270 80.165 213.740 ;
        RECT 81.285 208.270 81.455 213.740 ;
        RECT 82.575 208.270 82.745 213.740 ;
        RECT 83.865 208.270 84.035 213.740 ;
        RECT 85.155 208.270 85.325 213.740 ;
        RECT 86.445 208.270 86.615 213.740 ;
        RECT 87.735 208.270 87.905 213.740 ;
        RECT 89.025 208.270 89.195 213.740 ;
        RECT 90.315 208.270 90.485 213.740 ;
        RECT 91.605 208.270 91.775 213.740 ;
        RECT 73.545 208.100 91.775 208.270 ;
        RECT 73.775 207.560 74.775 207.730 ;
        RECT 75.170 207.560 75.960 207.730 ;
        RECT 76.460 207.560 77.250 207.730 ;
        RECT 77.750 207.560 78.540 207.730 ;
        RECT 79.040 207.560 79.830 207.730 ;
        RECT 80.330 207.560 81.120 207.730 ;
        RECT 81.620 207.560 82.410 207.730 ;
        RECT 82.910 207.560 83.700 207.730 ;
        RECT 84.200 207.560 84.990 207.730 ;
        RECT 85.490 207.560 86.280 207.730 ;
        RECT 86.780 207.560 87.570 207.730 ;
        RECT 88.070 207.560 88.860 207.730 ;
        RECT 89.360 207.560 90.150 207.730 ;
        RECT 90.545 207.560 91.545 207.730 ;
        RECT 73.545 202.305 73.715 207.345 ;
        RECT 74.835 202.305 75.005 207.345 ;
        RECT 76.125 202.305 76.295 207.345 ;
        RECT 77.415 202.305 77.585 207.345 ;
        RECT 78.705 202.305 78.875 207.345 ;
        RECT 79.995 202.305 80.165 207.345 ;
        RECT 81.285 202.305 81.455 207.345 ;
        RECT 82.575 202.305 82.745 207.345 ;
        RECT 83.865 202.305 84.035 207.345 ;
        RECT 85.155 202.305 85.325 207.345 ;
        RECT 86.445 202.305 86.615 207.345 ;
        RECT 87.735 202.305 87.905 207.345 ;
        RECT 89.025 202.305 89.195 207.345 ;
        RECT 90.315 202.305 90.485 207.345 ;
        RECT 91.605 202.305 91.775 207.345 ;
        RECT 73.775 201.920 74.775 202.090 ;
        RECT 75.170 201.920 75.960 202.090 ;
        RECT 76.460 201.920 77.250 202.090 ;
        RECT 77.750 201.920 78.540 202.090 ;
        RECT 79.040 201.920 79.830 202.090 ;
        RECT 80.330 201.920 81.120 202.090 ;
        RECT 81.620 201.920 82.410 202.090 ;
        RECT 82.910 201.920 83.700 202.090 ;
        RECT 84.200 201.920 84.990 202.090 ;
        RECT 85.490 201.920 86.280 202.090 ;
        RECT 86.780 201.920 87.570 202.090 ;
        RECT 88.070 201.920 88.860 202.090 ;
        RECT 89.360 201.920 90.150 202.090 ;
        RECT 90.545 201.920 91.545 202.090 ;
        RECT 92.155 201.550 92.345 214.250 ;
        RECT 92.725 213.910 92.895 214.250 ;
        RECT 94.015 213.910 94.185 214.250 ;
        RECT 95.305 213.910 95.475 214.250 ;
        RECT 96.595 213.910 96.765 214.250 ;
        RECT 97.885 213.910 98.055 214.250 ;
        RECT 99.175 213.910 99.345 214.250 ;
        RECT 100.465 213.910 100.635 214.250 ;
        RECT 101.755 213.910 101.925 214.250 ;
        RECT 103.045 213.910 103.215 214.250 ;
        RECT 92.725 213.740 103.215 213.910 ;
        RECT 92.725 208.270 92.895 213.740 ;
        RECT 94.015 208.270 94.185 213.740 ;
        RECT 95.305 208.270 95.475 213.740 ;
        RECT 96.595 208.270 96.765 213.740 ;
        RECT 97.885 208.270 98.055 213.740 ;
        RECT 99.175 208.270 99.345 213.740 ;
        RECT 100.465 208.270 100.635 213.740 ;
        RECT 101.755 208.270 101.925 213.740 ;
        RECT 103.045 208.270 103.215 213.740 ;
        RECT 92.725 208.100 103.215 208.270 ;
        RECT 92.955 207.560 93.955 207.730 ;
        RECT 94.350 207.560 95.140 207.730 ;
        RECT 95.640 207.560 96.430 207.730 ;
        RECT 96.930 207.560 97.720 207.730 ;
        RECT 98.220 207.560 99.010 207.730 ;
        RECT 99.510 207.560 100.300 207.730 ;
        RECT 100.800 207.560 101.590 207.730 ;
        RECT 101.985 207.560 102.985 207.730 ;
        RECT 92.725 202.305 92.895 207.345 ;
        RECT 94.015 202.305 94.185 207.345 ;
        RECT 95.305 202.305 95.475 207.345 ;
        RECT 96.595 202.305 96.765 207.345 ;
        RECT 97.885 202.305 98.055 207.345 ;
        RECT 99.175 202.305 99.345 207.345 ;
        RECT 100.465 202.305 100.635 207.345 ;
        RECT 101.755 202.305 101.925 207.345 ;
        RECT 103.045 202.305 103.215 207.345 ;
        RECT 92.955 201.920 93.955 202.090 ;
        RECT 94.350 201.920 95.140 202.090 ;
        RECT 95.640 201.920 96.430 202.090 ;
        RECT 96.930 201.920 97.720 202.090 ;
        RECT 98.220 201.920 99.010 202.090 ;
        RECT 99.510 201.920 100.300 202.090 ;
        RECT 100.800 201.920 101.590 202.090 ;
        RECT 101.985 201.920 102.985 202.090 ;
        RECT 103.615 201.550 103.785 214.250 ;
        RECT 64.095 201.380 103.785 201.550 ;
        RECT 14.595 200.990 16.755 201.340 ;
        RECT 42.845 200.990 45.005 201.340 ;
        RECT 14.595 200.160 16.755 200.510 ;
        RECT 42.845 200.160 45.005 200.510 ;
        RECT 14.595 199.330 16.755 199.680 ;
        RECT 42.845 199.330 45.005 199.680 ;
        RECT 14.595 198.500 16.755 198.850 ;
        RECT 42.845 198.500 45.005 198.850 ;
        RECT 14.595 197.670 16.755 198.020 ;
        RECT 42.845 197.670 45.005 198.020 ;
        RECT 14.595 196.840 16.755 197.190 ;
        RECT 42.845 196.840 45.005 197.190 ;
        RECT 14.595 196.010 16.755 196.360 ;
        RECT 42.845 196.010 45.005 196.360 ;
        RECT 64.095 195.910 64.265 201.380 ;
        RECT 64.665 196.125 64.835 201.165 ;
        RECT 65.955 195.910 66.125 201.380 ;
        RECT 67.245 195.910 67.415 201.380 ;
        RECT 68.535 195.910 68.705 201.380 ;
        RECT 69.825 195.910 69.995 201.380 ;
        RECT 71.115 195.910 71.285 201.380 ;
        RECT 72.405 196.125 72.575 201.165 ;
        RECT 72.975 195.910 73.145 201.380 ;
        RECT 73.545 195.910 73.715 201.380 ;
        RECT 74.835 195.910 75.005 201.380 ;
        RECT 76.125 195.910 76.295 201.380 ;
        RECT 77.415 195.910 77.585 201.380 ;
        RECT 78.705 195.910 78.875 201.380 ;
        RECT 79.995 195.910 80.165 201.380 ;
        RECT 81.285 195.910 81.455 201.380 ;
        RECT 82.575 195.910 82.745 201.380 ;
        RECT 83.865 195.910 84.035 201.380 ;
        RECT 85.155 195.910 85.325 201.380 ;
        RECT 86.445 195.910 86.615 201.380 ;
        RECT 87.735 195.910 87.905 201.380 ;
        RECT 89.025 195.910 89.195 201.380 ;
        RECT 90.315 195.910 90.485 201.380 ;
        RECT 91.605 195.910 91.775 201.380 ;
        RECT 92.155 195.910 92.345 201.380 ;
        RECT 92.725 195.910 92.895 201.380 ;
        RECT 94.015 195.910 94.185 201.380 ;
        RECT 95.305 195.910 95.475 201.380 ;
        RECT 96.595 195.910 96.765 201.380 ;
        RECT 97.885 195.910 98.055 201.380 ;
        RECT 99.175 195.910 99.345 201.380 ;
        RECT 100.465 195.910 100.635 201.380 ;
        RECT 101.755 195.910 101.925 201.380 ;
        RECT 103.045 195.910 103.215 201.380 ;
        RECT 103.615 195.910 103.785 201.380 ;
        RECT 64.095 195.740 103.785 195.910 ;
        RECT 14.595 195.180 16.755 195.530 ;
        RECT 42.845 195.180 45.005 195.530 ;
        RECT 64.095 195.400 64.265 195.740 ;
        RECT 72.975 195.400 73.145 195.740 ;
        RECT 73.545 195.400 73.715 195.740 ;
        RECT 74.835 195.400 75.005 195.740 ;
        RECT 76.125 195.400 76.295 195.740 ;
        RECT 77.415 195.400 77.585 195.740 ;
        RECT 78.705 195.400 78.875 195.740 ;
        RECT 79.995 195.400 80.165 195.740 ;
        RECT 81.285 195.400 81.455 195.740 ;
        RECT 82.575 195.400 82.745 195.740 ;
        RECT 83.865 195.400 84.035 195.740 ;
        RECT 85.155 195.400 85.325 195.740 ;
        RECT 86.445 195.400 86.615 195.740 ;
        RECT 87.735 195.400 87.905 195.740 ;
        RECT 89.025 195.400 89.195 195.740 ;
        RECT 90.315 195.400 90.485 195.740 ;
        RECT 91.605 195.400 91.775 195.740 ;
        RECT 92.155 195.400 92.345 195.740 ;
        RECT 92.725 195.400 92.895 195.740 ;
        RECT 94.015 195.400 94.185 195.740 ;
        RECT 95.305 195.400 95.475 195.740 ;
        RECT 96.595 195.400 96.765 195.740 ;
        RECT 97.885 195.400 98.055 195.740 ;
        RECT 99.175 195.400 99.345 195.740 ;
        RECT 100.465 195.400 100.635 195.740 ;
        RECT 101.755 195.400 101.925 195.740 ;
        RECT 103.045 195.400 103.215 195.740 ;
        RECT 103.615 195.400 103.785 195.740 ;
        RECT 64.095 195.230 103.785 195.400 ;
        RECT 104.055 214.250 144.445 214.420 ;
        RECT 65.000 192.650 65.790 192.820 ;
        RECT 66.290 192.650 67.080 192.820 ;
        RECT 70.160 192.650 70.950 192.820 ;
        RECT 71.450 192.650 72.240 192.820 ;
        RECT 75.160 192.650 75.950 192.820 ;
        RECT 76.450 192.650 77.240 192.820 ;
        RECT 77.740 192.650 78.530 192.820 ;
        RECT 79.030 192.650 79.820 192.820 ;
        RECT 80.320 192.650 81.110 192.820 ;
        RECT 81.610 192.650 82.400 192.820 ;
        RECT 82.900 192.650 83.690 192.820 ;
        RECT 84.190 192.650 84.980 192.820 ;
        RECT 85.480 192.650 86.270 192.820 ;
        RECT 86.770 192.650 87.560 192.820 ;
        RECT 91.760 192.650 92.550 192.820 ;
        RECT 93.050 192.650 93.840 192.820 ;
        RECT 94.340 192.650 95.130 192.820 ;
        RECT 95.630 192.650 96.420 192.820 ;
        RECT 96.920 192.650 97.710 192.820 ;
        RECT 98.210 192.650 99.000 192.820 ;
        RECT 64.665 191.940 64.835 192.480 ;
        RECT 65.955 191.940 66.125 192.480 ;
        RECT 67.245 191.940 67.415 192.480 ;
        RECT 68.535 191.940 68.705 192.480 ;
        RECT 69.825 191.940 69.995 192.480 ;
        RECT 71.115 191.940 71.285 192.480 ;
        RECT 72.405 191.940 72.575 192.480 ;
        RECT 76.115 191.940 76.285 192.480 ;
        RECT 78.695 191.940 78.865 192.480 ;
        RECT 81.275 191.940 81.445 192.480 ;
        RECT 83.855 191.940 84.025 192.480 ;
        RECT 86.435 191.940 86.605 192.480 ;
        RECT 92.715 191.940 92.885 192.480 ;
        RECT 95.295 191.940 95.465 192.480 ;
        RECT 97.875 191.940 98.045 192.480 ;
        RECT 65.000 191.600 65.790 191.770 ;
        RECT 66.290 191.600 67.080 191.770 ;
        RECT 70.160 191.600 70.950 191.770 ;
        RECT 71.450 191.600 72.240 191.770 ;
        RECT 75.160 191.600 75.950 191.770 ;
        RECT 76.450 191.600 77.240 191.770 ;
        RECT 77.740 191.600 78.530 191.770 ;
        RECT 79.030 191.600 79.820 191.770 ;
        RECT 80.320 191.600 81.110 191.770 ;
        RECT 81.610 191.600 82.400 191.770 ;
        RECT 82.900 191.600 83.690 191.770 ;
        RECT 84.190 191.600 84.980 191.770 ;
        RECT 85.480 191.600 86.270 191.770 ;
        RECT 86.770 191.600 87.560 191.770 ;
        RECT 91.760 191.600 92.550 191.770 ;
        RECT 93.050 191.600 93.840 191.770 ;
        RECT 94.340 191.600 95.130 191.770 ;
        RECT 95.630 191.600 96.420 191.770 ;
        RECT 96.920 191.600 97.710 191.770 ;
        RECT 98.210 191.600 99.000 191.770 ;
        RECT 64.830 189.020 79.430 189.190 ;
        RECT 64.830 182.765 65.000 189.020 ;
        RECT 71.120 188.505 72.580 188.675 ;
        RECT 71.120 188.160 71.290 188.505 ;
        RECT 65.710 187.990 71.290 188.160 ;
        RECT 65.400 187.235 65.570 187.775 ;
        RECT 66.690 187.235 66.860 187.775 ;
        RECT 67.980 187.020 68.150 187.990 ;
        RECT 69.270 187.020 69.440 187.990 ;
        RECT 70.560 187.055 70.730 187.990 ;
        RECT 71.120 187.235 71.290 187.990 ;
        RECT 72.410 187.235 72.580 188.505 ;
        RECT 73.280 188.085 74.120 188.255 ;
        RECT 75.130 188.210 75.970 188.380 ;
        RECT 76.420 188.210 77.260 188.380 ;
        RECT 77.710 188.210 78.550 188.380 ;
        RECT 72.970 187.330 73.140 187.870 ;
        RECT 74.260 187.330 74.430 187.870 ;
        RECT 74.820 187.365 74.990 187.995 ;
        RECT 76.110 187.365 76.280 187.995 ;
        RECT 77.400 187.365 77.570 187.995 ;
        RECT 78.690 187.365 78.860 187.995 ;
        RECT 71.120 187.065 72.580 187.235 ;
        RECT 71.120 187.055 71.290 187.065 ;
        RECT 70.220 187.020 71.290 187.055 ;
        RECT 65.710 186.885 71.290 187.020 ;
        RECT 73.280 186.945 74.120 187.115 ;
        RECT 75.130 186.980 75.970 187.150 ;
        RECT 76.420 186.980 77.260 187.150 ;
        RECT 77.710 186.980 78.550 187.150 ;
        RECT 65.710 186.850 70.390 186.885 ;
        RECT 71.460 186.525 72.240 186.695 ;
        RECT 74.820 186.575 76.280 186.610 ;
        RECT 65.710 186.310 66.550 186.480 ;
        RECT 67.030 186.310 67.810 186.480 ;
        RECT 68.320 186.310 69.100 186.480 ;
        RECT 69.270 186.310 70.730 186.480 ;
        RECT 73.310 186.440 76.280 186.575 ;
        RECT 76.450 186.440 77.230 186.610 ;
        RECT 77.710 186.440 78.550 186.610 ;
        RECT 73.310 186.405 74.990 186.440 ;
        RECT 65.400 185.555 65.570 186.095 ;
        RECT 66.690 185.555 66.860 186.095 ;
        RECT 67.980 185.555 68.150 186.095 ;
        RECT 69.270 185.340 69.440 186.310 ;
        RECT 70.560 185.340 70.730 186.310 ;
        RECT 71.120 185.470 71.290 186.310 ;
        RECT 72.410 185.470 72.580 186.310 ;
        RECT 72.970 185.650 73.140 186.190 ;
        RECT 74.260 185.650 74.430 186.190 ;
        RECT 74.820 185.435 74.990 186.405 ;
        RECT 65.710 185.170 66.550 185.340 ;
        RECT 67.030 185.170 67.810 185.340 ;
        RECT 68.320 185.170 69.100 185.340 ;
        RECT 69.270 185.170 70.730 185.340 ;
        RECT 73.310 185.380 74.990 185.435 ;
        RECT 76.110 185.380 76.280 186.440 ;
        RECT 77.400 185.595 77.570 186.225 ;
        RECT 78.690 185.595 78.860 186.225 ;
        RECT 73.310 185.265 76.280 185.380 ;
        RECT 71.460 185.085 72.240 185.255 ;
        RECT 74.820 185.210 76.280 185.265 ;
        RECT 76.450 185.210 77.230 185.380 ;
        RECT 77.710 185.210 78.550 185.380 ;
        RECT 72.970 184.840 74.995 184.895 ;
        RECT 65.710 184.715 70.730 184.800 ;
        RECT 72.970 184.725 78.550 184.840 ;
        RECT 65.710 184.630 72.580 184.715 ;
        RECT 65.400 183.875 65.570 184.415 ;
        RECT 66.690 183.875 66.860 184.415 ;
        RECT 67.980 183.660 68.150 184.630 ;
        RECT 69.270 183.660 69.440 184.630 ;
        RECT 70.560 184.545 72.580 184.630 ;
        RECT 70.560 183.660 70.730 184.545 ;
        RECT 71.120 183.660 71.290 184.545 ;
        RECT 65.710 183.490 71.290 183.660 ;
        RECT 71.120 183.275 71.290 183.490 ;
        RECT 72.410 183.275 72.580 184.545 ;
        RECT 72.970 183.755 73.140 184.725 ;
        RECT 74.260 183.755 74.430 184.725 ;
        RECT 74.820 184.670 78.550 184.725 ;
        RECT 74.820 183.755 74.990 184.670 ;
        RECT 72.970 183.610 74.990 183.755 ;
        RECT 76.110 183.610 76.280 184.670 ;
        RECT 77.400 183.825 77.570 184.455 ;
        RECT 78.690 183.825 78.860 184.455 ;
        RECT 72.970 183.585 78.550 183.610 ;
        RECT 74.820 183.440 78.550 183.585 ;
        RECT 71.120 183.105 72.580 183.275 ;
        RECT 74.870 182.765 75.065 182.770 ;
        RECT 79.260 182.765 79.430 189.020 ;
        RECT 92.735 186.180 94.895 186.530 ;
        RECT 99.115 186.180 101.275 186.530 ;
        RECT 100.335 183.150 102.495 183.500 ;
        RECT 64.830 182.595 79.430 182.765 ;
        RECT 92.205 182.320 94.365 182.670 ;
        RECT 100.335 182.320 102.495 182.670 ;
        RECT 100.335 181.490 102.495 181.840 ;
        RECT 66.480 179.840 67.260 180.010 ;
        RECT 67.740 179.840 68.580 180.010 ;
        RECT 69.620 179.760 70.400 179.930 ;
        RECT 70.910 179.760 72.030 179.930 ;
        RECT 72.200 179.760 72.980 179.930 ;
        RECT 73.490 179.760 74.270 179.930 ;
        RECT 75.000 179.760 76.460 179.930 ;
        RECT 76.630 179.760 77.410 179.930 ;
        RECT 67.430 178.960 67.600 179.670 ;
        RECT 68.720 178.960 68.890 179.670 ;
        RECT 69.280 179.050 69.450 179.590 ;
        RECT 71.860 178.880 72.030 179.760 ;
        RECT 74.440 179.050 74.610 179.590 ;
        RECT 75.000 178.880 75.170 179.760 ;
        RECT 76.290 178.880 76.460 179.760 ;
        RECT 66.480 178.620 67.260 178.790 ;
        RECT 67.740 178.620 68.580 178.790 ;
        RECT 69.620 178.710 70.400 178.880 ;
        RECT 70.910 178.710 72.030 178.880 ;
        RECT 72.200 178.710 72.980 178.880 ;
        RECT 73.490 178.710 74.270 178.880 ;
        RECT 75.000 178.710 76.460 178.880 ;
        RECT 76.630 178.710 77.410 178.880 ;
        RECT 91.935 178.460 94.095 178.810 ;
        RECT 64.925 175.050 67.085 175.400 ;
        RECT 68.675 175.050 70.835 175.400 ;
        RECT 73.050 175.050 75.210 175.400 ;
        RECT 76.800 175.050 78.960 175.400 ;
        RECT 104.055 166.760 104.225 214.250 ;
        RECT 104.855 213.740 105.855 213.910 ;
        RECT 106.145 213.740 107.145 213.910 ;
        RECT 107.435 213.740 108.435 213.910 ;
        RECT 108.725 213.740 109.725 213.910 ;
        RECT 110.015 213.740 111.015 213.910 ;
        RECT 111.305 213.740 112.305 213.910 ;
        RECT 112.595 213.740 113.595 213.910 ;
        RECT 113.885 213.740 114.885 213.910 ;
        RECT 115.175 213.740 116.175 213.910 ;
        RECT 116.465 213.740 117.465 213.910 ;
        RECT 117.755 213.740 118.755 213.910 ;
        RECT 119.045 213.740 120.045 213.910 ;
        RECT 120.335 213.740 121.335 213.910 ;
        RECT 121.625 213.740 122.625 213.910 ;
        RECT 122.915 213.740 123.915 213.910 ;
        RECT 104.625 167.485 104.795 213.525 ;
        RECT 105.915 167.485 106.085 213.525 ;
        RECT 107.205 167.485 107.375 213.525 ;
        RECT 108.495 167.485 108.665 213.525 ;
        RECT 109.785 167.485 109.955 213.525 ;
        RECT 111.075 167.485 111.245 213.525 ;
        RECT 112.365 167.485 112.535 213.525 ;
        RECT 113.655 167.485 113.825 213.525 ;
        RECT 114.945 167.485 115.115 213.525 ;
        RECT 116.235 167.485 116.405 213.525 ;
        RECT 117.525 167.485 117.695 213.525 ;
        RECT 118.815 167.485 118.985 213.525 ;
        RECT 120.105 167.485 120.275 213.525 ;
        RECT 121.395 167.485 121.565 213.525 ;
        RECT 122.685 167.485 122.855 213.525 ;
        RECT 123.975 167.485 124.145 213.525 ;
        RECT 104.855 167.100 105.855 167.270 ;
        RECT 106.145 167.100 107.145 167.270 ;
        RECT 107.435 167.100 108.435 167.270 ;
        RECT 108.725 167.100 109.725 167.270 ;
        RECT 110.015 167.100 111.015 167.270 ;
        RECT 111.305 167.100 112.305 167.270 ;
        RECT 112.595 167.100 113.595 167.270 ;
        RECT 113.885 167.100 114.885 167.270 ;
        RECT 115.175 167.100 116.175 167.270 ;
        RECT 116.465 167.100 117.465 167.270 ;
        RECT 117.755 167.100 118.755 167.270 ;
        RECT 119.045 167.100 120.045 167.270 ;
        RECT 120.335 167.100 121.335 167.270 ;
        RECT 121.625 167.100 122.625 167.270 ;
        RECT 122.915 167.100 123.915 167.270 ;
        RECT 124.545 166.760 124.715 214.250 ;
        RECT 104.055 166.590 124.715 166.760 ;
        RECT 125.075 166.760 125.245 214.250 ;
        RECT 125.875 213.740 126.875 213.910 ;
        RECT 127.165 213.740 128.165 213.910 ;
        RECT 128.455 213.740 129.455 213.910 ;
        RECT 129.745 213.740 130.745 213.910 ;
        RECT 131.035 213.740 132.035 213.910 ;
        RECT 132.325 213.740 133.325 213.910 ;
        RECT 133.615 213.740 134.615 213.910 ;
        RECT 134.905 213.740 135.905 213.910 ;
        RECT 136.195 213.740 137.195 213.910 ;
        RECT 137.485 213.740 138.485 213.910 ;
        RECT 138.775 213.740 139.775 213.910 ;
        RECT 140.065 213.740 141.065 213.910 ;
        RECT 141.355 213.740 142.355 213.910 ;
        RECT 142.645 213.740 143.645 213.910 ;
        RECT 125.645 167.485 125.815 213.525 ;
        RECT 126.935 167.485 127.105 213.525 ;
        RECT 128.225 167.485 128.395 213.525 ;
        RECT 129.515 167.485 129.685 213.525 ;
        RECT 130.805 167.485 130.975 213.525 ;
        RECT 132.095 167.485 132.265 213.525 ;
        RECT 133.385 167.485 133.555 213.525 ;
        RECT 134.675 167.485 134.845 213.525 ;
        RECT 135.965 167.485 136.135 213.525 ;
        RECT 137.255 167.485 137.425 213.525 ;
        RECT 138.545 167.485 138.715 213.525 ;
        RECT 139.835 167.485 140.005 213.525 ;
        RECT 141.125 167.485 141.295 213.525 ;
        RECT 142.415 167.485 142.585 213.525 ;
        RECT 143.705 167.485 143.875 213.525 ;
        RECT 125.875 167.100 126.875 167.270 ;
        RECT 127.165 167.100 128.165 167.270 ;
        RECT 128.455 167.100 129.455 167.270 ;
        RECT 129.745 167.100 130.745 167.270 ;
        RECT 131.035 167.100 132.035 167.270 ;
        RECT 132.325 167.100 133.325 167.270 ;
        RECT 133.615 167.100 134.615 167.270 ;
        RECT 134.905 167.100 135.905 167.270 ;
        RECT 136.195 167.100 137.195 167.270 ;
        RECT 137.485 167.100 138.485 167.270 ;
        RECT 138.775 167.100 139.775 167.270 ;
        RECT 140.065 167.100 141.065 167.270 ;
        RECT 141.355 167.100 142.355 167.270 ;
        RECT 142.645 167.100 143.645 167.270 ;
        RECT 144.275 166.760 144.445 214.250 ;
        RECT 125.075 166.590 144.445 166.760 ;
        RECT 63.255 108.455 102.945 108.625 ;
        RECT 63.255 95.755 63.425 108.455 ;
        RECT 64.135 107.945 64.975 108.115 ;
        RECT 65.425 107.945 66.265 108.115 ;
        RECT 66.635 107.945 68.925 108.115 ;
        RECT 69.215 107.945 70.215 108.115 ;
        RECT 70.505 107.945 71.505 108.115 ;
        RECT 63.825 102.690 63.995 107.730 ;
        RECT 65.115 102.690 65.285 107.730 ;
        RECT 66.405 102.690 66.575 107.730 ;
        RECT 67.695 102.475 67.865 107.945 ;
        RECT 68.985 102.690 69.155 107.730 ;
        RECT 70.275 102.690 70.445 107.730 ;
        RECT 71.565 102.690 71.735 107.730 ;
        RECT 64.135 102.305 64.975 102.475 ;
        RECT 65.425 102.305 66.265 102.475 ;
        RECT 66.635 102.305 68.925 102.475 ;
        RECT 69.215 102.305 70.215 102.475 ;
        RECT 70.505 102.305 71.505 102.475 ;
        RECT 64.055 101.765 65.055 101.935 ;
        RECT 65.450 101.765 66.240 101.935 ;
        RECT 66.740 101.765 67.530 101.935 ;
        RECT 68.030 101.765 68.820 101.935 ;
        RECT 69.320 101.765 70.110 101.935 ;
        RECT 70.505 101.765 71.505 101.935 ;
        RECT 63.825 96.510 63.995 101.550 ;
        RECT 65.115 96.510 65.285 101.550 ;
        RECT 66.405 96.510 66.575 101.550 ;
        RECT 67.695 96.510 67.865 101.550 ;
        RECT 68.985 96.510 69.155 101.550 ;
        RECT 70.275 96.510 70.445 101.550 ;
        RECT 71.565 96.510 71.735 101.550 ;
        RECT 64.055 96.125 65.055 96.295 ;
        RECT 65.450 96.125 66.240 96.295 ;
        RECT 66.740 96.125 67.530 96.295 ;
        RECT 68.030 96.125 68.820 96.295 ;
        RECT 69.320 96.125 70.110 96.295 ;
        RECT 70.505 96.125 71.505 96.295 ;
        RECT 72.135 95.755 72.305 108.455 ;
        RECT 72.705 108.115 72.875 108.455 ;
        RECT 75.285 108.115 75.455 108.455 ;
        RECT 76.575 108.115 76.745 108.455 ;
        RECT 77.865 108.115 78.035 108.455 ;
        RECT 79.155 108.115 79.325 108.455 ;
        RECT 80.445 108.115 80.615 108.455 ;
        RECT 81.735 108.115 81.905 108.455 ;
        RECT 83.025 108.115 83.195 108.455 ;
        RECT 84.315 108.115 84.485 108.455 ;
        RECT 85.605 108.115 85.775 108.455 ;
        RECT 86.895 108.115 87.065 108.455 ;
        RECT 88.185 108.115 88.355 108.455 ;
        RECT 89.475 108.115 89.645 108.455 ;
        RECT 90.765 108.115 90.935 108.455 ;
        RECT 72.705 107.945 90.935 108.115 ;
        RECT 72.705 102.475 72.875 107.945 ;
        RECT 73.995 102.690 74.165 107.730 ;
        RECT 75.285 102.475 75.455 107.945 ;
        RECT 76.575 102.475 76.745 107.945 ;
        RECT 77.865 102.475 78.035 107.945 ;
        RECT 79.155 102.475 79.325 107.945 ;
        RECT 80.445 102.475 80.615 107.945 ;
        RECT 81.735 102.475 81.905 107.945 ;
        RECT 83.025 102.475 83.195 107.945 ;
        RECT 84.315 102.475 84.485 107.945 ;
        RECT 85.605 102.475 85.775 107.945 ;
        RECT 86.895 102.475 87.065 107.945 ;
        RECT 88.185 102.475 88.355 107.945 ;
        RECT 89.475 102.475 89.645 107.945 ;
        RECT 90.765 102.475 90.935 107.945 ;
        RECT 72.705 102.305 90.935 102.475 ;
        RECT 72.935 101.765 73.935 101.935 ;
        RECT 74.330 101.765 75.120 101.935 ;
        RECT 75.620 101.765 76.410 101.935 ;
        RECT 76.910 101.765 77.700 101.935 ;
        RECT 78.200 101.765 78.990 101.935 ;
        RECT 79.490 101.765 80.280 101.935 ;
        RECT 80.780 101.765 81.570 101.935 ;
        RECT 82.070 101.765 82.860 101.935 ;
        RECT 83.360 101.765 84.150 101.935 ;
        RECT 84.650 101.765 85.440 101.935 ;
        RECT 85.940 101.765 86.730 101.935 ;
        RECT 87.230 101.765 88.020 101.935 ;
        RECT 88.520 101.765 89.310 101.935 ;
        RECT 89.705 101.765 90.705 101.935 ;
        RECT 72.705 96.510 72.875 101.550 ;
        RECT 73.995 96.510 74.165 101.550 ;
        RECT 75.285 96.510 75.455 101.550 ;
        RECT 76.575 96.510 76.745 101.550 ;
        RECT 77.865 96.510 78.035 101.550 ;
        RECT 79.155 96.510 79.325 101.550 ;
        RECT 80.445 96.510 80.615 101.550 ;
        RECT 81.735 96.510 81.905 101.550 ;
        RECT 83.025 96.510 83.195 101.550 ;
        RECT 84.315 96.510 84.485 101.550 ;
        RECT 85.605 96.510 85.775 101.550 ;
        RECT 86.895 96.510 87.065 101.550 ;
        RECT 88.185 96.510 88.355 101.550 ;
        RECT 89.475 96.510 89.645 101.550 ;
        RECT 90.765 96.510 90.935 101.550 ;
        RECT 72.935 96.125 73.935 96.295 ;
        RECT 74.330 96.125 75.120 96.295 ;
        RECT 75.620 96.125 76.410 96.295 ;
        RECT 76.910 96.125 77.700 96.295 ;
        RECT 78.200 96.125 78.990 96.295 ;
        RECT 79.490 96.125 80.280 96.295 ;
        RECT 80.780 96.125 81.570 96.295 ;
        RECT 82.070 96.125 82.860 96.295 ;
        RECT 83.360 96.125 84.150 96.295 ;
        RECT 84.650 96.125 85.440 96.295 ;
        RECT 85.940 96.125 86.730 96.295 ;
        RECT 87.230 96.125 88.020 96.295 ;
        RECT 88.520 96.125 89.310 96.295 ;
        RECT 89.705 96.125 90.705 96.295 ;
        RECT 91.315 95.755 91.505 108.455 ;
        RECT 91.885 108.115 92.055 108.455 ;
        RECT 93.175 108.115 93.345 108.455 ;
        RECT 94.465 108.115 94.635 108.455 ;
        RECT 95.755 108.115 95.925 108.455 ;
        RECT 97.045 108.115 97.215 108.455 ;
        RECT 98.335 108.115 98.505 108.455 ;
        RECT 99.625 108.115 99.795 108.455 ;
        RECT 100.915 108.115 101.085 108.455 ;
        RECT 102.205 108.115 102.375 108.455 ;
        RECT 91.885 107.945 102.375 108.115 ;
        RECT 91.885 102.475 92.055 107.945 ;
        RECT 93.175 102.475 93.345 107.945 ;
        RECT 94.465 102.475 94.635 107.945 ;
        RECT 95.755 102.475 95.925 107.945 ;
        RECT 97.045 102.475 97.215 107.945 ;
        RECT 98.335 102.475 98.505 107.945 ;
        RECT 99.625 102.475 99.795 107.945 ;
        RECT 100.915 102.475 101.085 107.945 ;
        RECT 102.205 102.475 102.375 107.945 ;
        RECT 91.885 102.305 102.375 102.475 ;
        RECT 92.115 101.765 93.115 101.935 ;
        RECT 93.510 101.765 94.300 101.935 ;
        RECT 94.800 101.765 95.590 101.935 ;
        RECT 96.090 101.765 96.880 101.935 ;
        RECT 97.380 101.765 98.170 101.935 ;
        RECT 98.670 101.765 99.460 101.935 ;
        RECT 99.960 101.765 100.750 101.935 ;
        RECT 101.145 101.765 102.145 101.935 ;
        RECT 91.885 96.510 92.055 101.550 ;
        RECT 93.175 96.510 93.345 101.550 ;
        RECT 94.465 96.510 94.635 101.550 ;
        RECT 95.755 96.510 95.925 101.550 ;
        RECT 97.045 96.510 97.215 101.550 ;
        RECT 98.335 96.510 98.505 101.550 ;
        RECT 99.625 96.510 99.795 101.550 ;
        RECT 100.915 96.510 101.085 101.550 ;
        RECT 102.205 96.510 102.375 101.550 ;
        RECT 92.115 96.125 93.115 96.295 ;
        RECT 93.510 96.125 94.300 96.295 ;
        RECT 94.800 96.125 95.590 96.295 ;
        RECT 96.090 96.125 96.880 96.295 ;
        RECT 97.380 96.125 98.170 96.295 ;
        RECT 98.670 96.125 99.460 96.295 ;
        RECT 99.960 96.125 100.750 96.295 ;
        RECT 101.145 96.125 102.145 96.295 ;
        RECT 102.775 95.755 102.945 108.455 ;
        RECT 63.255 95.585 102.945 95.755 ;
        RECT 63.255 90.115 63.425 95.585 ;
        RECT 63.825 90.330 63.995 95.370 ;
        RECT 65.115 90.115 65.285 95.585 ;
        RECT 66.405 90.115 66.575 95.585 ;
        RECT 67.695 90.115 67.865 95.585 ;
        RECT 68.985 90.115 69.155 95.585 ;
        RECT 70.275 90.115 70.445 95.585 ;
        RECT 71.565 90.330 71.735 95.370 ;
        RECT 72.135 90.115 72.305 95.585 ;
        RECT 72.705 90.115 72.875 95.585 ;
        RECT 73.995 90.115 74.165 95.585 ;
        RECT 75.285 90.115 75.455 95.585 ;
        RECT 76.575 90.115 76.745 95.585 ;
        RECT 77.865 90.115 78.035 95.585 ;
        RECT 79.155 90.115 79.325 95.585 ;
        RECT 80.445 90.115 80.615 95.585 ;
        RECT 81.735 90.115 81.905 95.585 ;
        RECT 83.025 90.115 83.195 95.585 ;
        RECT 84.315 90.115 84.485 95.585 ;
        RECT 85.605 90.115 85.775 95.585 ;
        RECT 86.895 90.115 87.065 95.585 ;
        RECT 88.185 90.115 88.355 95.585 ;
        RECT 89.475 90.115 89.645 95.585 ;
        RECT 90.765 90.115 90.935 95.585 ;
        RECT 91.315 90.115 91.505 95.585 ;
        RECT 91.885 90.115 92.055 95.585 ;
        RECT 93.175 90.115 93.345 95.585 ;
        RECT 94.465 90.115 94.635 95.585 ;
        RECT 95.755 90.115 95.925 95.585 ;
        RECT 97.045 90.115 97.215 95.585 ;
        RECT 98.335 90.115 98.505 95.585 ;
        RECT 99.625 90.115 99.795 95.585 ;
        RECT 100.915 90.115 101.085 95.585 ;
        RECT 102.205 90.115 102.375 95.585 ;
        RECT 102.775 90.115 102.945 95.585 ;
        RECT 63.255 89.945 102.945 90.115 ;
        RECT 63.255 89.605 63.425 89.945 ;
        RECT 72.135 89.605 72.305 89.945 ;
        RECT 72.705 89.605 72.875 89.945 ;
        RECT 73.995 89.605 74.165 89.945 ;
        RECT 75.285 89.605 75.455 89.945 ;
        RECT 76.575 89.605 76.745 89.945 ;
        RECT 77.865 89.605 78.035 89.945 ;
        RECT 79.155 89.605 79.325 89.945 ;
        RECT 80.445 89.605 80.615 89.945 ;
        RECT 81.735 89.605 81.905 89.945 ;
        RECT 83.025 89.605 83.195 89.945 ;
        RECT 84.315 89.605 84.485 89.945 ;
        RECT 85.605 89.605 85.775 89.945 ;
        RECT 86.895 89.605 87.065 89.945 ;
        RECT 88.185 89.605 88.355 89.945 ;
        RECT 89.475 89.605 89.645 89.945 ;
        RECT 90.765 89.605 90.935 89.945 ;
        RECT 91.315 89.605 91.505 89.945 ;
        RECT 91.885 89.605 92.055 89.945 ;
        RECT 93.175 89.605 93.345 89.945 ;
        RECT 94.465 89.605 94.635 89.945 ;
        RECT 95.755 89.605 95.925 89.945 ;
        RECT 97.045 89.605 97.215 89.945 ;
        RECT 98.335 89.605 98.505 89.945 ;
        RECT 99.625 89.605 99.795 89.945 ;
        RECT 100.915 89.605 101.085 89.945 ;
        RECT 102.205 89.605 102.375 89.945 ;
        RECT 102.775 89.605 102.945 89.945 ;
        RECT 63.255 89.435 102.945 89.605 ;
        RECT 103.215 108.455 143.605 108.625 ;
        RECT 64.160 86.855 64.950 87.025 ;
        RECT 65.450 86.855 66.240 87.025 ;
        RECT 69.320 86.855 70.110 87.025 ;
        RECT 70.610 86.855 71.400 87.025 ;
        RECT 74.320 86.855 75.110 87.025 ;
        RECT 75.610 86.855 76.400 87.025 ;
        RECT 76.900 86.855 77.690 87.025 ;
        RECT 78.190 86.855 78.980 87.025 ;
        RECT 79.480 86.855 80.270 87.025 ;
        RECT 80.770 86.855 81.560 87.025 ;
        RECT 82.060 86.855 82.850 87.025 ;
        RECT 83.350 86.855 84.140 87.025 ;
        RECT 84.640 86.855 85.430 87.025 ;
        RECT 85.930 86.855 86.720 87.025 ;
        RECT 90.920 86.855 91.710 87.025 ;
        RECT 92.210 86.855 93.000 87.025 ;
        RECT 93.500 86.855 94.290 87.025 ;
        RECT 94.790 86.855 95.580 87.025 ;
        RECT 96.080 86.855 96.870 87.025 ;
        RECT 97.370 86.855 98.160 87.025 ;
        RECT 63.825 86.145 63.995 86.685 ;
        RECT 65.115 86.145 65.285 86.685 ;
        RECT 66.405 86.145 66.575 86.685 ;
        RECT 67.695 86.145 67.865 86.685 ;
        RECT 68.985 86.145 69.155 86.685 ;
        RECT 70.275 86.145 70.445 86.685 ;
        RECT 71.565 86.145 71.735 86.685 ;
        RECT 75.275 86.145 75.445 86.685 ;
        RECT 77.855 86.145 78.025 86.685 ;
        RECT 80.435 86.145 80.605 86.685 ;
        RECT 83.015 86.145 83.185 86.685 ;
        RECT 85.595 86.145 85.765 86.685 ;
        RECT 91.875 86.145 92.045 86.685 ;
        RECT 94.455 86.145 94.625 86.685 ;
        RECT 97.035 86.145 97.205 86.685 ;
        RECT 64.160 85.805 64.950 85.975 ;
        RECT 65.450 85.805 66.240 85.975 ;
        RECT 69.320 85.805 70.110 85.975 ;
        RECT 70.610 85.805 71.400 85.975 ;
        RECT 74.320 85.805 75.110 85.975 ;
        RECT 75.610 85.805 76.400 85.975 ;
        RECT 76.900 85.805 77.690 85.975 ;
        RECT 78.190 85.805 78.980 85.975 ;
        RECT 79.480 85.805 80.270 85.975 ;
        RECT 80.770 85.805 81.560 85.975 ;
        RECT 82.060 85.805 82.850 85.975 ;
        RECT 83.350 85.805 84.140 85.975 ;
        RECT 84.640 85.805 85.430 85.975 ;
        RECT 85.930 85.805 86.720 85.975 ;
        RECT 90.920 85.805 91.710 85.975 ;
        RECT 92.210 85.805 93.000 85.975 ;
        RECT 93.500 85.805 94.290 85.975 ;
        RECT 94.790 85.805 95.580 85.975 ;
        RECT 96.080 85.805 96.870 85.975 ;
        RECT 97.370 85.805 98.160 85.975 ;
        RECT 63.990 83.225 78.590 83.395 ;
        RECT 63.990 76.970 64.160 83.225 ;
        RECT 70.280 82.710 71.740 82.880 ;
        RECT 70.280 82.365 70.450 82.710 ;
        RECT 64.870 82.195 70.450 82.365 ;
        RECT 64.560 81.440 64.730 81.980 ;
        RECT 65.850 81.440 66.020 81.980 ;
        RECT 67.140 81.225 67.310 82.195 ;
        RECT 68.430 81.225 68.600 82.195 ;
        RECT 69.720 81.260 69.890 82.195 ;
        RECT 70.280 81.440 70.450 82.195 ;
        RECT 71.570 81.440 71.740 82.710 ;
        RECT 72.440 82.290 73.280 82.460 ;
        RECT 74.290 82.415 75.130 82.585 ;
        RECT 75.580 82.415 76.420 82.585 ;
        RECT 76.870 82.415 77.710 82.585 ;
        RECT 72.130 81.535 72.300 82.075 ;
        RECT 73.420 81.535 73.590 82.075 ;
        RECT 73.980 81.570 74.150 82.200 ;
        RECT 75.270 81.570 75.440 82.200 ;
        RECT 76.560 81.570 76.730 82.200 ;
        RECT 77.850 81.570 78.020 82.200 ;
        RECT 70.280 81.270 71.740 81.440 ;
        RECT 70.280 81.260 70.450 81.270 ;
        RECT 69.380 81.225 70.450 81.260 ;
        RECT 64.870 81.090 70.450 81.225 ;
        RECT 72.440 81.150 73.280 81.320 ;
        RECT 74.290 81.185 75.130 81.355 ;
        RECT 75.580 81.185 76.420 81.355 ;
        RECT 76.870 81.185 77.710 81.355 ;
        RECT 64.870 81.055 69.550 81.090 ;
        RECT 70.620 80.730 71.400 80.900 ;
        RECT 73.980 80.780 75.440 80.815 ;
        RECT 64.870 80.515 65.710 80.685 ;
        RECT 66.190 80.515 66.970 80.685 ;
        RECT 67.480 80.515 68.260 80.685 ;
        RECT 68.430 80.515 69.890 80.685 ;
        RECT 72.470 80.645 75.440 80.780 ;
        RECT 75.610 80.645 76.390 80.815 ;
        RECT 76.870 80.645 77.710 80.815 ;
        RECT 72.470 80.610 74.150 80.645 ;
        RECT 64.560 79.760 64.730 80.300 ;
        RECT 65.850 79.760 66.020 80.300 ;
        RECT 67.140 79.760 67.310 80.300 ;
        RECT 68.430 79.545 68.600 80.515 ;
        RECT 69.720 79.545 69.890 80.515 ;
        RECT 70.280 79.675 70.450 80.515 ;
        RECT 71.570 79.675 71.740 80.515 ;
        RECT 72.130 79.855 72.300 80.395 ;
        RECT 73.420 79.855 73.590 80.395 ;
        RECT 73.980 79.640 74.150 80.610 ;
        RECT 64.870 79.375 65.710 79.545 ;
        RECT 66.190 79.375 66.970 79.545 ;
        RECT 67.480 79.375 68.260 79.545 ;
        RECT 68.430 79.375 69.890 79.545 ;
        RECT 72.470 79.585 74.150 79.640 ;
        RECT 75.270 79.585 75.440 80.645 ;
        RECT 76.560 79.800 76.730 80.430 ;
        RECT 77.850 79.800 78.020 80.430 ;
        RECT 72.470 79.470 75.440 79.585 ;
        RECT 70.620 79.290 71.400 79.460 ;
        RECT 73.980 79.415 75.440 79.470 ;
        RECT 75.610 79.415 76.390 79.585 ;
        RECT 76.870 79.415 77.710 79.585 ;
        RECT 72.130 79.045 74.155 79.100 ;
        RECT 64.870 78.920 69.890 79.005 ;
        RECT 72.130 78.930 77.710 79.045 ;
        RECT 64.870 78.835 71.740 78.920 ;
        RECT 64.560 78.080 64.730 78.620 ;
        RECT 65.850 78.080 66.020 78.620 ;
        RECT 67.140 77.865 67.310 78.835 ;
        RECT 68.430 77.865 68.600 78.835 ;
        RECT 69.720 78.750 71.740 78.835 ;
        RECT 69.720 77.865 69.890 78.750 ;
        RECT 70.280 77.865 70.450 78.750 ;
        RECT 64.870 77.695 70.450 77.865 ;
        RECT 70.280 77.480 70.450 77.695 ;
        RECT 71.570 77.480 71.740 78.750 ;
        RECT 72.130 77.960 72.300 78.930 ;
        RECT 73.420 77.960 73.590 78.930 ;
        RECT 73.980 78.875 77.710 78.930 ;
        RECT 73.980 77.960 74.150 78.875 ;
        RECT 72.130 77.815 74.150 77.960 ;
        RECT 75.270 77.815 75.440 78.875 ;
        RECT 76.560 78.030 76.730 78.660 ;
        RECT 77.850 78.030 78.020 78.660 ;
        RECT 72.130 77.790 77.710 77.815 ;
        RECT 73.980 77.645 77.710 77.790 ;
        RECT 70.280 77.310 71.740 77.480 ;
        RECT 74.030 76.970 74.225 76.975 ;
        RECT 78.420 76.970 78.590 83.225 ;
        RECT 91.895 80.385 94.055 80.735 ;
        RECT 98.275 80.385 100.435 80.735 ;
        RECT 99.495 77.355 101.655 77.705 ;
        RECT 63.990 76.800 78.590 76.970 ;
        RECT 91.365 76.525 93.525 76.875 ;
        RECT 99.495 76.525 101.655 76.875 ;
        RECT 99.495 75.695 101.655 76.045 ;
        RECT 65.640 74.045 66.420 74.215 ;
        RECT 66.900 74.045 67.740 74.215 ;
        RECT 68.780 73.965 69.560 74.135 ;
        RECT 70.070 73.965 71.190 74.135 ;
        RECT 71.360 73.965 72.140 74.135 ;
        RECT 72.650 73.965 73.430 74.135 ;
        RECT 74.160 73.965 75.620 74.135 ;
        RECT 75.790 73.965 76.570 74.135 ;
        RECT 66.590 73.165 66.760 73.875 ;
        RECT 67.880 73.165 68.050 73.875 ;
        RECT 68.440 73.255 68.610 73.795 ;
        RECT 71.020 73.085 71.190 73.965 ;
        RECT 73.600 73.255 73.770 73.795 ;
        RECT 74.160 73.085 74.330 73.965 ;
        RECT 75.450 73.085 75.620 73.965 ;
        RECT 65.640 72.825 66.420 72.995 ;
        RECT 66.900 72.825 67.740 72.995 ;
        RECT 68.780 72.915 69.560 73.085 ;
        RECT 70.070 72.915 71.190 73.085 ;
        RECT 71.360 72.915 72.140 73.085 ;
        RECT 72.650 72.915 73.430 73.085 ;
        RECT 74.160 72.915 75.620 73.085 ;
        RECT 75.790 72.915 76.570 73.085 ;
        RECT 91.095 72.665 93.255 73.015 ;
        RECT 64.085 69.255 66.245 69.605 ;
        RECT 67.835 69.255 69.995 69.605 ;
        RECT 72.210 69.255 74.370 69.605 ;
        RECT 75.960 69.255 78.120 69.605 ;
        RECT 103.215 60.965 103.385 108.455 ;
        RECT 104.015 107.945 105.015 108.115 ;
        RECT 105.305 107.945 106.305 108.115 ;
        RECT 106.595 107.945 107.595 108.115 ;
        RECT 107.885 107.945 108.885 108.115 ;
        RECT 109.175 107.945 110.175 108.115 ;
        RECT 110.465 107.945 111.465 108.115 ;
        RECT 111.755 107.945 112.755 108.115 ;
        RECT 113.045 107.945 114.045 108.115 ;
        RECT 114.335 107.945 115.335 108.115 ;
        RECT 115.625 107.945 116.625 108.115 ;
        RECT 116.915 107.945 117.915 108.115 ;
        RECT 118.205 107.945 119.205 108.115 ;
        RECT 119.495 107.945 120.495 108.115 ;
        RECT 120.785 107.945 121.785 108.115 ;
        RECT 122.075 107.945 123.075 108.115 ;
        RECT 103.785 61.690 103.955 107.730 ;
        RECT 105.075 61.690 105.245 107.730 ;
        RECT 106.365 61.690 106.535 107.730 ;
        RECT 107.655 61.690 107.825 107.730 ;
        RECT 108.945 61.690 109.115 107.730 ;
        RECT 110.235 61.690 110.405 107.730 ;
        RECT 111.525 61.690 111.695 107.730 ;
        RECT 112.815 61.690 112.985 107.730 ;
        RECT 114.105 61.690 114.275 107.730 ;
        RECT 115.395 61.690 115.565 107.730 ;
        RECT 116.685 61.690 116.855 107.730 ;
        RECT 117.975 61.690 118.145 107.730 ;
        RECT 119.265 61.690 119.435 107.730 ;
        RECT 120.555 61.690 120.725 107.730 ;
        RECT 121.845 61.690 122.015 107.730 ;
        RECT 123.135 61.690 123.305 107.730 ;
        RECT 104.015 61.305 105.015 61.475 ;
        RECT 105.305 61.305 106.305 61.475 ;
        RECT 106.595 61.305 107.595 61.475 ;
        RECT 107.885 61.305 108.885 61.475 ;
        RECT 109.175 61.305 110.175 61.475 ;
        RECT 110.465 61.305 111.465 61.475 ;
        RECT 111.755 61.305 112.755 61.475 ;
        RECT 113.045 61.305 114.045 61.475 ;
        RECT 114.335 61.305 115.335 61.475 ;
        RECT 115.625 61.305 116.625 61.475 ;
        RECT 116.915 61.305 117.915 61.475 ;
        RECT 118.205 61.305 119.205 61.475 ;
        RECT 119.495 61.305 120.495 61.475 ;
        RECT 120.785 61.305 121.785 61.475 ;
        RECT 122.075 61.305 123.075 61.475 ;
        RECT 123.705 60.965 123.875 108.455 ;
        RECT 103.215 60.795 123.875 60.965 ;
        RECT 124.235 60.965 124.405 108.455 ;
        RECT 125.035 107.945 126.035 108.115 ;
        RECT 126.325 107.945 127.325 108.115 ;
        RECT 127.615 107.945 128.615 108.115 ;
        RECT 128.905 107.945 129.905 108.115 ;
        RECT 130.195 107.945 131.195 108.115 ;
        RECT 131.485 107.945 132.485 108.115 ;
        RECT 132.775 107.945 133.775 108.115 ;
        RECT 134.065 107.945 135.065 108.115 ;
        RECT 135.355 107.945 136.355 108.115 ;
        RECT 136.645 107.945 137.645 108.115 ;
        RECT 137.935 107.945 138.935 108.115 ;
        RECT 139.225 107.945 140.225 108.115 ;
        RECT 140.515 107.945 141.515 108.115 ;
        RECT 141.805 107.945 142.805 108.115 ;
        RECT 124.805 61.690 124.975 107.730 ;
        RECT 126.095 61.690 126.265 107.730 ;
        RECT 127.385 61.690 127.555 107.730 ;
        RECT 128.675 61.690 128.845 107.730 ;
        RECT 129.965 61.690 130.135 107.730 ;
        RECT 131.255 61.690 131.425 107.730 ;
        RECT 132.545 61.690 132.715 107.730 ;
        RECT 133.835 61.690 134.005 107.730 ;
        RECT 135.125 61.690 135.295 107.730 ;
        RECT 136.415 61.690 136.585 107.730 ;
        RECT 137.705 61.690 137.875 107.730 ;
        RECT 138.995 61.690 139.165 107.730 ;
        RECT 140.285 61.690 140.455 107.730 ;
        RECT 141.575 61.690 141.745 107.730 ;
        RECT 142.865 61.690 143.035 107.730 ;
        RECT 125.035 61.305 126.035 61.475 ;
        RECT 126.325 61.305 127.325 61.475 ;
        RECT 127.615 61.305 128.615 61.475 ;
        RECT 128.905 61.305 129.905 61.475 ;
        RECT 130.195 61.305 131.195 61.475 ;
        RECT 131.485 61.305 132.485 61.475 ;
        RECT 132.775 61.305 133.775 61.475 ;
        RECT 134.065 61.305 135.065 61.475 ;
        RECT 135.355 61.305 136.355 61.475 ;
        RECT 136.645 61.305 137.645 61.475 ;
        RECT 137.935 61.305 138.935 61.475 ;
        RECT 139.225 61.305 140.225 61.475 ;
        RECT 140.515 61.305 141.515 61.475 ;
        RECT 141.805 61.305 142.805 61.475 ;
        RECT 143.435 60.965 143.605 108.455 ;
        RECT 124.235 60.795 143.605 60.965 ;
      LAYER met1 ;
        RECT 14.625 214.570 16.730 214.820 ;
        RECT 42.870 214.570 44.975 214.820 ;
        RECT 64.015 214.500 64.335 214.505 ;
        RECT 14.625 212.910 16.730 213.990 ;
        RECT 64.015 213.870 103.875 214.500 ;
        RECT 104.475 214.220 133.325 214.450 ;
        RECT 106.280 213.940 107.010 213.970 ;
        RECT 107.570 213.940 108.300 213.970 ;
        RECT 108.860 213.940 109.590 213.970 ;
        RECT 110.150 213.940 110.880 213.970 ;
        RECT 111.440 213.940 112.170 213.970 ;
        RECT 112.730 213.940 113.460 213.970 ;
        RECT 114.020 213.940 114.750 213.970 ;
        RECT 115.310 213.940 116.040 213.970 ;
        RECT 116.600 213.940 117.330 213.970 ;
        RECT 117.890 213.940 118.620 213.970 ;
        RECT 119.180 213.940 119.910 213.970 ;
        RECT 120.470 213.940 121.200 213.970 ;
        RECT 121.760 213.940 122.490 213.970 ;
        RECT 123.050 213.940 123.780 213.970 ;
        RECT 64.015 213.710 68.350 213.870 ;
        RECT 68.890 213.710 73.220 213.870 ;
        RECT 14.625 212.080 16.730 212.330 ;
        RECT 42.870 212.080 44.975 212.330 ;
        RECT 14.625 209.880 16.730 210.130 ;
        RECT 42.870 209.880 44.975 210.130 ;
        RECT 14.625 208.220 16.730 209.300 ;
        RECT 14.625 206.560 16.730 207.640 ;
        RECT 42.870 207.390 44.975 208.470 ;
        RECT 64.015 208.300 64.335 213.710 ;
        RECT 64.635 208.300 64.865 213.710 ;
        RECT 65.925 208.300 66.155 213.710 ;
        RECT 67.215 212.380 67.445 213.710 ;
        RECT 69.795 212.380 70.025 213.710 ;
        RECT 67.170 211.740 67.490 212.380 ;
        RECT 69.750 211.740 70.070 212.380 ;
        RECT 67.215 210.650 67.445 211.740 ;
        RECT 69.795 210.650 70.025 211.740 ;
        RECT 67.170 210.010 67.490 210.650 ;
        RECT 69.750 210.010 70.070 210.650 ;
        RECT 67.215 208.300 67.445 210.010 ;
        RECT 68.460 209.145 68.780 209.785 ;
        RECT 64.015 208.070 68.350 208.300 ;
        RECT 14.625 204.900 16.730 205.980 ;
        RECT 42.870 205.730 44.975 206.810 ;
        RECT 13.375 203.735 16.730 204.650 ;
        RECT 42.870 204.070 44.975 205.150 ;
        RECT 13.375 200.805 14.310 203.735 ;
        RECT 14.625 203.240 16.730 203.490 ;
        RECT 42.870 203.240 44.975 203.490 ;
        RECT 14.625 201.040 16.730 201.290 ;
        RECT 42.870 201.040 44.975 201.290 ;
        RECT 13.375 199.890 16.730 200.805 ;
        RECT 14.625 198.550 16.730 199.630 ;
        RECT 42.870 199.380 44.975 200.460 ;
        RECT 14.625 196.890 16.730 197.970 ;
        RECT 42.870 197.720 44.975 198.800 ;
        RECT 14.625 196.310 14.945 196.665 ;
        RECT 14.625 196.060 16.730 196.310 ;
        RECT 42.870 196.060 44.975 197.140 ;
        RECT 14.625 195.705 14.945 196.060 ;
        RECT 14.625 195.230 16.730 195.480 ;
        RECT 42.870 195.230 44.975 195.480 ;
        RECT 64.015 195.135 64.335 208.070 ;
        RECT 64.635 207.855 66.340 207.860 ;
        RECT 64.635 207.535 67.065 207.855 ;
        RECT 64.635 202.125 64.865 207.535 ;
        RECT 65.020 207.530 65.770 207.535 ;
        RECT 66.310 207.530 67.060 207.535 ;
        RECT 65.925 203.015 66.155 207.325 ;
        RECT 65.925 202.325 66.160 203.015 ;
        RECT 65.930 202.125 66.160 202.325 ;
        RECT 64.635 201.805 67.065 202.125 ;
        RECT 64.635 201.800 66.160 201.805 ;
        RECT 64.635 201.350 65.770 201.580 ;
        RECT 64.635 195.940 64.865 201.350 ;
        RECT 64.635 195.710 65.770 195.940 ;
        RECT 65.930 192.850 66.160 201.800 ;
        RECT 67.215 199.475 67.445 208.070 ;
        RECT 67.605 207.760 68.355 207.855 ;
        RECT 67.600 207.535 68.355 207.760 ;
        RECT 67.600 207.530 68.350 207.535 ;
        RECT 67.605 202.120 68.355 202.125 ;
        RECT 67.600 201.890 68.355 202.120 ;
        RECT 67.605 201.805 68.355 201.890 ;
        RECT 67.655 201.800 68.295 201.805 ;
        RECT 68.505 200.520 68.735 209.145 ;
        RECT 69.795 208.300 70.025 210.010 ;
        RECT 71.085 208.300 71.315 213.710 ;
        RECT 72.375 208.300 72.605 213.710 ;
        RECT 72.900 208.300 73.220 213.710 ;
        RECT 73.515 213.710 75.085 213.870 ;
        RECT 77.340 213.830 77.660 213.870 ;
        RECT 79.920 213.830 80.240 213.870 ;
        RECT 82.500 213.830 82.820 213.870 ;
        RECT 85.080 213.830 85.400 213.870 ;
        RECT 87.660 213.830 87.980 213.870 ;
        RECT 90.240 213.830 91.845 213.870 ;
        RECT 73.515 212.380 73.745 213.710 ;
        RECT 74.805 212.380 75.045 213.710 ;
        RECT 77.385 212.380 77.615 213.830 ;
        RECT 78.630 212.610 78.950 213.250 ;
        RECT 73.470 211.740 73.790 212.380 ;
        RECT 74.760 211.740 75.080 212.380 ;
        RECT 77.340 211.740 77.660 212.380 ;
        RECT 73.515 210.650 73.745 211.740 ;
        RECT 74.805 210.650 75.045 211.740 ;
        RECT 76.050 210.855 76.370 211.495 ;
        RECT 73.470 210.010 73.790 210.650 ;
        RECT 74.760 210.010 75.080 210.650 ;
        RECT 68.890 208.070 73.220 208.300 ;
        RECT 68.895 207.760 69.645 207.855 ;
        RECT 68.890 207.535 69.645 207.760 ;
        RECT 68.890 207.530 69.640 207.535 ;
        RECT 68.895 202.120 69.645 202.125 ;
        RECT 68.890 201.890 69.645 202.120 ;
        RECT 68.895 201.805 69.645 201.890 ;
        RECT 68.945 201.800 69.585 201.805 ;
        RECT 68.460 199.880 68.780 200.520 ;
        RECT 67.170 198.835 67.490 199.475 ;
        RECT 67.215 197.840 67.445 198.835 ;
        RECT 67.170 197.200 67.490 197.840 ;
        RECT 67.215 195.230 67.445 197.200 ;
        RECT 66.365 192.850 67.005 192.940 ;
        RECT 64.635 192.620 66.160 192.850 ;
        RECT 66.310 192.620 67.060 192.850 ;
        RECT 64.635 191.800 64.865 192.620 ;
        RECT 65.925 191.800 66.160 192.620 ;
        RECT 64.635 191.570 66.160 191.800 ;
        RECT 66.310 191.570 67.060 191.800 ;
        RECT 66.365 191.480 67.005 191.570 ;
        RECT 67.215 190.925 67.445 192.460 ;
        RECT 68.505 191.960 68.735 199.880 ;
        RECT 69.795 199.475 70.025 208.070 ;
        RECT 70.910 207.855 72.605 207.860 ;
        RECT 70.185 207.760 72.605 207.855 ;
        RECT 70.180 207.535 72.605 207.760 ;
        RECT 70.180 207.530 70.930 207.535 ;
        RECT 71.470 207.530 72.220 207.535 ;
        RECT 71.085 203.005 71.315 207.325 ;
        RECT 71.085 202.325 71.320 203.005 ;
        RECT 71.090 202.130 71.320 202.325 ;
        RECT 72.375 202.130 72.605 207.535 ;
        RECT 70.910 202.125 72.605 202.130 ;
        RECT 70.185 202.120 72.605 202.125 ;
        RECT 70.180 201.890 72.605 202.120 ;
        RECT 70.185 201.805 72.605 201.890 ;
        RECT 70.235 201.800 70.875 201.805 ;
        RECT 69.745 199.155 70.065 199.475 ;
        RECT 69.750 198.835 70.070 199.155 ;
        RECT 69.795 197.840 70.025 198.835 ;
        RECT 69.750 197.200 70.070 197.840 ;
        RECT 69.795 195.230 70.025 197.200 ;
        RECT 70.235 192.850 70.875 192.940 ;
        RECT 71.090 192.850 71.320 201.805 ;
        RECT 71.470 201.350 72.605 201.580 ;
        RECT 72.375 195.940 72.605 201.350 ;
        RECT 71.470 195.710 72.605 195.940 ;
        RECT 72.375 195.705 72.605 195.710 ;
        RECT 72.900 195.455 73.220 208.070 ;
        RECT 73.515 208.300 73.745 210.010 ;
        RECT 74.805 208.300 75.045 210.010 ;
        RECT 75.250 209.780 75.570 209.785 ;
        RECT 75.250 209.145 75.890 209.780 ;
        RECT 75.570 209.140 75.890 209.145 ;
        RECT 73.515 208.070 75.045 208.300 ;
        RECT 73.515 207.760 73.745 208.070 ;
        RECT 74.805 207.760 75.045 208.070 ;
        RECT 73.515 207.530 75.045 207.760 ;
        RECT 75.190 207.530 75.940 207.850 ;
        RECT 73.515 202.120 73.745 207.530 ;
        RECT 74.805 207.160 75.045 207.530 ;
        RECT 74.805 202.120 75.035 207.160 ;
        RECT 73.515 201.890 75.035 202.120 ;
        RECT 73.515 201.580 73.745 201.890 ;
        RECT 74.805 201.580 75.035 201.890 ;
        RECT 75.190 201.800 75.940 202.120 ;
        RECT 73.515 201.350 75.035 201.580 ;
        RECT 73.515 199.475 73.745 201.350 ;
        RECT 74.805 199.475 75.035 201.350 ;
        RECT 73.470 198.835 73.790 199.475 ;
        RECT 74.760 198.835 75.080 199.475 ;
        RECT 73.515 197.840 73.745 198.835 ;
        RECT 74.805 197.840 75.035 198.835 ;
        RECT 76.095 198.650 76.325 210.855 ;
        RECT 77.385 210.650 77.615 211.740 ;
        RECT 77.340 210.010 77.660 210.650 ;
        RECT 76.480 207.530 77.230 207.850 ;
        RECT 76.480 201.800 77.230 202.120 ;
        RECT 77.385 199.475 77.615 210.010 ;
        RECT 77.770 207.530 78.520 207.850 ;
        RECT 77.770 201.800 78.520 202.120 ;
        RECT 77.340 198.835 77.660 199.475 ;
        RECT 76.050 198.010 76.370 198.650 ;
        RECT 77.385 197.840 77.615 198.835 ;
        RECT 73.470 197.200 73.790 197.840 ;
        RECT 74.760 197.200 75.080 197.840 ;
        RECT 77.340 197.200 77.660 197.840 ;
        RECT 73.515 195.940 73.745 197.200 ;
        RECT 74.805 195.940 75.035 197.200 ;
        RECT 73.515 195.805 75.080 195.940 ;
        RECT 77.385 195.805 77.615 197.200 ;
        RECT 78.675 197.050 78.905 212.610 ;
        RECT 79.965 212.380 80.195 213.830 ;
        RECT 82.545 212.385 82.775 213.830 ;
        RECT 83.790 212.610 84.110 213.250 ;
        RECT 79.915 211.740 80.235 212.380 ;
        RECT 82.500 211.745 82.820 212.385 ;
        RECT 79.965 210.650 80.195 211.740 ;
        RECT 81.210 210.855 81.530 211.495 ;
        RECT 79.920 210.010 80.240 210.650 ;
        RECT 79.060 207.530 79.810 207.850 ;
        RECT 79.060 201.800 79.810 202.120 ;
        RECT 79.965 199.475 80.195 210.010 ;
        RECT 80.350 207.530 81.100 207.850 ;
        RECT 81.260 207.325 81.490 210.855 ;
        RECT 82.545 210.650 82.775 211.745 ;
        RECT 82.500 210.010 82.820 210.650 ;
        RECT 81.640 207.530 82.390 207.850 ;
        RECT 81.255 202.325 81.490 207.325 ;
        RECT 80.350 201.800 81.100 202.120 ;
        RECT 79.920 198.835 80.240 199.475 ;
        RECT 79.965 197.840 80.195 198.835 ;
        RECT 81.260 198.650 81.490 202.325 ;
        RECT 81.640 201.800 82.390 202.120 ;
        RECT 82.545 199.475 82.775 210.010 ;
        RECT 82.930 207.530 83.680 207.850 ;
        RECT 82.930 201.800 83.680 202.120 ;
        RECT 82.500 198.835 82.820 199.475 ;
        RECT 81.210 198.010 81.530 198.650 ;
        RECT 79.920 197.200 80.240 197.840 ;
        RECT 78.630 196.410 78.950 197.050 ;
        RECT 79.965 195.805 80.195 197.200 ;
        RECT 73.470 195.710 75.080 195.805 ;
        RECT 73.470 195.455 73.790 195.710 ;
        RECT 74.760 195.455 75.080 195.710 ;
        RECT 77.340 195.455 77.660 195.805 ;
        RECT 79.920 195.455 80.240 195.805 ;
        RECT 71.640 195.185 80.815 195.455 ;
        RECT 73.470 195.165 73.790 195.185 ;
        RECT 74.760 195.165 75.080 195.185 ;
        RECT 77.340 195.165 77.660 195.185 ;
        RECT 79.920 195.165 80.240 195.185 ;
        RECT 70.180 192.620 70.930 192.850 ;
        RECT 71.090 192.620 72.605 192.850 ;
        RECT 75.180 192.620 75.930 192.940 ;
        RECT 76.470 192.620 77.220 192.940 ;
        RECT 77.760 192.620 78.510 192.940 ;
        RECT 79.050 192.620 79.800 192.940 ;
        RECT 80.340 192.620 81.090 192.940 ;
        RECT 71.090 192.460 71.320 192.620 ;
        RECT 69.795 190.935 70.025 192.460 ;
        RECT 71.085 192.445 71.320 192.460 ;
        RECT 71.085 191.800 71.315 192.445 ;
        RECT 72.375 191.800 72.605 192.620 ;
        RECT 81.260 192.460 81.490 198.010 ;
        RECT 82.545 197.840 82.775 198.835 ;
        RECT 82.500 197.200 82.820 197.840 ;
        RECT 82.545 195.805 82.775 197.200 ;
        RECT 83.835 197.050 84.065 212.610 ;
        RECT 85.125 212.380 85.355 213.830 ;
        RECT 87.705 212.380 87.935 213.830 ;
        RECT 90.240 213.710 91.805 213.830 ;
        RECT 88.950 212.610 89.270 213.250 ;
        RECT 85.080 211.740 85.400 212.380 ;
        RECT 87.660 211.740 87.980 212.380 ;
        RECT 85.125 210.650 85.355 211.740 ;
        RECT 86.370 210.855 86.690 211.495 ;
        RECT 85.080 210.010 85.400 210.650 ;
        RECT 84.220 207.530 84.970 207.850 ;
        RECT 84.220 201.800 84.970 202.120 ;
        RECT 85.125 199.475 85.355 210.010 ;
        RECT 85.510 207.530 86.260 207.850 ;
        RECT 85.510 201.800 86.260 202.120 ;
        RECT 85.080 198.835 85.400 199.475 ;
        RECT 85.125 197.840 85.355 198.835 ;
        RECT 86.415 198.650 86.645 210.855 ;
        RECT 87.705 210.650 87.935 211.740 ;
        RECT 87.660 210.010 87.980 210.650 ;
        RECT 86.800 207.530 87.550 207.850 ;
        RECT 86.800 201.800 87.550 202.120 ;
        RECT 87.705 199.475 87.935 210.010 ;
        RECT 88.090 207.530 88.840 207.850 ;
        RECT 88.090 201.800 88.840 202.120 ;
        RECT 87.660 198.835 87.980 199.475 ;
        RECT 86.370 198.010 86.690 198.650 ;
        RECT 87.705 197.840 87.935 198.835 ;
        RECT 85.080 197.200 85.400 197.840 ;
        RECT 87.660 197.200 87.980 197.840 ;
        RECT 83.790 196.410 84.110 197.050 ;
        RECT 85.125 195.805 85.355 197.200 ;
        RECT 87.705 195.805 87.935 197.200 ;
        RECT 88.995 197.050 89.225 212.610 ;
        RECT 90.285 212.380 90.515 213.710 ;
        RECT 91.575 212.380 91.805 213.710 ;
        RECT 90.240 211.740 90.560 212.380 ;
        RECT 91.530 211.740 91.850 212.380 ;
        RECT 90.285 210.650 90.515 211.740 ;
        RECT 91.575 210.650 91.805 211.740 ;
        RECT 90.240 210.010 90.560 210.650 ;
        RECT 91.530 210.010 91.850 210.650 ;
        RECT 90.285 208.300 90.515 210.010 ;
        RECT 91.575 208.300 91.805 210.010 ;
        RECT 90.285 208.070 91.805 208.300 ;
        RECT 89.380 207.530 90.130 207.850 ;
        RECT 90.285 207.760 90.515 208.070 ;
        RECT 91.575 207.760 91.805 208.070 ;
        RECT 90.285 207.530 91.805 207.760 ;
        RECT 90.285 202.120 90.515 207.530 ;
        RECT 91.575 202.120 91.805 207.530 ;
        RECT 89.380 201.800 90.130 202.120 ;
        RECT 90.285 201.890 91.805 202.120 ;
        RECT 90.285 201.580 90.515 201.890 ;
        RECT 91.575 201.580 91.805 201.890 ;
        RECT 90.285 201.350 91.805 201.580 ;
        RECT 90.285 199.475 90.515 201.350 ;
        RECT 91.575 199.475 91.805 201.350 ;
        RECT 90.240 198.835 90.560 199.475 ;
        RECT 91.530 198.835 91.850 199.475 ;
        RECT 90.285 197.840 90.515 198.835 ;
        RECT 91.575 197.840 91.805 198.835 ;
        RECT 90.240 197.200 90.560 197.840 ;
        RECT 91.530 197.200 91.850 197.840 ;
        RECT 88.955 196.410 89.275 197.050 ;
        RECT 90.285 195.940 90.515 197.200 ;
        RECT 91.575 195.940 91.805 197.200 ;
        RECT 90.240 195.805 91.805 195.940 ;
        RECT 82.500 195.445 82.820 195.805 ;
        RECT 85.080 195.445 85.400 195.805 ;
        RECT 87.660 195.445 87.980 195.805 ;
        RECT 90.240 195.710 91.845 195.805 ;
        RECT 90.240 195.445 90.560 195.710 ;
        RECT 91.525 195.445 91.845 195.710 ;
        RECT 81.795 195.170 91.845 195.445 ;
        RECT 92.095 195.220 92.415 213.870 ;
        RECT 92.695 213.710 94.215 213.870 ;
        RECT 92.695 213.505 92.920 213.710 ;
        RECT 92.695 212.380 92.925 213.505 ;
        RECT 93.985 212.380 94.215 213.710 ;
        RECT 96.565 212.380 96.795 213.870 ;
        RECT 99.145 212.380 99.375 213.870 ;
        RECT 101.725 213.710 103.245 213.870 ;
        RECT 101.725 212.380 101.955 213.710 ;
        RECT 103.015 212.380 103.245 213.710 ;
        RECT 103.510 212.380 103.875 213.870 ;
        RECT 104.980 213.710 105.730 213.940 ;
        RECT 106.270 213.710 107.020 213.940 ;
        RECT 107.560 213.710 108.310 213.940 ;
        RECT 108.850 213.710 109.600 213.940 ;
        RECT 110.140 213.710 110.890 213.940 ;
        RECT 111.430 213.710 112.180 213.940 ;
        RECT 112.720 213.710 113.470 213.940 ;
        RECT 114.010 213.710 114.760 213.940 ;
        RECT 115.300 213.710 116.050 213.940 ;
        RECT 116.590 213.710 117.340 213.940 ;
        RECT 117.880 213.710 118.630 213.940 ;
        RECT 119.170 213.710 119.920 213.940 ;
        RECT 120.460 213.710 121.210 213.940 ;
        RECT 121.750 213.710 122.500 213.940 ;
        RECT 123.040 213.710 123.790 213.940 ;
        RECT 106.280 213.685 107.010 213.710 ;
        RECT 107.570 213.685 108.300 213.710 ;
        RECT 108.860 213.685 109.590 213.710 ;
        RECT 110.150 213.685 110.880 213.710 ;
        RECT 111.440 213.685 112.170 213.710 ;
        RECT 112.730 213.685 113.460 213.710 ;
        RECT 114.020 213.685 114.750 213.710 ;
        RECT 115.310 213.685 116.040 213.710 ;
        RECT 116.600 213.685 117.330 213.710 ;
        RECT 117.890 213.685 118.620 213.710 ;
        RECT 119.180 213.685 119.910 213.710 ;
        RECT 120.470 213.685 121.200 213.710 ;
        RECT 121.760 213.685 122.490 213.710 ;
        RECT 123.050 213.685 123.780 213.710 ;
        RECT 124.340 213.685 125.070 213.970 ;
        RECT 125.630 213.940 126.360 213.970 ;
        RECT 126.920 213.940 127.650 213.970 ;
        RECT 128.210 213.940 128.940 213.970 ;
        RECT 129.500 213.940 130.230 213.970 ;
        RECT 130.790 213.940 131.520 213.970 ;
        RECT 125.630 213.710 126.750 213.940 ;
        RECT 126.920 213.710 128.040 213.940 ;
        RECT 128.210 213.710 129.330 213.940 ;
        RECT 129.500 213.710 130.620 213.940 ;
        RECT 130.790 213.710 131.910 213.940 ;
        RECT 132.450 213.710 133.200 213.940 ;
        RECT 133.740 213.710 134.490 213.940 ;
        RECT 135.030 213.710 135.780 213.940 ;
        RECT 136.320 213.710 137.070 213.940 ;
        RECT 137.610 213.710 138.360 213.940 ;
        RECT 138.900 213.710 139.650 213.940 ;
        RECT 140.190 213.710 140.940 213.940 ;
        RECT 141.480 213.710 142.230 213.940 ;
        RECT 142.770 213.710 143.520 213.940 ;
        RECT 125.630 213.685 126.360 213.710 ;
        RECT 126.920 213.685 127.650 213.710 ;
        RECT 128.210 213.685 128.940 213.710 ;
        RECT 129.500 213.685 130.230 213.710 ;
        RECT 130.790 213.685 131.520 213.710 ;
        RECT 104.595 212.380 104.825 213.505 ;
        RECT 92.650 211.740 92.970 212.380 ;
        RECT 93.940 211.740 94.260 212.380 ;
        RECT 96.520 211.740 96.840 212.380 ;
        RECT 99.100 211.740 99.420 212.380 ;
        RECT 101.680 211.740 102.000 212.380 ;
        RECT 102.970 211.740 103.290 212.380 ;
        RECT 103.510 211.740 104.080 212.380 ;
        RECT 104.550 211.740 104.870 212.380 ;
        RECT 92.695 210.650 92.925 211.740 ;
        RECT 93.985 210.650 94.215 211.740 ;
        RECT 96.565 210.650 96.795 211.740 ;
        RECT 92.650 210.010 92.970 210.650 ;
        RECT 93.940 210.010 94.260 210.650 ;
        RECT 96.520 210.010 96.840 210.650 ;
        RECT 92.695 208.300 92.925 210.010 ;
        RECT 93.985 208.300 94.215 210.010 ;
        RECT 95.230 208.535 95.550 209.870 ;
        RECT 92.695 208.070 94.215 208.300 ;
        RECT 92.695 207.760 92.925 208.070 ;
        RECT 93.985 207.760 94.215 208.070 ;
        RECT 94.425 207.760 95.065 207.850 ;
        RECT 92.695 207.530 94.215 207.760 ;
        RECT 94.370 207.530 95.120 207.760 ;
        RECT 92.695 202.120 92.925 207.530 ;
        RECT 93.985 202.120 94.215 207.530 ;
        RECT 92.695 201.890 94.215 202.120 ;
        RECT 94.370 201.890 95.120 202.120 ;
        RECT 92.695 201.140 92.925 201.890 ;
        RECT 92.650 199.630 92.970 200.910 ;
        RECT 82.500 195.165 82.820 195.170 ;
        RECT 85.080 195.165 85.400 195.170 ;
        RECT 87.660 195.165 87.980 195.170 ;
        RECT 90.240 195.165 90.560 195.170 ;
        RECT 91.525 195.165 91.845 195.170 ;
        RECT 81.630 192.620 82.380 192.940 ;
        RECT 82.920 192.620 83.670 192.940 ;
        RECT 84.210 192.620 84.960 192.940 ;
        RECT 85.500 192.620 86.250 192.940 ;
        RECT 86.790 192.620 87.540 192.940 ;
        RECT 91.835 192.850 92.475 192.940 ;
        RECT 91.780 192.620 92.530 192.850 ;
        RECT 70.180 191.570 70.930 191.800 ;
        RECT 71.085 191.570 72.605 191.800 ;
        RECT 70.235 191.480 70.875 191.570 ;
        RECT 75.180 191.480 75.930 191.800 ;
        RECT 76.085 190.935 76.315 192.460 ;
        RECT 76.470 191.480 77.220 191.800 ;
        RECT 77.760 191.480 78.510 191.800 ;
        RECT 78.665 190.935 78.895 192.460 ;
        RECT 81.245 191.960 81.490 192.460 ;
        RECT 79.050 191.480 79.800 191.800 ;
        RECT 80.340 191.480 81.090 191.800 ;
        RECT 67.170 190.285 67.490 190.925 ;
        RECT 69.750 190.295 70.070 190.935 ;
        RECT 76.040 190.295 76.360 190.935 ;
        RECT 78.620 190.295 78.940 190.935 ;
        RECT 76.085 190.285 76.315 190.295 ;
        RECT 78.665 190.285 78.895 190.295 ;
        RECT 64.750 189.285 65.070 189.290 ;
        RECT 72.615 189.285 72.935 189.290 ;
        RECT 74.745 189.285 75.065 189.290 ;
        RECT 77.325 189.285 77.645 189.290 ;
        RECT 78.380 189.285 78.925 189.290 ;
        RECT 64.750 188.945 79.495 189.285 ;
        RECT 64.750 182.595 65.070 188.945 ;
        RECT 67.885 188.645 68.205 188.945 ;
        RECT 72.380 188.650 73.170 188.945 ;
        RECT 74.745 188.650 75.065 188.945 ;
        RECT 77.325 188.650 77.645 188.945 ;
        RECT 78.605 188.650 78.925 188.945 ;
        RECT 65.370 187.960 66.890 188.190 ;
        RECT 65.370 187.050 65.600 187.960 ;
        RECT 66.660 187.050 66.890 187.960 ;
        RECT 65.370 186.820 66.890 187.050 ;
        RECT 65.370 186.510 65.600 186.820 ;
        RECT 66.660 186.510 66.890 186.820 ;
        RECT 65.370 186.280 66.890 186.510 ;
        RECT 67.045 186.280 67.795 186.745 ;
        RECT 65.370 185.370 65.600 186.280 ;
        RECT 66.660 185.370 66.890 186.280 ;
        RECT 65.370 185.140 66.890 185.370 ;
        RECT 65.370 184.830 65.600 185.140 ;
        RECT 66.660 184.830 66.890 185.140 ;
        RECT 67.045 185.005 67.795 185.370 ;
        RECT 65.370 184.600 66.890 184.830 ;
        RECT 65.370 183.690 65.600 184.600 ;
        RECT 66.660 183.690 66.890 184.600 ;
        RECT 65.370 183.460 66.890 183.690 ;
        RECT 66.660 181.050 66.890 183.460 ;
        RECT 67.950 182.830 68.180 188.645 ;
        RECT 71.035 187.635 71.355 188.275 ;
        RECT 68.335 186.280 69.480 186.745 ;
        RECT 69.240 185.370 69.480 186.280 ;
        RECT 68.335 185.005 69.480 185.370 ;
        RECT 67.770 182.540 68.360 182.830 ;
        RECT 66.495 180.270 67.250 181.050 ;
        RECT 66.495 179.810 67.245 180.130 ;
        RECT 66.495 178.820 66.740 179.810 ;
        RECT 66.990 178.820 67.245 179.810 ;
        RECT 66.495 178.500 67.245 178.820 ;
        RECT 67.395 180.100 67.715 182.070 ;
        RECT 68.690 180.100 68.920 182.020 ;
        RECT 67.395 179.780 68.920 180.100 ;
        RECT 67.395 178.850 67.715 179.780 ;
        RECT 68.690 178.850 68.920 179.780 ;
        RECT 67.395 178.530 68.920 178.850 ;
        RECT 66.495 177.580 67.245 178.360 ;
        RECT 66.735 175.350 67.055 177.580 ;
        RECT 67.395 176.510 67.715 178.530 ;
        RECT 67.395 176.340 67.645 176.510 ;
        RECT 68.690 176.340 68.920 178.530 ;
        RECT 69.240 176.515 69.480 185.005 ;
        RECT 71.090 182.740 71.320 187.635 ;
        RECT 71.540 186.725 72.180 186.745 ;
        RECT 71.475 186.495 72.225 186.725 ;
        RECT 71.540 186.425 72.180 186.495 ;
        RECT 71.475 185.005 72.225 185.325 ;
        RECT 72.380 182.845 72.610 188.650 ;
        RECT 72.940 188.285 73.170 188.650 ;
        RECT 74.790 188.410 75.020 188.650 ;
        RECT 77.370 188.410 77.600 188.650 ;
        RECT 78.660 188.410 78.890 188.650 ;
        RECT 74.790 188.285 78.890 188.410 ;
        RECT 72.940 188.180 78.890 188.285 ;
        RECT 72.940 188.055 75.020 188.180 ;
        RECT 72.940 187.180 73.170 188.055 ;
        RECT 74.230 187.180 74.460 188.055 ;
        RECT 74.790 187.180 75.020 188.055 ;
        RECT 76.080 187.180 76.310 188.180 ;
        RECT 77.370 187.180 77.600 188.180 ;
        RECT 78.660 187.180 78.890 188.180 ;
        RECT 72.940 186.915 78.890 187.180 ;
        RECT 72.940 182.845 73.170 186.915 ;
        RECT 74.230 185.670 74.640 186.170 ;
        RECT 71.035 182.100 71.355 182.740 ;
        RECT 71.795 182.100 72.115 182.740 ;
        RECT 72.380 182.555 73.170 182.845 ;
        RECT 69.685 179.960 70.325 180.080 ;
        RECT 69.635 179.730 70.385 179.960 ;
        RECT 69.635 178.680 70.385 178.910 ;
        RECT 69.700 178.560 70.340 178.680 ;
        RECT 71.830 176.515 72.060 182.100 ;
        RECT 74.410 180.030 74.640 185.670 ;
        RECT 74.790 182.890 75.020 186.915 ;
        RECT 77.370 186.640 77.600 186.915 ;
        RECT 78.660 186.640 78.890 186.915 ;
        RECT 76.470 186.410 77.210 186.640 ;
        RECT 75.375 186.040 76.310 186.205 ;
        RECT 75.370 185.615 76.310 186.040 ;
        RECT 75.370 183.845 76.010 185.615 ;
        RECT 76.720 185.410 76.950 186.410 ;
        RECT 77.370 186.405 78.890 186.640 ;
        RECT 77.370 185.415 77.600 186.405 ;
        RECT 78.660 185.415 78.890 186.405 ;
        RECT 76.470 184.630 77.210 185.410 ;
        RECT 77.370 185.180 78.890 185.415 ;
        RECT 77.370 184.875 77.600 185.180 ;
        RECT 78.660 184.875 78.890 185.180 ;
        RECT 77.370 184.640 78.890 184.875 ;
        RECT 74.790 182.540 75.125 182.890 ;
        RECT 72.270 179.960 72.910 180.030 ;
        RECT 73.555 179.960 74.640 180.030 ;
        RECT 72.215 179.730 72.965 179.960 ;
        RECT 73.505 179.730 74.640 179.960 ;
        RECT 72.270 179.710 72.910 179.730 ;
        RECT 73.555 179.710 74.640 179.730 ;
        RECT 74.410 178.950 74.640 179.710 ;
        RECT 72.265 178.910 72.905 178.950 ;
        RECT 73.560 178.910 74.640 178.950 ;
        RECT 72.215 178.680 72.965 178.910 ;
        RECT 73.505 178.680 74.640 178.910 ;
        RECT 72.265 178.630 72.905 178.680 ;
        RECT 73.560 178.630 74.640 178.680 ;
        RECT 74.410 176.515 74.640 178.630 ;
        RECT 75.370 176.345 75.585 183.845 ;
        RECT 75.775 176.345 76.010 183.845 ;
        RECT 76.470 183.710 77.210 184.490 ;
        RECT 76.720 182.780 76.950 183.710 ;
        RECT 77.370 183.640 77.600 184.640 ;
        RECT 78.660 183.640 78.890 184.640 ;
        RECT 77.370 183.405 78.890 183.640 ;
        RECT 77.370 182.825 77.600 183.405 ;
        RECT 78.660 182.825 78.890 183.405 ;
        RECT 79.175 182.825 79.495 188.945 ;
        RECT 81.250 186.660 81.490 191.960 ;
        RECT 81.630 191.480 82.380 191.800 ;
        RECT 82.920 191.480 83.670 191.800 ;
        RECT 83.825 190.935 84.055 192.460 ;
        RECT 84.210 191.480 84.960 191.800 ;
        RECT 85.500 191.480 86.250 191.800 ;
        RECT 86.405 190.935 86.635 192.460 ;
        RECT 92.685 192.415 92.925 199.630 ;
        RECT 93.985 199.475 94.215 201.890 ;
        RECT 94.425 201.800 95.065 201.890 ;
        RECT 95.275 200.910 95.505 208.535 ;
        RECT 95.715 207.760 96.355 207.850 ;
        RECT 95.660 207.530 96.410 207.760 ;
        RECT 95.660 201.890 96.410 202.120 ;
        RECT 95.715 201.800 96.355 201.890 ;
        RECT 95.230 199.630 95.550 200.910 ;
        RECT 96.565 199.475 96.795 210.010 ;
        RECT 97.005 207.760 97.645 211.495 ;
        RECT 97.855 209.815 98.085 210.095 ;
        RECT 97.810 208.535 98.130 209.815 ;
        RECT 96.950 207.530 97.700 207.760 ;
        RECT 96.950 201.890 97.700 202.120 ;
        RECT 93.940 198.835 94.260 199.475 ;
        RECT 96.520 198.835 96.840 199.475 ;
        RECT 93.985 197.840 94.215 198.835 ;
        RECT 96.565 197.840 96.795 198.835 ;
        RECT 97.005 198.010 97.645 201.890 ;
        RECT 97.855 200.915 98.085 208.535 ;
        RECT 98.295 207.760 98.935 211.495 ;
        RECT 99.145 210.650 99.375 211.740 ;
        RECT 101.725 210.650 101.955 211.740 ;
        RECT 103.015 210.650 103.245 211.740 ;
        RECT 103.510 210.650 103.875 211.740 ;
        RECT 104.595 210.650 104.825 211.740 ;
        RECT 99.100 210.010 99.420 210.650 ;
        RECT 98.240 207.530 98.990 207.760 ;
        RECT 98.240 201.890 98.990 202.120 ;
        RECT 98.295 201.790 98.935 201.890 ;
        RECT 97.810 199.630 98.130 200.915 ;
        RECT 93.940 197.200 94.260 197.840 ;
        RECT 96.520 197.200 96.840 197.840 ;
        RECT 93.985 195.805 94.215 197.200 ;
        RECT 95.265 197.050 95.495 197.100 ;
        RECT 95.230 196.410 95.550 197.050 ;
        RECT 93.935 195.165 94.255 195.805 ;
        RECT 93.125 192.850 93.765 192.940 ;
        RECT 94.415 192.850 95.055 192.940 ;
        RECT 95.265 192.850 95.495 196.410 ;
        RECT 96.565 195.800 96.795 197.200 ;
        RECT 96.515 195.160 96.835 195.800 ;
        RECT 95.705 192.850 96.345 192.940 ;
        RECT 96.995 192.850 97.635 192.940 ;
        RECT 93.070 192.620 93.820 192.850 ;
        RECT 94.360 192.620 96.400 192.850 ;
        RECT 96.940 192.620 97.690 192.850 ;
        RECT 92.685 191.960 92.915 192.415 ;
        RECT 95.265 191.800 95.495 192.620 ;
        RECT 97.845 192.430 98.085 199.630 ;
        RECT 98.295 198.650 98.930 201.790 ;
        RECT 99.145 199.475 99.375 210.010 ;
        RECT 100.435 209.815 100.665 210.120 ;
        RECT 101.680 210.010 102.000 210.650 ;
        RECT 102.970 210.010 103.290 210.650 ;
        RECT 103.510 210.010 104.100 210.650 ;
        RECT 104.550 210.010 104.870 210.650 ;
        RECT 100.390 208.535 100.710 209.815 ;
        RECT 99.585 207.760 100.225 207.850 ;
        RECT 99.530 207.530 100.280 207.760 ;
        RECT 99.530 201.890 100.280 202.120 ;
        RECT 99.585 201.800 100.225 201.890 ;
        RECT 100.435 200.910 100.665 208.535 ;
        RECT 101.725 208.300 101.955 210.010 ;
        RECT 103.015 208.300 103.245 210.010 ;
        RECT 101.725 208.070 103.245 208.300 ;
        RECT 100.875 207.760 101.515 207.850 ;
        RECT 101.725 207.760 101.955 208.070 ;
        RECT 103.015 207.760 103.245 208.070 ;
        RECT 100.820 207.530 101.570 207.760 ;
        RECT 101.725 207.530 103.245 207.760 ;
        RECT 101.725 202.120 101.955 207.530 ;
        RECT 103.015 202.120 103.245 207.530 ;
        RECT 100.820 201.890 101.570 202.120 ;
        RECT 101.725 201.890 103.245 202.120 ;
        RECT 100.875 201.800 101.515 201.890 ;
        RECT 100.390 199.630 100.710 200.910 ;
        RECT 101.725 199.475 101.955 201.890 ;
        RECT 103.015 201.185 103.245 201.890 ;
        RECT 99.100 198.835 99.420 199.475 ;
        RECT 101.670 198.835 101.990 199.475 ;
        RECT 98.290 198.010 98.930 198.650 ;
        RECT 99.145 197.840 99.375 198.835 ;
        RECT 101.725 197.840 101.955 198.835 ;
        RECT 99.100 197.200 99.420 197.840 ;
        RECT 101.670 197.200 101.990 197.840 ;
        RECT 99.145 195.800 99.375 197.200 ;
        RECT 101.725 195.805 101.955 197.200 ;
        RECT 99.100 195.160 99.420 195.800 ;
        RECT 101.670 195.165 101.990 195.805 ;
        RECT 98.285 192.850 98.925 192.940 ;
        RECT 98.230 192.620 98.980 192.850 ;
        RECT 97.845 191.960 98.075 192.430 ;
        RECT 86.790 191.480 87.540 191.800 ;
        RECT 91.780 191.570 92.530 191.800 ;
        RECT 93.070 191.570 93.820 191.800 ;
        RECT 94.360 191.570 96.400 191.800 ;
        RECT 96.940 191.570 97.690 191.800 ;
        RECT 98.230 191.570 98.980 191.800 ;
        RECT 91.835 191.480 92.475 191.570 ;
        RECT 93.125 191.480 93.765 191.570 ;
        RECT 94.415 191.480 95.055 191.570 ;
        RECT 95.705 191.480 96.345 191.570 ;
        RECT 96.995 191.480 97.635 191.570 ;
        RECT 98.285 191.480 98.925 191.570 ;
        RECT 83.780 190.295 84.100 190.935 ;
        RECT 86.360 190.295 86.680 190.935 ;
        RECT 83.825 190.285 84.055 190.295 ;
        RECT 86.405 190.285 86.635 190.295 ;
        RECT 102.130 186.830 103.190 200.915 ;
        RECT 103.510 195.805 103.875 210.010 ;
        RECT 104.595 199.475 104.825 210.010 ;
        RECT 104.550 198.835 104.870 199.475 ;
        RECT 104.595 197.840 104.825 198.835 ;
        RECT 104.550 197.200 104.870 197.840 ;
        RECT 104.595 195.805 104.825 197.200 ;
        RECT 103.510 195.165 104.080 195.805 ;
        RECT 104.550 195.165 104.870 195.805 ;
        RECT 104.595 189.290 104.825 195.165 ;
        RECT 104.550 188.650 104.870 189.290 ;
        RECT 81.205 186.020 81.525 186.660 ;
        RECT 90.940 186.020 94.870 186.660 ;
        RECT 99.140 185.865 103.190 186.830 ;
        RECT 100.785 183.020 102.465 183.025 ;
        RECT 76.205 182.140 76.525 182.780 ;
        RECT 76.670 182.140 76.990 182.780 ;
        RECT 77.265 182.535 77.855 182.825 ;
        RECT 78.495 182.535 79.495 182.825 ;
        RECT 100.385 182.660 102.465 183.020 ;
        RECT 100.380 182.625 102.465 182.660 ;
        RECT 79.175 182.510 79.495 182.535 ;
        RECT 90.420 182.620 92.300 182.625 ;
        RECT 90.420 182.375 94.340 182.620 ;
        RECT 76.260 179.070 76.490 182.140 ;
        RECT 76.705 179.710 77.345 180.030 ;
        RECT 67.395 176.020 67.715 176.340 ;
        RECT 68.645 176.020 68.965 176.340 ;
        RECT 75.370 176.025 76.010 176.345 ;
        RECT 76.230 176.345 76.490 179.070 ;
        RECT 76.700 178.630 77.340 178.950 ;
        RECT 90.420 178.760 90.740 182.375 ;
        RECT 92.235 182.370 94.340 182.375 ;
        RECT 100.360 182.370 102.465 182.625 ;
        RECT 100.385 181.740 102.465 182.370 ;
        RECT 90.420 178.510 94.070 178.760 ;
        RECT 76.230 176.025 76.550 176.345 ;
        RECT 68.700 175.350 69.020 175.410 ;
        RECT 74.865 175.350 75.185 175.530 ;
        RECT 64.955 175.100 67.060 175.350 ;
        RECT 68.700 175.100 70.805 175.350 ;
        RECT 73.080 175.100 75.185 175.350 ;
        RECT 76.825 175.350 77.145 175.530 ;
        RECT 76.825 175.100 78.930 175.350 ;
        RECT 68.700 175.090 69.020 175.100 ;
        RECT 104.595 167.505 104.825 188.650 ;
        RECT 105.885 167.505 106.115 213.505 ;
        RECT 107.175 167.505 107.405 213.505 ;
        RECT 108.465 167.505 108.695 213.505 ;
        RECT 109.755 167.505 109.985 213.505 ;
        RECT 111.045 167.505 111.275 213.505 ;
        RECT 112.335 167.505 112.565 213.505 ;
        RECT 113.625 167.505 113.855 213.505 ;
        RECT 114.915 167.505 115.145 213.505 ;
        RECT 116.205 167.505 116.435 213.505 ;
        RECT 117.495 167.505 117.725 213.505 ;
        RECT 118.785 167.505 119.015 213.505 ;
        RECT 120.075 167.505 120.305 213.505 ;
        RECT 121.365 167.505 121.595 213.505 ;
        RECT 122.655 167.505 122.885 213.505 ;
        RECT 123.945 167.505 124.175 213.505 ;
        RECT 125.615 167.505 125.845 213.505 ;
        RECT 126.905 167.505 127.135 213.505 ;
        RECT 128.195 167.505 128.425 213.505 ;
        RECT 129.485 167.505 129.715 213.505 ;
        RECT 130.775 167.505 131.005 213.505 ;
        RECT 132.065 167.505 132.295 213.505 ;
        RECT 133.355 167.505 133.585 213.505 ;
        RECT 134.645 167.505 134.875 213.505 ;
        RECT 135.935 167.505 136.165 213.505 ;
        RECT 137.225 167.505 137.455 213.505 ;
        RECT 138.515 167.505 138.745 213.505 ;
        RECT 139.805 167.505 140.035 213.505 ;
        RECT 141.095 167.505 141.325 213.505 ;
        RECT 142.385 167.505 142.615 213.505 ;
        RECT 143.675 167.505 143.905 213.505 ;
        RECT 104.980 167.070 105.730 167.300 ;
        RECT 106.270 167.070 107.020 167.300 ;
        RECT 107.560 167.070 108.310 167.300 ;
        RECT 108.850 167.070 109.600 167.300 ;
        RECT 110.140 167.070 110.890 167.300 ;
        RECT 111.430 167.070 112.180 167.300 ;
        RECT 112.720 167.070 113.470 167.300 ;
        RECT 114.010 167.070 114.760 167.300 ;
        RECT 115.300 167.070 116.050 167.300 ;
        RECT 116.590 167.070 117.340 167.300 ;
        RECT 117.880 167.070 118.630 167.300 ;
        RECT 119.170 167.070 119.920 167.300 ;
        RECT 120.460 167.070 121.210 167.300 ;
        RECT 121.750 167.070 122.500 167.300 ;
        RECT 123.040 167.070 123.790 167.300 ;
        RECT 126.000 167.070 126.750 167.300 ;
        RECT 127.290 167.070 128.040 167.300 ;
        RECT 128.580 167.070 129.330 167.300 ;
        RECT 129.870 167.070 130.620 167.300 ;
        RECT 131.160 167.070 131.910 167.300 ;
        RECT 132.450 167.070 133.200 167.300 ;
        RECT 133.740 167.070 134.490 167.300 ;
        RECT 135.030 167.070 135.780 167.300 ;
        RECT 136.320 167.070 137.070 167.300 ;
        RECT 137.610 167.070 138.360 167.300 ;
        RECT 138.900 167.070 139.650 167.300 ;
        RECT 140.190 167.070 140.940 167.300 ;
        RECT 141.480 167.070 142.230 167.300 ;
        RECT 142.770 167.070 143.520 167.300 ;
        RECT 106.280 155.545 107.010 155.830 ;
        RECT 107.570 155.545 108.300 155.830 ;
        RECT 108.860 155.545 109.590 155.830 ;
        RECT 110.150 155.545 110.880 155.830 ;
        RECT 111.440 155.545 112.170 155.830 ;
        RECT 112.730 155.545 113.460 155.830 ;
        RECT 114.020 155.545 114.750 155.830 ;
        RECT 115.310 155.545 116.040 155.830 ;
        RECT 116.600 155.545 117.330 155.830 ;
        RECT 117.890 155.545 118.620 155.830 ;
        RECT 119.180 155.545 119.910 155.830 ;
        RECT 120.470 155.545 121.200 155.830 ;
        RECT 121.760 155.545 122.490 155.830 ;
        RECT 123.050 155.545 123.780 155.830 ;
        RECT 124.340 155.545 125.070 155.830 ;
        RECT 125.630 155.545 126.360 155.830 ;
        RECT 126.920 155.545 127.650 155.830 ;
        RECT 128.210 155.545 128.940 155.830 ;
        RECT 129.500 155.545 130.230 155.830 ;
        RECT 130.790 155.545 131.520 155.830 ;
        RECT 104.425 155.015 133.375 155.290 ;
        RECT 63.175 108.705 63.495 108.710 ;
        RECT 63.175 108.075 103.035 108.705 ;
        RECT 103.635 108.425 132.485 108.655 ;
        RECT 105.440 108.145 106.170 108.175 ;
        RECT 106.730 108.145 107.460 108.175 ;
        RECT 108.020 108.145 108.750 108.175 ;
        RECT 109.310 108.145 110.040 108.175 ;
        RECT 110.600 108.145 111.330 108.175 ;
        RECT 111.890 108.145 112.620 108.175 ;
        RECT 113.180 108.145 113.910 108.175 ;
        RECT 114.470 108.145 115.200 108.175 ;
        RECT 115.760 108.145 116.490 108.175 ;
        RECT 117.050 108.145 117.780 108.175 ;
        RECT 118.340 108.145 119.070 108.175 ;
        RECT 119.630 108.145 120.360 108.175 ;
        RECT 120.920 108.145 121.650 108.175 ;
        RECT 122.210 108.145 122.940 108.175 ;
        RECT 63.175 107.915 67.510 108.075 ;
        RECT 68.050 107.915 72.380 108.075 ;
        RECT 63.175 102.505 63.495 107.915 ;
        RECT 63.795 102.505 64.025 107.915 ;
        RECT 65.085 102.505 65.315 107.915 ;
        RECT 66.375 106.585 66.605 107.915 ;
        RECT 68.955 106.585 69.185 107.915 ;
        RECT 66.330 105.945 66.650 106.585 ;
        RECT 68.910 105.945 69.230 106.585 ;
        RECT 66.375 104.855 66.605 105.945 ;
        RECT 68.955 104.855 69.185 105.945 ;
        RECT 66.330 104.215 66.650 104.855 ;
        RECT 68.910 104.215 69.230 104.855 ;
        RECT 66.375 102.505 66.605 104.215 ;
        RECT 67.620 103.350 67.940 103.990 ;
        RECT 63.175 102.275 67.510 102.505 ;
        RECT 63.175 89.340 63.495 102.275 ;
        RECT 63.795 102.060 65.500 102.065 ;
        RECT 63.795 101.740 66.225 102.060 ;
        RECT 63.795 96.330 64.025 101.740 ;
        RECT 64.180 101.735 64.930 101.740 ;
        RECT 65.470 101.735 66.220 101.740 ;
        RECT 65.085 97.220 65.315 101.530 ;
        RECT 65.085 96.530 65.320 97.220 ;
        RECT 65.090 96.330 65.320 96.530 ;
        RECT 63.795 96.010 66.225 96.330 ;
        RECT 63.795 96.005 65.320 96.010 ;
        RECT 63.795 95.555 64.930 95.785 ;
        RECT 63.795 90.145 64.025 95.555 ;
        RECT 63.795 89.915 64.930 90.145 ;
        RECT 65.090 87.055 65.320 96.005 ;
        RECT 66.375 93.680 66.605 102.275 ;
        RECT 66.765 101.965 67.515 102.060 ;
        RECT 66.760 101.740 67.515 101.965 ;
        RECT 66.760 101.735 67.510 101.740 ;
        RECT 66.765 96.325 67.515 96.330 ;
        RECT 66.760 96.095 67.515 96.325 ;
        RECT 66.765 96.010 67.515 96.095 ;
        RECT 66.815 96.005 67.455 96.010 ;
        RECT 67.665 94.725 67.895 103.350 ;
        RECT 68.955 102.505 69.185 104.215 ;
        RECT 70.245 102.505 70.475 107.915 ;
        RECT 71.535 102.505 71.765 107.915 ;
        RECT 72.060 102.505 72.380 107.915 ;
        RECT 72.675 107.915 74.245 108.075 ;
        RECT 76.500 108.035 76.820 108.075 ;
        RECT 79.080 108.035 79.400 108.075 ;
        RECT 81.660 108.035 81.980 108.075 ;
        RECT 84.240 108.035 84.560 108.075 ;
        RECT 86.820 108.035 87.140 108.075 ;
        RECT 89.400 108.035 91.005 108.075 ;
        RECT 72.675 106.585 72.905 107.915 ;
        RECT 73.965 106.585 74.205 107.915 ;
        RECT 76.545 106.585 76.775 108.035 ;
        RECT 77.790 106.815 78.110 107.455 ;
        RECT 72.630 105.945 72.950 106.585 ;
        RECT 73.920 105.945 74.240 106.585 ;
        RECT 76.500 105.945 76.820 106.585 ;
        RECT 72.675 104.855 72.905 105.945 ;
        RECT 73.965 104.855 74.205 105.945 ;
        RECT 75.210 105.060 75.530 105.700 ;
        RECT 72.630 104.215 72.950 104.855 ;
        RECT 73.920 104.215 74.240 104.855 ;
        RECT 68.050 102.275 72.380 102.505 ;
        RECT 68.055 101.965 68.805 102.060 ;
        RECT 68.050 101.740 68.805 101.965 ;
        RECT 68.050 101.735 68.800 101.740 ;
        RECT 68.055 96.325 68.805 96.330 ;
        RECT 68.050 96.095 68.805 96.325 ;
        RECT 68.055 96.010 68.805 96.095 ;
        RECT 68.105 96.005 68.745 96.010 ;
        RECT 67.620 94.085 67.940 94.725 ;
        RECT 66.330 93.040 66.650 93.680 ;
        RECT 66.375 92.045 66.605 93.040 ;
        RECT 66.330 91.405 66.650 92.045 ;
        RECT 66.375 89.435 66.605 91.405 ;
        RECT 65.525 87.055 66.165 87.145 ;
        RECT 63.795 86.825 65.320 87.055 ;
        RECT 65.470 86.825 66.220 87.055 ;
        RECT 63.795 86.005 64.025 86.825 ;
        RECT 65.085 86.005 65.320 86.825 ;
        RECT 63.795 85.775 65.320 86.005 ;
        RECT 65.470 85.775 66.220 86.005 ;
        RECT 65.525 85.685 66.165 85.775 ;
        RECT 66.375 85.130 66.605 86.665 ;
        RECT 67.665 86.165 67.895 94.085 ;
        RECT 68.955 93.680 69.185 102.275 ;
        RECT 70.070 102.060 71.765 102.065 ;
        RECT 69.345 101.965 71.765 102.060 ;
        RECT 69.340 101.740 71.765 101.965 ;
        RECT 69.340 101.735 70.090 101.740 ;
        RECT 70.630 101.735 71.380 101.740 ;
        RECT 70.245 97.210 70.475 101.530 ;
        RECT 70.245 96.530 70.480 97.210 ;
        RECT 70.250 96.335 70.480 96.530 ;
        RECT 71.535 96.335 71.765 101.740 ;
        RECT 70.070 96.330 71.765 96.335 ;
        RECT 69.345 96.325 71.765 96.330 ;
        RECT 69.340 96.095 71.765 96.325 ;
        RECT 69.345 96.010 71.765 96.095 ;
        RECT 69.395 96.005 70.035 96.010 ;
        RECT 68.905 93.360 69.225 93.680 ;
        RECT 68.910 93.040 69.230 93.360 ;
        RECT 68.955 92.045 69.185 93.040 ;
        RECT 68.910 91.405 69.230 92.045 ;
        RECT 68.955 89.435 69.185 91.405 ;
        RECT 69.395 87.055 70.035 87.145 ;
        RECT 70.250 87.055 70.480 96.010 ;
        RECT 70.630 95.555 71.765 95.785 ;
        RECT 71.535 90.145 71.765 95.555 ;
        RECT 70.630 89.915 71.765 90.145 ;
        RECT 71.535 89.910 71.765 89.915 ;
        RECT 72.060 89.660 72.380 102.275 ;
        RECT 72.675 102.505 72.905 104.215 ;
        RECT 73.965 102.505 74.205 104.215 ;
        RECT 74.410 103.985 74.730 103.990 ;
        RECT 74.410 103.350 75.050 103.985 ;
        RECT 74.730 103.345 75.050 103.350 ;
        RECT 72.675 102.275 74.205 102.505 ;
        RECT 72.675 101.965 72.905 102.275 ;
        RECT 73.965 101.965 74.205 102.275 ;
        RECT 72.675 101.735 74.205 101.965 ;
        RECT 74.350 101.735 75.100 102.055 ;
        RECT 72.675 96.325 72.905 101.735 ;
        RECT 73.965 101.365 74.205 101.735 ;
        RECT 73.965 96.325 74.195 101.365 ;
        RECT 72.675 96.095 74.195 96.325 ;
        RECT 72.675 95.785 72.905 96.095 ;
        RECT 73.965 95.785 74.195 96.095 ;
        RECT 74.350 96.005 75.100 96.325 ;
        RECT 72.675 95.555 74.195 95.785 ;
        RECT 72.675 93.680 72.905 95.555 ;
        RECT 73.965 93.680 74.195 95.555 ;
        RECT 72.630 93.040 72.950 93.680 ;
        RECT 73.920 93.040 74.240 93.680 ;
        RECT 72.675 92.045 72.905 93.040 ;
        RECT 73.965 92.045 74.195 93.040 ;
        RECT 75.255 92.855 75.485 105.060 ;
        RECT 76.545 104.855 76.775 105.945 ;
        RECT 76.500 104.215 76.820 104.855 ;
        RECT 75.640 101.735 76.390 102.055 ;
        RECT 75.640 96.005 76.390 96.325 ;
        RECT 76.545 93.680 76.775 104.215 ;
        RECT 76.930 101.735 77.680 102.055 ;
        RECT 76.930 96.005 77.680 96.325 ;
        RECT 76.500 93.040 76.820 93.680 ;
        RECT 75.210 92.215 75.530 92.855 ;
        RECT 76.545 92.045 76.775 93.040 ;
        RECT 72.630 91.405 72.950 92.045 ;
        RECT 73.920 91.405 74.240 92.045 ;
        RECT 76.500 91.405 76.820 92.045 ;
        RECT 72.675 90.145 72.905 91.405 ;
        RECT 73.965 90.145 74.195 91.405 ;
        RECT 72.675 90.010 74.240 90.145 ;
        RECT 76.545 90.010 76.775 91.405 ;
        RECT 77.835 91.255 78.065 106.815 ;
        RECT 79.125 106.585 79.355 108.035 ;
        RECT 81.705 106.590 81.935 108.035 ;
        RECT 82.950 106.815 83.270 107.455 ;
        RECT 79.075 105.945 79.395 106.585 ;
        RECT 81.660 105.950 81.980 106.590 ;
        RECT 79.125 104.855 79.355 105.945 ;
        RECT 80.370 105.060 80.690 105.700 ;
        RECT 79.080 104.215 79.400 104.855 ;
        RECT 78.220 101.735 78.970 102.055 ;
        RECT 78.220 96.005 78.970 96.325 ;
        RECT 79.125 93.680 79.355 104.215 ;
        RECT 79.510 101.735 80.260 102.055 ;
        RECT 80.420 101.530 80.650 105.060 ;
        RECT 81.705 104.855 81.935 105.950 ;
        RECT 81.660 104.215 81.980 104.855 ;
        RECT 80.800 101.735 81.550 102.055 ;
        RECT 80.415 96.530 80.650 101.530 ;
        RECT 79.510 96.005 80.260 96.325 ;
        RECT 79.080 93.040 79.400 93.680 ;
        RECT 79.125 92.045 79.355 93.040 ;
        RECT 80.420 92.855 80.650 96.530 ;
        RECT 80.800 96.005 81.550 96.325 ;
        RECT 81.705 93.680 81.935 104.215 ;
        RECT 82.090 101.735 82.840 102.055 ;
        RECT 82.090 96.005 82.840 96.325 ;
        RECT 81.660 93.040 81.980 93.680 ;
        RECT 80.370 92.215 80.690 92.855 ;
        RECT 79.080 91.405 79.400 92.045 ;
        RECT 77.790 90.615 78.110 91.255 ;
        RECT 79.125 90.010 79.355 91.405 ;
        RECT 72.630 89.915 74.240 90.010 ;
        RECT 72.630 89.660 72.950 89.915 ;
        RECT 73.920 89.660 74.240 89.915 ;
        RECT 76.500 89.660 76.820 90.010 ;
        RECT 79.080 89.660 79.400 90.010 ;
        RECT 70.800 89.390 79.975 89.660 ;
        RECT 72.630 89.370 72.950 89.390 ;
        RECT 73.920 89.370 74.240 89.390 ;
        RECT 76.500 89.370 76.820 89.390 ;
        RECT 79.080 89.370 79.400 89.390 ;
        RECT 69.340 86.825 70.090 87.055 ;
        RECT 70.250 86.825 71.765 87.055 ;
        RECT 74.340 86.825 75.090 87.145 ;
        RECT 75.630 86.825 76.380 87.145 ;
        RECT 76.920 86.825 77.670 87.145 ;
        RECT 78.210 86.825 78.960 87.145 ;
        RECT 79.500 86.825 80.250 87.145 ;
        RECT 70.250 86.665 70.480 86.825 ;
        RECT 68.955 85.140 69.185 86.665 ;
        RECT 70.245 86.650 70.480 86.665 ;
        RECT 70.245 86.005 70.475 86.650 ;
        RECT 71.535 86.005 71.765 86.825 ;
        RECT 80.420 86.665 80.650 92.215 ;
        RECT 81.705 92.045 81.935 93.040 ;
        RECT 81.660 91.405 81.980 92.045 ;
        RECT 81.705 90.010 81.935 91.405 ;
        RECT 82.995 91.255 83.225 106.815 ;
        RECT 84.285 106.585 84.515 108.035 ;
        RECT 86.865 106.585 87.095 108.035 ;
        RECT 89.400 107.915 90.965 108.035 ;
        RECT 88.110 106.815 88.430 107.455 ;
        RECT 84.240 105.945 84.560 106.585 ;
        RECT 86.820 105.945 87.140 106.585 ;
        RECT 84.285 104.855 84.515 105.945 ;
        RECT 85.530 105.060 85.850 105.700 ;
        RECT 84.240 104.215 84.560 104.855 ;
        RECT 83.380 101.735 84.130 102.055 ;
        RECT 83.380 96.005 84.130 96.325 ;
        RECT 84.285 93.680 84.515 104.215 ;
        RECT 84.670 101.735 85.420 102.055 ;
        RECT 84.670 96.005 85.420 96.325 ;
        RECT 84.240 93.040 84.560 93.680 ;
        RECT 84.285 92.045 84.515 93.040 ;
        RECT 85.575 92.855 85.805 105.060 ;
        RECT 86.865 104.855 87.095 105.945 ;
        RECT 86.820 104.215 87.140 104.855 ;
        RECT 85.960 101.735 86.710 102.055 ;
        RECT 85.960 96.005 86.710 96.325 ;
        RECT 86.865 93.680 87.095 104.215 ;
        RECT 87.250 101.735 88.000 102.055 ;
        RECT 87.250 96.005 88.000 96.325 ;
        RECT 86.820 93.040 87.140 93.680 ;
        RECT 85.530 92.215 85.850 92.855 ;
        RECT 86.865 92.045 87.095 93.040 ;
        RECT 84.240 91.405 84.560 92.045 ;
        RECT 86.820 91.405 87.140 92.045 ;
        RECT 82.950 90.615 83.270 91.255 ;
        RECT 84.285 90.010 84.515 91.405 ;
        RECT 86.865 90.010 87.095 91.405 ;
        RECT 88.155 91.255 88.385 106.815 ;
        RECT 89.445 106.585 89.675 107.915 ;
        RECT 90.735 106.585 90.965 107.915 ;
        RECT 89.400 105.945 89.720 106.585 ;
        RECT 90.690 105.945 91.010 106.585 ;
        RECT 89.445 104.855 89.675 105.945 ;
        RECT 90.735 104.855 90.965 105.945 ;
        RECT 89.400 104.215 89.720 104.855 ;
        RECT 90.690 104.215 91.010 104.855 ;
        RECT 89.445 102.505 89.675 104.215 ;
        RECT 90.735 102.505 90.965 104.215 ;
        RECT 89.445 102.275 90.965 102.505 ;
        RECT 88.540 101.735 89.290 102.055 ;
        RECT 89.445 101.965 89.675 102.275 ;
        RECT 90.735 101.965 90.965 102.275 ;
        RECT 89.445 101.735 90.965 101.965 ;
        RECT 89.445 96.325 89.675 101.735 ;
        RECT 90.735 96.325 90.965 101.735 ;
        RECT 88.540 96.005 89.290 96.325 ;
        RECT 89.445 96.095 90.965 96.325 ;
        RECT 89.445 95.785 89.675 96.095 ;
        RECT 90.735 95.785 90.965 96.095 ;
        RECT 89.445 95.555 90.965 95.785 ;
        RECT 89.445 93.680 89.675 95.555 ;
        RECT 90.735 93.680 90.965 95.555 ;
        RECT 89.400 93.040 89.720 93.680 ;
        RECT 90.690 93.040 91.010 93.680 ;
        RECT 89.445 92.045 89.675 93.040 ;
        RECT 90.735 92.045 90.965 93.040 ;
        RECT 89.400 91.405 89.720 92.045 ;
        RECT 90.690 91.405 91.010 92.045 ;
        RECT 88.115 90.615 88.435 91.255 ;
        RECT 89.445 90.145 89.675 91.405 ;
        RECT 90.735 90.145 90.965 91.405 ;
        RECT 89.400 90.010 90.965 90.145 ;
        RECT 81.660 89.650 81.980 90.010 ;
        RECT 84.240 89.650 84.560 90.010 ;
        RECT 86.820 89.650 87.140 90.010 ;
        RECT 89.400 89.915 91.005 90.010 ;
        RECT 89.400 89.650 89.720 89.915 ;
        RECT 90.685 89.650 91.005 89.915 ;
        RECT 80.955 89.375 91.005 89.650 ;
        RECT 91.255 89.425 91.575 108.075 ;
        RECT 91.855 107.915 93.375 108.075 ;
        RECT 91.855 107.710 92.080 107.915 ;
        RECT 91.855 106.585 92.085 107.710 ;
        RECT 93.145 106.585 93.375 107.915 ;
        RECT 95.725 106.585 95.955 108.075 ;
        RECT 98.305 106.585 98.535 108.075 ;
        RECT 100.885 107.915 102.405 108.075 ;
        RECT 100.885 106.585 101.115 107.915 ;
        RECT 102.175 106.585 102.405 107.915 ;
        RECT 102.670 106.585 103.035 108.075 ;
        RECT 104.140 107.915 104.890 108.145 ;
        RECT 105.430 107.915 106.180 108.145 ;
        RECT 106.720 107.915 107.470 108.145 ;
        RECT 108.010 107.915 108.760 108.145 ;
        RECT 109.300 107.915 110.050 108.145 ;
        RECT 110.590 107.915 111.340 108.145 ;
        RECT 111.880 107.915 112.630 108.145 ;
        RECT 113.170 107.915 113.920 108.145 ;
        RECT 114.460 107.915 115.210 108.145 ;
        RECT 115.750 107.915 116.500 108.145 ;
        RECT 117.040 107.915 117.790 108.145 ;
        RECT 118.330 107.915 119.080 108.145 ;
        RECT 119.620 107.915 120.370 108.145 ;
        RECT 120.910 107.915 121.660 108.145 ;
        RECT 122.200 107.915 122.950 108.145 ;
        RECT 105.440 107.890 106.170 107.915 ;
        RECT 106.730 107.890 107.460 107.915 ;
        RECT 108.020 107.890 108.750 107.915 ;
        RECT 109.310 107.890 110.040 107.915 ;
        RECT 110.600 107.890 111.330 107.915 ;
        RECT 111.890 107.890 112.620 107.915 ;
        RECT 113.180 107.890 113.910 107.915 ;
        RECT 114.470 107.890 115.200 107.915 ;
        RECT 115.760 107.890 116.490 107.915 ;
        RECT 117.050 107.890 117.780 107.915 ;
        RECT 118.340 107.890 119.070 107.915 ;
        RECT 119.630 107.890 120.360 107.915 ;
        RECT 120.920 107.890 121.650 107.915 ;
        RECT 122.210 107.890 122.940 107.915 ;
        RECT 123.500 107.890 124.230 108.175 ;
        RECT 124.790 108.145 125.520 108.175 ;
        RECT 126.080 108.145 126.810 108.175 ;
        RECT 127.370 108.145 128.100 108.175 ;
        RECT 128.660 108.145 129.390 108.175 ;
        RECT 129.950 108.145 130.680 108.175 ;
        RECT 124.790 107.915 125.910 108.145 ;
        RECT 126.080 107.915 127.200 108.145 ;
        RECT 127.370 107.915 128.490 108.145 ;
        RECT 128.660 107.915 129.780 108.145 ;
        RECT 129.950 107.915 131.070 108.145 ;
        RECT 131.610 107.915 132.360 108.145 ;
        RECT 132.900 107.915 133.650 108.145 ;
        RECT 134.190 107.915 134.940 108.145 ;
        RECT 135.480 107.915 136.230 108.145 ;
        RECT 136.770 107.915 137.520 108.145 ;
        RECT 138.060 107.915 138.810 108.145 ;
        RECT 139.350 107.915 140.100 108.145 ;
        RECT 140.640 107.915 141.390 108.145 ;
        RECT 141.930 107.915 142.680 108.145 ;
        RECT 124.790 107.890 125.520 107.915 ;
        RECT 126.080 107.890 126.810 107.915 ;
        RECT 127.370 107.890 128.100 107.915 ;
        RECT 128.660 107.890 129.390 107.915 ;
        RECT 129.950 107.890 130.680 107.915 ;
        RECT 103.755 106.585 103.985 107.710 ;
        RECT 91.810 105.945 92.130 106.585 ;
        RECT 93.100 105.945 93.420 106.585 ;
        RECT 95.680 105.945 96.000 106.585 ;
        RECT 98.260 105.945 98.580 106.585 ;
        RECT 100.840 105.945 101.160 106.585 ;
        RECT 102.130 105.945 102.450 106.585 ;
        RECT 102.670 105.945 103.240 106.585 ;
        RECT 103.710 105.945 104.030 106.585 ;
        RECT 91.855 104.855 92.085 105.945 ;
        RECT 93.145 104.855 93.375 105.945 ;
        RECT 95.725 104.855 95.955 105.945 ;
        RECT 91.810 104.215 92.130 104.855 ;
        RECT 93.100 104.215 93.420 104.855 ;
        RECT 95.680 104.215 96.000 104.855 ;
        RECT 91.855 102.505 92.085 104.215 ;
        RECT 93.145 102.505 93.375 104.215 ;
        RECT 94.390 102.740 94.710 104.075 ;
        RECT 91.855 102.275 93.375 102.505 ;
        RECT 91.855 101.965 92.085 102.275 ;
        RECT 93.145 101.965 93.375 102.275 ;
        RECT 93.585 101.965 94.225 102.055 ;
        RECT 91.855 101.735 93.375 101.965 ;
        RECT 93.530 101.735 94.280 101.965 ;
        RECT 91.855 96.325 92.085 101.735 ;
        RECT 93.145 96.325 93.375 101.735 ;
        RECT 91.855 96.095 93.375 96.325 ;
        RECT 93.530 96.095 94.280 96.325 ;
        RECT 91.855 95.345 92.085 96.095 ;
        RECT 91.810 93.835 92.130 95.115 ;
        RECT 81.660 89.370 81.980 89.375 ;
        RECT 84.240 89.370 84.560 89.375 ;
        RECT 86.820 89.370 87.140 89.375 ;
        RECT 89.400 89.370 89.720 89.375 ;
        RECT 90.685 89.370 91.005 89.375 ;
        RECT 80.790 86.825 81.540 87.145 ;
        RECT 82.080 86.825 82.830 87.145 ;
        RECT 83.370 86.825 84.120 87.145 ;
        RECT 84.660 86.825 85.410 87.145 ;
        RECT 85.950 86.825 86.700 87.145 ;
        RECT 90.995 87.055 91.635 87.145 ;
        RECT 90.940 86.825 91.690 87.055 ;
        RECT 69.340 85.775 70.090 86.005 ;
        RECT 70.245 85.775 71.765 86.005 ;
        RECT 69.395 85.685 70.035 85.775 ;
        RECT 74.340 85.685 75.090 86.005 ;
        RECT 75.245 85.140 75.475 86.665 ;
        RECT 75.630 85.685 76.380 86.005 ;
        RECT 76.920 85.685 77.670 86.005 ;
        RECT 77.825 85.140 78.055 86.665 ;
        RECT 80.405 86.165 80.650 86.665 ;
        RECT 78.210 85.685 78.960 86.005 ;
        RECT 79.500 85.685 80.250 86.005 ;
        RECT 66.330 84.490 66.650 85.130 ;
        RECT 68.910 84.500 69.230 85.140 ;
        RECT 75.200 84.500 75.520 85.140 ;
        RECT 77.780 84.500 78.100 85.140 ;
        RECT 75.245 84.490 75.475 84.500 ;
        RECT 77.825 84.490 78.055 84.500 ;
        RECT 63.910 83.490 64.230 83.495 ;
        RECT 71.775 83.490 72.095 83.495 ;
        RECT 73.905 83.490 74.225 83.495 ;
        RECT 76.485 83.490 76.805 83.495 ;
        RECT 77.540 83.490 78.085 83.495 ;
        RECT 63.910 83.150 78.655 83.490 ;
        RECT 63.910 76.800 64.230 83.150 ;
        RECT 67.045 82.850 67.365 83.150 ;
        RECT 71.540 82.855 72.330 83.150 ;
        RECT 73.905 82.855 74.225 83.150 ;
        RECT 76.485 82.855 76.805 83.150 ;
        RECT 77.765 82.855 78.085 83.150 ;
        RECT 64.530 82.165 66.050 82.395 ;
        RECT 64.530 81.255 64.760 82.165 ;
        RECT 65.820 81.255 66.050 82.165 ;
        RECT 64.530 81.025 66.050 81.255 ;
        RECT 64.530 80.715 64.760 81.025 ;
        RECT 65.820 80.715 66.050 81.025 ;
        RECT 64.530 80.485 66.050 80.715 ;
        RECT 66.205 80.485 66.955 80.950 ;
        RECT 64.530 79.575 64.760 80.485 ;
        RECT 65.820 79.575 66.050 80.485 ;
        RECT 64.530 79.345 66.050 79.575 ;
        RECT 64.530 79.035 64.760 79.345 ;
        RECT 65.820 79.035 66.050 79.345 ;
        RECT 66.205 79.210 66.955 79.575 ;
        RECT 64.530 78.805 66.050 79.035 ;
        RECT 64.530 77.895 64.760 78.805 ;
        RECT 65.820 77.895 66.050 78.805 ;
        RECT 64.530 77.665 66.050 77.895 ;
        RECT 65.820 75.255 66.050 77.665 ;
        RECT 67.110 77.035 67.340 82.850 ;
        RECT 70.195 81.840 70.515 82.480 ;
        RECT 67.495 80.485 68.640 80.950 ;
        RECT 68.400 79.575 68.640 80.485 ;
        RECT 67.495 79.210 68.640 79.575 ;
        RECT 66.930 76.745 67.520 77.035 ;
        RECT 65.655 74.475 66.410 75.255 ;
        RECT 65.655 74.015 66.405 74.335 ;
        RECT 65.655 73.025 65.900 74.015 ;
        RECT 66.150 73.025 66.405 74.015 ;
        RECT 65.655 72.705 66.405 73.025 ;
        RECT 66.555 74.305 66.875 76.275 ;
        RECT 67.850 74.305 68.080 76.225 ;
        RECT 66.555 73.985 68.080 74.305 ;
        RECT 66.555 73.055 66.875 73.985 ;
        RECT 67.850 73.055 68.080 73.985 ;
        RECT 66.555 72.735 68.080 73.055 ;
        RECT 65.655 71.785 66.405 72.565 ;
        RECT 65.895 69.555 66.215 71.785 ;
        RECT 66.555 70.715 66.875 72.735 ;
        RECT 66.555 70.545 66.805 70.715 ;
        RECT 67.850 70.545 68.080 72.735 ;
        RECT 68.400 70.720 68.640 79.210 ;
        RECT 70.250 76.945 70.480 81.840 ;
        RECT 70.700 80.930 71.340 80.950 ;
        RECT 70.635 80.700 71.385 80.930 ;
        RECT 70.700 80.630 71.340 80.700 ;
        RECT 70.635 79.210 71.385 79.530 ;
        RECT 71.540 77.050 71.770 82.855 ;
        RECT 72.100 82.490 72.330 82.855 ;
        RECT 73.950 82.615 74.180 82.855 ;
        RECT 76.530 82.615 76.760 82.855 ;
        RECT 77.820 82.615 78.050 82.855 ;
        RECT 73.950 82.490 78.050 82.615 ;
        RECT 72.100 82.385 78.050 82.490 ;
        RECT 72.100 82.260 74.180 82.385 ;
        RECT 72.100 81.385 72.330 82.260 ;
        RECT 73.390 81.385 73.620 82.260 ;
        RECT 73.950 81.385 74.180 82.260 ;
        RECT 75.240 81.385 75.470 82.385 ;
        RECT 76.530 81.385 76.760 82.385 ;
        RECT 77.820 81.385 78.050 82.385 ;
        RECT 72.100 81.120 78.050 81.385 ;
        RECT 72.100 77.050 72.330 81.120 ;
        RECT 73.390 79.875 73.800 80.375 ;
        RECT 70.195 76.305 70.515 76.945 ;
        RECT 70.955 76.305 71.275 76.945 ;
        RECT 71.540 76.760 72.330 77.050 ;
        RECT 68.845 74.165 69.485 74.285 ;
        RECT 68.795 73.935 69.545 74.165 ;
        RECT 68.795 72.885 69.545 73.115 ;
        RECT 68.860 72.765 69.500 72.885 ;
        RECT 70.990 70.720 71.220 76.305 ;
        RECT 73.570 74.235 73.800 79.875 ;
        RECT 73.950 77.095 74.180 81.120 ;
        RECT 76.530 80.845 76.760 81.120 ;
        RECT 77.820 80.845 78.050 81.120 ;
        RECT 75.630 80.615 76.370 80.845 ;
        RECT 74.535 80.245 75.470 80.410 ;
        RECT 74.530 79.820 75.470 80.245 ;
        RECT 74.530 78.050 75.170 79.820 ;
        RECT 75.880 79.615 76.110 80.615 ;
        RECT 76.530 80.610 78.050 80.845 ;
        RECT 76.530 79.620 76.760 80.610 ;
        RECT 77.820 79.620 78.050 80.610 ;
        RECT 75.630 78.835 76.370 79.615 ;
        RECT 76.530 79.385 78.050 79.620 ;
        RECT 76.530 79.080 76.760 79.385 ;
        RECT 77.820 79.080 78.050 79.385 ;
        RECT 76.530 78.845 78.050 79.080 ;
        RECT 73.950 76.745 74.285 77.095 ;
        RECT 71.430 74.165 72.070 74.235 ;
        RECT 72.715 74.165 73.800 74.235 ;
        RECT 71.375 73.935 72.125 74.165 ;
        RECT 72.665 73.935 73.800 74.165 ;
        RECT 71.430 73.915 72.070 73.935 ;
        RECT 72.715 73.915 73.800 73.935 ;
        RECT 73.570 73.155 73.800 73.915 ;
        RECT 71.425 73.115 72.065 73.155 ;
        RECT 72.720 73.115 73.800 73.155 ;
        RECT 71.375 72.885 72.125 73.115 ;
        RECT 72.665 72.885 73.800 73.115 ;
        RECT 71.425 72.835 72.065 72.885 ;
        RECT 72.720 72.835 73.800 72.885 ;
        RECT 73.570 70.720 73.800 72.835 ;
        RECT 74.530 70.550 74.745 78.050 ;
        RECT 74.935 70.550 75.170 78.050 ;
        RECT 75.630 77.915 76.370 78.695 ;
        RECT 75.880 76.985 76.110 77.915 ;
        RECT 76.530 77.845 76.760 78.845 ;
        RECT 77.820 77.845 78.050 78.845 ;
        RECT 76.530 77.610 78.050 77.845 ;
        RECT 76.530 77.030 76.760 77.610 ;
        RECT 77.820 77.030 78.050 77.610 ;
        RECT 78.335 77.030 78.655 83.150 ;
        RECT 80.410 80.865 80.650 86.165 ;
        RECT 80.790 85.685 81.540 86.005 ;
        RECT 82.080 85.685 82.830 86.005 ;
        RECT 82.985 85.140 83.215 86.665 ;
        RECT 83.370 85.685 84.120 86.005 ;
        RECT 84.660 85.685 85.410 86.005 ;
        RECT 85.565 85.140 85.795 86.665 ;
        RECT 91.845 86.620 92.085 93.835 ;
        RECT 93.145 93.680 93.375 96.095 ;
        RECT 93.585 96.005 94.225 96.095 ;
        RECT 94.435 95.115 94.665 102.740 ;
        RECT 94.875 101.965 95.515 102.055 ;
        RECT 94.820 101.735 95.570 101.965 ;
        RECT 94.820 96.095 95.570 96.325 ;
        RECT 94.875 96.005 95.515 96.095 ;
        RECT 94.390 93.835 94.710 95.115 ;
        RECT 95.725 93.680 95.955 104.215 ;
        RECT 96.165 101.965 96.805 105.700 ;
        RECT 97.015 104.020 97.245 104.300 ;
        RECT 96.970 102.740 97.290 104.020 ;
        RECT 96.110 101.735 96.860 101.965 ;
        RECT 96.110 96.095 96.860 96.325 ;
        RECT 93.100 93.040 93.420 93.680 ;
        RECT 95.680 93.040 96.000 93.680 ;
        RECT 93.145 92.045 93.375 93.040 ;
        RECT 95.725 92.045 95.955 93.040 ;
        RECT 96.165 92.215 96.805 96.095 ;
        RECT 97.015 95.120 97.245 102.740 ;
        RECT 97.455 101.965 98.095 105.700 ;
        RECT 98.305 104.855 98.535 105.945 ;
        RECT 100.885 104.855 101.115 105.945 ;
        RECT 102.175 104.855 102.405 105.945 ;
        RECT 102.670 104.855 103.035 105.945 ;
        RECT 103.755 104.855 103.985 105.945 ;
        RECT 98.260 104.215 98.580 104.855 ;
        RECT 97.400 101.735 98.150 101.965 ;
        RECT 97.400 96.095 98.150 96.325 ;
        RECT 97.455 95.995 98.095 96.095 ;
        RECT 96.970 93.835 97.290 95.120 ;
        RECT 93.100 91.405 93.420 92.045 ;
        RECT 95.680 91.405 96.000 92.045 ;
        RECT 93.145 90.010 93.375 91.405 ;
        RECT 94.425 91.255 94.655 91.305 ;
        RECT 94.390 90.615 94.710 91.255 ;
        RECT 93.095 89.370 93.415 90.010 ;
        RECT 92.285 87.055 92.925 87.145 ;
        RECT 93.575 87.055 94.215 87.145 ;
        RECT 94.425 87.055 94.655 90.615 ;
        RECT 95.725 90.005 95.955 91.405 ;
        RECT 95.675 89.365 95.995 90.005 ;
        RECT 94.865 87.055 95.505 87.145 ;
        RECT 96.155 87.055 96.795 87.145 ;
        RECT 92.230 86.825 92.980 87.055 ;
        RECT 93.520 86.825 95.560 87.055 ;
        RECT 96.100 86.825 96.850 87.055 ;
        RECT 91.845 86.165 92.075 86.620 ;
        RECT 94.425 86.005 94.655 86.825 ;
        RECT 97.005 86.635 97.245 93.835 ;
        RECT 97.455 92.855 98.090 95.995 ;
        RECT 98.305 93.680 98.535 104.215 ;
        RECT 99.595 104.020 99.825 104.325 ;
        RECT 100.840 104.215 101.160 104.855 ;
        RECT 102.130 104.215 102.450 104.855 ;
        RECT 102.670 104.215 103.260 104.855 ;
        RECT 103.710 104.215 104.030 104.855 ;
        RECT 99.550 102.740 99.870 104.020 ;
        RECT 98.745 101.965 99.385 102.055 ;
        RECT 98.690 101.735 99.440 101.965 ;
        RECT 98.690 96.095 99.440 96.325 ;
        RECT 98.745 96.005 99.385 96.095 ;
        RECT 99.595 95.115 99.825 102.740 ;
        RECT 100.885 102.505 101.115 104.215 ;
        RECT 102.175 102.505 102.405 104.215 ;
        RECT 100.885 102.275 102.405 102.505 ;
        RECT 100.035 101.965 100.675 102.055 ;
        RECT 100.885 101.965 101.115 102.275 ;
        RECT 102.175 101.965 102.405 102.275 ;
        RECT 99.980 101.735 100.730 101.965 ;
        RECT 100.885 101.735 102.405 101.965 ;
        RECT 100.885 96.325 101.115 101.735 ;
        RECT 102.175 96.325 102.405 101.735 ;
        RECT 99.980 96.095 100.730 96.325 ;
        RECT 100.885 96.095 102.405 96.325 ;
        RECT 100.035 96.005 100.675 96.095 ;
        RECT 99.550 93.835 99.870 95.115 ;
        RECT 100.885 93.680 101.115 96.095 ;
        RECT 102.175 95.390 102.405 96.095 ;
        RECT 98.260 93.040 98.580 93.680 ;
        RECT 100.830 93.040 101.150 93.680 ;
        RECT 97.450 92.215 98.090 92.855 ;
        RECT 98.305 92.045 98.535 93.040 ;
        RECT 100.885 92.045 101.115 93.040 ;
        RECT 98.260 91.405 98.580 92.045 ;
        RECT 100.830 91.405 101.150 92.045 ;
        RECT 98.305 90.005 98.535 91.405 ;
        RECT 100.885 90.010 101.115 91.405 ;
        RECT 98.260 89.365 98.580 90.005 ;
        RECT 100.830 89.370 101.150 90.010 ;
        RECT 97.445 87.055 98.085 87.145 ;
        RECT 97.390 86.825 98.140 87.055 ;
        RECT 97.005 86.165 97.235 86.635 ;
        RECT 85.950 85.685 86.700 86.005 ;
        RECT 90.940 85.775 91.690 86.005 ;
        RECT 92.230 85.775 92.980 86.005 ;
        RECT 93.520 85.775 95.560 86.005 ;
        RECT 96.100 85.775 96.850 86.005 ;
        RECT 97.390 85.775 98.140 86.005 ;
        RECT 90.995 85.685 91.635 85.775 ;
        RECT 92.285 85.685 92.925 85.775 ;
        RECT 93.575 85.685 94.215 85.775 ;
        RECT 94.865 85.685 95.505 85.775 ;
        RECT 96.155 85.685 96.795 85.775 ;
        RECT 97.445 85.685 98.085 85.775 ;
        RECT 82.940 84.500 83.260 85.140 ;
        RECT 85.520 84.500 85.840 85.140 ;
        RECT 82.985 84.490 83.215 84.500 ;
        RECT 85.565 84.490 85.795 84.500 ;
        RECT 101.290 81.035 102.350 95.120 ;
        RECT 102.670 90.010 103.035 104.215 ;
        RECT 103.755 93.680 103.985 104.215 ;
        RECT 103.710 93.040 104.030 93.680 ;
        RECT 103.755 92.045 103.985 93.040 ;
        RECT 103.710 91.405 104.030 92.045 ;
        RECT 103.755 90.010 103.985 91.405 ;
        RECT 102.670 89.370 103.240 90.010 ;
        RECT 103.710 89.370 104.030 90.010 ;
        RECT 103.755 83.495 103.985 89.370 ;
        RECT 103.710 82.855 104.030 83.495 ;
        RECT 80.365 80.225 80.685 80.865 ;
        RECT 90.100 80.225 94.030 80.865 ;
        RECT 98.300 80.070 102.350 81.035 ;
        RECT 99.945 77.225 101.625 77.230 ;
        RECT 75.365 76.345 75.685 76.985 ;
        RECT 75.830 76.345 76.150 76.985 ;
        RECT 76.425 76.740 77.015 77.030 ;
        RECT 77.655 76.740 78.655 77.030 ;
        RECT 99.545 76.865 101.625 77.225 ;
        RECT 99.540 76.830 101.625 76.865 ;
        RECT 78.335 76.715 78.655 76.740 ;
        RECT 89.580 76.825 91.460 76.830 ;
        RECT 89.580 76.580 93.500 76.825 ;
        RECT 75.420 73.275 75.650 76.345 ;
        RECT 75.865 73.915 76.505 74.235 ;
        RECT 66.555 70.225 66.875 70.545 ;
        RECT 67.805 70.225 68.125 70.545 ;
        RECT 74.530 70.230 75.170 70.550 ;
        RECT 75.390 70.550 75.650 73.275 ;
        RECT 75.860 72.835 76.500 73.155 ;
        RECT 89.580 72.965 89.900 76.580 ;
        RECT 91.395 76.575 93.500 76.580 ;
        RECT 99.520 76.575 101.625 76.830 ;
        RECT 99.545 75.945 101.625 76.575 ;
        RECT 89.580 72.715 93.230 72.965 ;
        RECT 75.390 70.230 75.710 70.550 ;
        RECT 67.860 69.555 68.180 69.615 ;
        RECT 74.025 69.555 74.345 69.735 ;
        RECT 64.115 69.305 66.220 69.555 ;
        RECT 67.860 69.305 69.965 69.555 ;
        RECT 72.240 69.305 74.345 69.555 ;
        RECT 75.985 69.555 76.305 69.735 ;
        RECT 75.985 69.305 78.090 69.555 ;
        RECT 67.860 69.295 68.180 69.305 ;
        RECT 103.755 61.710 103.985 82.855 ;
        RECT 105.045 61.710 105.275 107.710 ;
        RECT 106.335 61.710 106.565 107.710 ;
        RECT 107.625 61.710 107.855 107.710 ;
        RECT 108.915 61.710 109.145 107.710 ;
        RECT 110.205 61.710 110.435 107.710 ;
        RECT 111.495 61.710 111.725 107.710 ;
        RECT 112.785 61.710 113.015 107.710 ;
        RECT 114.075 61.710 114.305 107.710 ;
        RECT 115.365 61.710 115.595 107.710 ;
        RECT 116.655 61.710 116.885 107.710 ;
        RECT 117.945 61.710 118.175 107.710 ;
        RECT 119.235 61.710 119.465 107.710 ;
        RECT 120.525 61.710 120.755 107.710 ;
        RECT 121.815 61.710 122.045 107.710 ;
        RECT 123.105 61.710 123.335 107.710 ;
        RECT 124.775 61.710 125.005 107.710 ;
        RECT 126.065 61.710 126.295 107.710 ;
        RECT 127.355 61.710 127.585 107.710 ;
        RECT 128.645 61.710 128.875 107.710 ;
        RECT 129.935 61.710 130.165 107.710 ;
        RECT 131.225 61.710 131.455 107.710 ;
        RECT 132.515 61.710 132.745 107.710 ;
        RECT 133.805 61.710 134.035 107.710 ;
        RECT 135.095 61.710 135.325 107.710 ;
        RECT 136.385 61.710 136.615 107.710 ;
        RECT 137.675 61.710 137.905 107.710 ;
        RECT 138.965 61.710 139.195 107.710 ;
        RECT 140.255 61.710 140.485 107.710 ;
        RECT 141.545 61.710 141.775 107.710 ;
        RECT 142.835 61.710 143.065 107.710 ;
        RECT 104.140 61.275 104.890 61.505 ;
        RECT 105.430 61.275 106.180 61.505 ;
        RECT 106.720 61.275 107.470 61.505 ;
        RECT 108.010 61.275 108.760 61.505 ;
        RECT 109.300 61.275 110.050 61.505 ;
        RECT 110.590 61.275 111.340 61.505 ;
        RECT 111.880 61.275 112.630 61.505 ;
        RECT 113.170 61.275 113.920 61.505 ;
        RECT 114.460 61.275 115.210 61.505 ;
        RECT 115.750 61.275 116.500 61.505 ;
        RECT 117.040 61.275 117.790 61.505 ;
        RECT 118.330 61.275 119.080 61.505 ;
        RECT 119.620 61.275 120.370 61.505 ;
        RECT 120.910 61.275 121.660 61.505 ;
        RECT 122.200 61.275 122.950 61.505 ;
        RECT 125.160 61.275 125.910 61.505 ;
        RECT 126.450 61.275 127.200 61.505 ;
        RECT 127.740 61.275 128.490 61.505 ;
        RECT 129.030 61.275 129.780 61.505 ;
        RECT 130.320 61.275 131.070 61.505 ;
        RECT 131.610 61.275 132.360 61.505 ;
        RECT 132.900 61.275 133.650 61.505 ;
        RECT 134.190 61.275 134.940 61.505 ;
        RECT 135.480 61.275 136.230 61.505 ;
        RECT 136.770 61.275 137.520 61.505 ;
        RECT 138.060 61.275 138.810 61.505 ;
        RECT 139.350 61.275 140.100 61.505 ;
        RECT 140.640 61.275 141.390 61.505 ;
        RECT 141.930 61.275 142.680 61.505 ;
        RECT 105.440 49.750 106.170 50.035 ;
        RECT 106.730 49.750 107.460 50.035 ;
        RECT 108.020 49.750 108.750 50.035 ;
        RECT 109.310 49.750 110.040 50.035 ;
        RECT 110.600 49.750 111.330 50.035 ;
        RECT 111.890 49.750 112.620 50.035 ;
        RECT 113.180 49.750 113.910 50.035 ;
        RECT 114.470 49.750 115.200 50.035 ;
        RECT 115.760 49.750 116.490 50.035 ;
        RECT 117.050 49.750 117.780 50.035 ;
        RECT 118.340 49.750 119.070 50.035 ;
        RECT 119.630 49.750 120.360 50.035 ;
        RECT 120.920 49.750 121.650 50.035 ;
        RECT 122.210 49.750 122.940 50.035 ;
        RECT 123.500 49.750 124.230 50.035 ;
        RECT 124.790 49.750 125.520 50.035 ;
        RECT 126.080 49.750 126.810 50.035 ;
        RECT 127.370 49.750 128.100 50.035 ;
        RECT 128.660 49.750 129.390 50.035 ;
        RECT 129.950 49.750 130.680 50.035 ;
        RECT 103.585 49.220 132.535 49.495 ;
      LAYER met2 ;
        RECT 63.915 214.160 133.800 214.600 ;
        RECT 63.915 213.830 105.635 214.160 ;
        RECT 106.050 213.625 131.645 214.020 ;
        RECT 78.630 212.610 89.270 213.250 ;
        RECT 82.500 212.380 82.820 212.385 ;
        RECT 63.915 211.740 133.800 212.380 ;
        RECT 9.160 210.405 44.750 211.730 ;
        RECT 76.050 210.855 98.935 211.495 ;
        RECT 63.915 210.010 133.800 210.650 ;
        RECT 68.460 209.145 90.070 209.785 ;
        RECT 68.505 209.140 90.070 209.145 ;
        RECT 66.315 207.535 70.875 207.855 ;
        RECT 75.245 207.850 75.935 209.140 ;
        RECT 82.320 207.850 83.010 209.140 ;
        RECT 89.380 207.850 90.070 209.140 ;
        RECT 95.230 208.535 133.800 209.870 ;
        RECT 94.425 207.850 101.505 207.860 ;
        RECT 66.365 207.530 67.005 207.535 ;
        RECT 67.655 207.530 68.295 207.535 ;
        RECT 68.945 207.530 69.585 207.535 ;
        RECT 70.230 207.530 70.870 207.535 ;
        RECT 75.245 207.530 90.075 207.850 ;
        RECT 94.425 207.530 101.515 207.850 ;
        RECT 66.365 201.805 70.875 202.125 ;
        RECT 67.655 201.800 68.295 201.805 ;
        RECT 68.945 201.800 69.585 201.805 ;
        RECT 70.235 201.800 70.875 201.805 ;
        RECT 75.245 201.800 90.075 202.120 ;
        RECT 75.245 200.520 75.935 201.800 ;
        RECT 82.350 200.520 83.040 201.800 ;
        RECT 89.385 200.520 90.075 201.800 ;
        RECT 94.410 201.790 101.515 202.120 ;
        RECT 92.655 200.910 133.800 200.915 ;
        RECT 68.460 199.880 90.075 200.520 ;
        RECT 68.505 199.875 90.075 199.880 ;
        RECT 92.650 199.630 133.800 200.910 ;
        RECT 63.915 198.835 133.800 199.475 ;
        RECT 76.050 198.010 98.930 198.650 ;
        RECT 63.915 197.200 133.800 197.840 ;
        RECT 10.700 195.705 14.945 196.665 ;
        RECT 78.630 196.410 95.550 197.050 ;
        RECT 63.915 195.165 133.800 195.805 ;
        RECT 63.915 195.135 64.335 195.165 ;
        RECT 96.515 195.160 96.835 195.165 ;
        RECT 99.100 195.160 99.420 195.165 ;
        RECT 121.320 195.160 121.640 195.165 ;
        RECT 66.365 192.620 67.005 192.940 ;
        RECT 70.235 192.620 70.875 192.940 ;
        RECT 75.235 192.590 87.485 192.960 ;
        RECT 91.835 192.620 98.925 192.940 ;
        RECT 66.365 191.480 67.005 191.800 ;
        RECT 70.235 191.480 70.875 191.800 ;
        RECT 75.235 191.455 87.485 191.825 ;
        RECT 91.835 191.480 98.925 191.800 ;
        RECT 67.170 190.285 86.680 190.935 ;
        RECT 63.915 188.650 133.800 189.290 ;
        RECT 63.950 188.630 64.345 188.650 ;
        RECT 64.750 188.645 65.070 188.650 ;
        RECT 67.885 188.645 68.205 188.650 ;
        RECT 79.175 188.645 79.495 188.650 ;
        RECT 71.035 187.635 87.345 188.275 ;
        RECT 67.085 186.425 72.180 186.745 ;
        RECT 81.205 186.020 91.580 186.660 ;
        RECT 67.045 185.005 72.180 185.325 ;
        RECT 76.470 183.710 77.210 185.410 ;
        RECT 63.915 182.930 79.935 183.570 ;
        RECT 71.035 182.100 72.115 182.740 ;
        RECT 76.205 182.140 76.990 182.780 ;
        RECT 66.480 181.275 90.740 181.915 ;
        RECT 66.495 180.270 67.250 181.050 ;
        RECT 66.495 179.810 67.245 180.270 ;
        RECT 67.840 180.080 70.310 180.100 ;
        RECT 67.840 179.780 70.325 180.080 ;
        RECT 69.685 179.760 70.325 179.780 ;
        RECT 72.270 179.710 77.345 180.030 ;
        RECT 100.375 179.535 133.800 183.020 ;
        RECT 69.700 178.850 70.340 178.880 ;
        RECT 66.495 177.580 67.245 178.820 ;
        RECT 67.840 178.530 70.340 178.850 ;
        RECT 72.265 178.630 77.340 178.950 ;
        RECT 67.395 176.020 69.020 176.340 ;
        RECT 68.700 175.090 69.020 176.020 ;
        RECT 74.865 176.025 76.010 176.345 ;
        RECT 76.230 176.025 77.145 176.345 ;
        RECT 74.865 175.210 75.185 176.025 ;
        RECT 76.825 175.210 77.145 176.025 ;
        RECT 106.145 155.495 131.655 155.880 ;
        RECT 104.475 154.965 133.325 155.340 ;
        RECT 63.075 108.365 132.960 108.805 ;
        RECT 63.075 108.035 104.795 108.365 ;
        RECT 105.210 107.830 130.805 108.225 ;
        RECT 77.790 106.815 88.430 107.455 ;
        RECT 81.660 106.585 81.980 106.590 ;
        RECT 63.075 105.945 132.960 106.585 ;
        RECT 75.210 105.060 98.095 105.700 ;
        RECT 63.075 104.215 132.960 104.855 ;
        RECT 67.620 103.350 89.230 103.990 ;
        RECT 67.665 103.345 89.230 103.350 ;
        RECT 65.475 101.740 70.035 102.060 ;
        RECT 74.405 102.055 75.095 103.345 ;
        RECT 81.480 102.055 82.170 103.345 ;
        RECT 88.540 102.055 89.230 103.345 ;
        RECT 94.390 102.740 132.960 104.075 ;
        RECT 93.585 102.055 100.665 102.065 ;
        RECT 65.525 101.735 66.165 101.740 ;
        RECT 66.815 101.735 67.455 101.740 ;
        RECT 68.105 101.735 68.745 101.740 ;
        RECT 69.390 101.735 70.030 101.740 ;
        RECT 74.405 101.735 89.235 102.055 ;
        RECT 93.585 101.735 100.675 102.055 ;
        RECT 65.525 96.010 70.035 96.330 ;
        RECT 66.815 96.005 67.455 96.010 ;
        RECT 68.105 96.005 68.745 96.010 ;
        RECT 69.395 96.005 70.035 96.010 ;
        RECT 74.405 96.005 89.235 96.325 ;
        RECT 74.405 94.725 75.095 96.005 ;
        RECT 81.510 94.725 82.200 96.005 ;
        RECT 88.545 94.725 89.235 96.005 ;
        RECT 93.570 95.995 100.675 96.325 ;
        RECT 91.815 95.115 132.960 95.120 ;
        RECT 67.620 94.085 89.235 94.725 ;
        RECT 67.665 94.080 89.235 94.085 ;
        RECT 91.810 93.835 132.960 95.115 ;
        RECT 63.075 93.040 132.960 93.680 ;
        RECT 75.210 92.215 98.090 92.855 ;
        RECT 63.075 91.405 132.960 92.045 ;
        RECT 77.790 90.615 94.710 91.255 ;
        RECT 63.075 89.370 132.960 90.010 ;
        RECT 63.075 89.340 63.495 89.370 ;
        RECT 95.675 89.365 95.995 89.370 ;
        RECT 98.260 89.365 98.580 89.370 ;
        RECT 120.480 89.365 120.800 89.370 ;
        RECT 65.525 86.825 66.165 87.145 ;
        RECT 69.395 86.825 70.035 87.145 ;
        RECT 74.395 86.795 86.645 87.165 ;
        RECT 90.995 86.825 98.085 87.145 ;
        RECT 65.525 85.685 66.165 86.005 ;
        RECT 69.395 85.685 70.035 86.005 ;
        RECT 74.395 85.660 86.645 86.030 ;
        RECT 90.995 85.685 98.085 86.005 ;
        RECT 66.330 84.490 85.840 85.140 ;
        RECT 63.075 82.855 132.960 83.495 ;
        RECT 63.910 82.850 64.230 82.855 ;
        RECT 67.045 82.850 67.365 82.855 ;
        RECT 78.335 82.850 78.655 82.855 ;
        RECT 70.195 81.840 86.505 82.480 ;
        RECT 66.245 80.630 71.340 80.950 ;
        RECT 80.365 80.225 90.740 80.865 ;
        RECT 66.205 79.210 71.340 79.530 ;
        RECT 75.630 77.915 76.370 79.615 ;
        RECT 63.075 77.135 79.095 77.775 ;
        RECT 70.195 76.305 71.275 76.945 ;
        RECT 75.365 76.345 76.150 76.985 ;
        RECT 65.640 75.480 89.900 76.120 ;
        RECT 65.655 74.475 66.410 75.255 ;
        RECT 65.655 74.015 66.405 74.475 ;
        RECT 67.000 74.285 69.470 74.305 ;
        RECT 67.000 73.985 69.485 74.285 ;
        RECT 68.845 73.965 69.485 73.985 ;
        RECT 71.430 73.915 76.505 74.235 ;
        RECT 99.535 73.740 132.960 77.225 ;
        RECT 68.860 73.055 69.500 73.085 ;
        RECT 65.655 71.785 66.405 73.025 ;
        RECT 67.000 72.735 69.500 73.055 ;
        RECT 71.425 72.835 76.500 73.155 ;
        RECT 66.555 70.225 68.180 70.545 ;
        RECT 67.860 69.295 68.180 70.225 ;
        RECT 74.025 70.230 75.170 70.550 ;
        RECT 75.390 70.230 76.305 70.550 ;
        RECT 74.025 69.415 74.345 70.230 ;
        RECT 75.985 69.415 76.305 70.230 ;
        RECT 105.305 49.700 130.815 50.085 ;
        RECT 103.635 49.170 132.485 49.545 ;
      LAYER met3 ;
        RECT 63.915 195.365 64.380 214.600 ;
        RECT 64.680 195.365 65.145 214.600 ;
        RECT 65.445 195.365 65.910 214.600 ;
        RECT 66.210 195.365 66.675 214.600 ;
        RECT 66.975 195.365 67.440 214.600 ;
        RECT 67.740 195.365 68.205 214.600 ;
        RECT 68.505 195.365 68.970 214.600 ;
        RECT 69.270 195.365 69.735 214.600 ;
        RECT 70.035 195.365 70.500 214.600 ;
        RECT 70.800 195.365 71.265 214.600 ;
        RECT 71.565 195.365 72.030 214.600 ;
        RECT 72.330 195.365 72.795 214.600 ;
        RECT 73.095 195.365 73.560 214.600 ;
        RECT 73.860 195.365 74.325 214.600 ;
        RECT 74.625 195.365 75.090 214.600 ;
        RECT 75.390 195.365 75.855 214.600 ;
        RECT 76.155 195.365 76.620 214.600 ;
        RECT 76.920 195.365 77.385 214.600 ;
        RECT 77.685 195.365 78.150 214.600 ;
        RECT 78.450 195.365 78.915 214.600 ;
        RECT 79.215 195.365 79.680 214.600 ;
        RECT 79.980 195.365 80.445 214.600 ;
        RECT 80.745 195.365 81.210 214.600 ;
        RECT 81.510 210.395 81.975 214.600 ;
        RECT 82.275 210.395 82.740 214.600 ;
        RECT 83.040 210.395 83.505 214.600 ;
        RECT 81.820 195.230 83.505 209.785 ;
        RECT 83.805 195.365 84.270 214.600 ;
        RECT 84.570 195.365 85.035 214.600 ;
        RECT 85.335 195.365 85.800 214.600 ;
        RECT 86.100 195.365 86.565 214.600 ;
        RECT 86.865 195.365 87.330 214.600 ;
        RECT 87.630 195.365 88.095 214.600 ;
        RECT 88.395 195.365 88.860 214.600 ;
        RECT 89.160 195.365 89.625 214.600 ;
        RECT 89.925 195.365 90.390 214.600 ;
        RECT 90.690 195.365 91.155 214.600 ;
        RECT 91.455 195.365 91.920 214.600 ;
        RECT 92.220 195.365 92.685 214.600 ;
        RECT 92.985 195.365 93.450 214.600 ;
        RECT 93.750 195.365 94.215 214.600 ;
        RECT 94.515 195.365 94.980 214.600 ;
        RECT 95.280 195.365 95.745 214.600 ;
        RECT 96.045 195.365 96.510 214.600 ;
        RECT 96.810 195.365 97.275 214.600 ;
        RECT 97.575 195.365 98.040 214.600 ;
        RECT 98.340 195.365 98.805 214.600 ;
        RECT 99.105 195.365 99.570 214.600 ;
        RECT 99.870 195.365 100.335 214.600 ;
        RECT 100.635 195.365 101.100 214.600 ;
        RECT 63.915 182.930 64.380 189.130 ;
        RECT 64.680 182.930 65.145 189.060 ;
        RECT 65.445 182.930 65.910 189.060 ;
        RECT 66.480 181.275 66.885 192.965 ;
        RECT 67.185 182.930 67.650 189.060 ;
        RECT 67.950 182.930 68.415 189.060 ;
        RECT 68.715 182.930 69.180 189.060 ;
        RECT 69.480 182.930 69.945 189.060 ;
        RECT 70.350 181.275 70.755 192.965 ;
        RECT 71.055 182.930 71.520 189.060 ;
        RECT 71.820 182.930 72.285 189.060 ;
        RECT 72.585 182.930 73.050 189.060 ;
        RECT 73.350 182.930 73.815 189.060 ;
        RECT 74.115 182.930 74.580 189.060 ;
        RECT 75.370 187.635 75.740 192.960 ;
        RECT 74.880 182.930 75.345 186.810 ;
        RECT 75.645 182.930 76.110 186.810 ;
        RECT 76.410 182.930 76.875 189.060 ;
        RECT 77.175 182.930 77.640 189.060 ;
        RECT 77.940 182.930 78.405 189.060 ;
        RECT 78.705 182.930 79.170 189.060 ;
        RECT 79.470 182.930 79.935 189.060 ;
        RECT 81.820 172.865 83.500 195.230 ;
        RECT 101.400 195.165 101.865 214.600 ;
        RECT 102.165 195.165 102.630 214.600 ;
        RECT 102.930 195.165 103.395 214.600 ;
        RECT 103.695 195.165 104.520 214.600 ;
        RECT 86.975 191.825 87.345 192.960 ;
        RECT 86.970 191.455 87.345 191.825 ;
        RECT 86.975 187.635 87.345 191.455 ;
        RECT 104.055 162.995 104.520 195.165 ;
        RECT 104.820 166.410 105.285 214.600 ;
        RECT 106.065 167.070 107.225 214.020 ;
        RECT 107.880 166.410 108.345 214.600 ;
        RECT 108.645 167.070 109.875 214.020 ;
        RECT 110.175 183.345 110.640 214.600 ;
        RECT 110.940 183.345 111.405 214.600 ;
        RECT 111.705 183.345 112.170 214.600 ;
        RECT 112.470 183.345 112.935 214.600 ;
        RECT 113.235 183.345 113.700 214.600 ;
        RECT 114.000 183.350 114.475 214.600 ;
        RECT 114.775 183.345 115.250 214.600 ;
        RECT 115.550 183.345 116.025 214.600 ;
        RECT 116.325 183.345 116.800 214.600 ;
        RECT 117.105 183.345 117.685 214.600 ;
        RECT 118.125 183.310 118.590 214.600 ;
        RECT 118.890 183.310 119.355 214.600 ;
        RECT 119.655 183.310 120.120 214.600 ;
        RECT 120.420 183.310 120.885 214.600 ;
        RECT 121.185 183.310 121.650 214.600 ;
        RECT 121.950 183.310 122.415 214.600 ;
        RECT 122.715 183.310 123.180 214.600 ;
        RECT 123.480 183.310 123.945 214.600 ;
        RECT 124.245 183.310 124.710 214.600 ;
        RECT 125.010 183.310 125.475 214.600 ;
        RECT 125.775 183.335 126.240 214.600 ;
        RECT 126.540 183.335 127.005 214.600 ;
        RECT 127.305 183.335 127.770 214.600 ;
        RECT 111.045 162.995 112.725 183.005 ;
        RECT 113.025 162.995 114.705 183.005 ;
        RECT 63.665 150.595 79.525 162.995 ;
        RECT 80.725 150.595 96.585 162.995 ;
        RECT 97.785 150.595 114.705 162.995 ;
        RECT 111.045 149.395 112.725 150.595 ;
        RECT 113.025 149.395 114.705 150.595 ;
        RECT 63.665 136.995 79.525 149.395 ;
        RECT 80.725 136.995 96.585 149.395 ;
        RECT 97.785 136.995 114.705 149.395 ;
        RECT 111.045 135.795 112.725 136.995 ;
        RECT 113.025 135.795 114.705 136.995 ;
        RECT 63.665 123.395 79.525 135.795 ;
        RECT 80.725 123.395 96.585 135.795 ;
        RECT 97.785 123.395 114.705 135.795 ;
        RECT 111.045 120.585 112.725 123.395 ;
        RECT 113.025 120.585 114.705 123.395 ;
        RECT 123.225 180.415 124.910 183.005 ;
        RECT 123.225 120.590 124.905 180.415 ;
        RECT 125.285 120.585 126.965 183.005 ;
        RECT 128.070 167.070 129.230 214.020 ;
        RECT 129.530 166.410 129.995 214.600 ;
        RECT 130.295 167.070 131.455 214.020 ;
        RECT 131.755 166.410 132.220 214.600 ;
        RECT 132.520 166.410 132.985 214.600 ;
        RECT 133.285 166.410 133.750 214.600 ;
        RECT 63.075 89.570 63.540 108.805 ;
        RECT 63.840 89.570 64.305 108.805 ;
        RECT 64.605 89.570 65.070 108.805 ;
        RECT 65.370 89.570 65.835 108.805 ;
        RECT 66.135 89.570 66.600 108.805 ;
        RECT 66.900 89.570 67.365 108.805 ;
        RECT 67.665 89.570 68.130 108.805 ;
        RECT 68.430 89.570 68.895 108.805 ;
        RECT 69.195 89.570 69.660 108.805 ;
        RECT 69.960 89.570 70.425 108.805 ;
        RECT 70.725 89.570 71.190 108.805 ;
        RECT 71.490 89.570 71.955 108.805 ;
        RECT 72.255 89.570 72.720 108.805 ;
        RECT 73.020 89.570 73.485 108.805 ;
        RECT 73.785 89.570 74.250 108.805 ;
        RECT 74.550 89.570 75.015 108.805 ;
        RECT 75.315 89.570 75.780 108.805 ;
        RECT 76.080 89.570 76.545 108.805 ;
        RECT 76.845 89.570 77.310 108.805 ;
        RECT 77.610 89.570 78.075 108.805 ;
        RECT 78.375 89.570 78.840 108.805 ;
        RECT 79.140 89.570 79.605 108.805 ;
        RECT 79.905 89.570 80.370 108.805 ;
        RECT 80.670 104.600 81.135 108.805 ;
        RECT 81.435 104.600 81.900 108.805 ;
        RECT 82.200 104.600 82.665 108.805 ;
        RECT 80.980 89.435 82.665 103.990 ;
        RECT 82.965 89.570 83.430 108.805 ;
        RECT 83.730 89.570 84.195 108.805 ;
        RECT 84.495 89.570 84.960 108.805 ;
        RECT 85.260 89.570 85.725 108.805 ;
        RECT 86.025 89.570 86.490 108.805 ;
        RECT 86.790 89.570 87.255 108.805 ;
        RECT 87.555 89.570 88.020 108.805 ;
        RECT 88.320 89.570 88.785 108.805 ;
        RECT 89.085 89.570 89.550 108.805 ;
        RECT 89.850 89.570 90.315 108.805 ;
        RECT 90.615 89.570 91.080 108.805 ;
        RECT 91.380 89.570 91.845 108.805 ;
        RECT 92.145 89.570 92.610 108.805 ;
        RECT 92.910 89.570 93.375 108.805 ;
        RECT 93.675 89.570 94.140 108.805 ;
        RECT 94.440 89.570 94.905 108.805 ;
        RECT 95.205 89.570 95.670 108.805 ;
        RECT 95.970 89.570 96.435 108.805 ;
        RECT 96.735 89.570 97.200 108.805 ;
        RECT 97.500 89.570 97.965 108.805 ;
        RECT 98.265 89.570 98.730 108.805 ;
        RECT 99.030 89.570 99.495 108.805 ;
        RECT 99.795 89.570 100.260 108.805 ;
        RECT 63.075 77.135 63.540 83.335 ;
        RECT 63.840 77.135 64.305 83.265 ;
        RECT 64.605 77.135 65.070 83.265 ;
        RECT 65.640 75.480 66.045 87.170 ;
        RECT 66.345 77.135 66.810 83.265 ;
        RECT 67.110 77.135 67.575 83.265 ;
        RECT 67.875 77.135 68.340 83.265 ;
        RECT 68.640 77.135 69.105 83.265 ;
        RECT 69.510 75.480 69.915 87.170 ;
        RECT 70.215 77.135 70.680 83.265 ;
        RECT 70.980 77.135 71.445 83.265 ;
        RECT 71.745 77.135 72.210 83.265 ;
        RECT 72.510 77.135 72.975 83.265 ;
        RECT 73.275 77.135 73.740 83.265 ;
        RECT 74.530 81.840 74.900 87.165 ;
        RECT 74.040 77.135 74.505 81.015 ;
        RECT 74.805 77.135 75.270 81.015 ;
        RECT 75.570 77.135 76.035 83.265 ;
        RECT 76.335 77.135 76.800 83.265 ;
        RECT 77.100 77.135 77.565 83.265 ;
        RECT 77.865 77.135 78.330 83.265 ;
        RECT 78.630 77.135 79.095 83.265 ;
        RECT 80.980 67.070 82.660 89.435 ;
        RECT 100.560 89.370 101.025 108.805 ;
        RECT 101.325 89.370 101.790 108.805 ;
        RECT 102.090 89.370 102.555 108.805 ;
        RECT 102.855 89.370 103.680 108.805 ;
        RECT 86.135 86.030 86.505 87.165 ;
        RECT 86.130 85.660 86.505 86.030 ;
        RECT 86.135 81.840 86.505 85.660 ;
        RECT 103.215 57.200 103.680 89.370 ;
        RECT 103.980 60.615 104.445 108.805 ;
        RECT 105.225 61.275 106.385 108.225 ;
        RECT 107.040 60.615 107.505 108.805 ;
        RECT 107.805 61.275 109.035 108.225 ;
        RECT 109.335 77.550 109.800 108.805 ;
        RECT 110.100 77.550 110.565 108.805 ;
        RECT 110.865 77.550 111.330 108.805 ;
        RECT 111.630 77.550 112.095 108.805 ;
        RECT 112.395 77.550 112.860 108.805 ;
        RECT 113.160 77.555 113.635 108.805 ;
        RECT 113.935 77.550 114.410 108.805 ;
        RECT 114.710 77.550 115.185 108.805 ;
        RECT 115.485 77.550 115.960 108.805 ;
        RECT 116.265 77.550 116.845 108.805 ;
        RECT 117.285 77.515 117.750 108.805 ;
        RECT 118.050 77.515 118.515 108.805 ;
        RECT 118.815 77.515 119.280 108.805 ;
        RECT 119.580 77.515 120.045 108.805 ;
        RECT 120.345 77.515 120.810 108.805 ;
        RECT 121.110 77.515 121.575 108.805 ;
        RECT 121.875 77.515 122.340 108.805 ;
        RECT 122.640 77.515 123.105 108.805 ;
        RECT 123.405 77.515 123.870 108.805 ;
        RECT 124.170 77.515 124.635 108.805 ;
        RECT 124.935 77.540 125.400 108.805 ;
        RECT 125.700 77.540 126.165 108.805 ;
        RECT 126.465 77.540 126.930 108.805 ;
        RECT 110.205 57.200 111.885 77.210 ;
        RECT 112.185 57.200 113.865 77.210 ;
        RECT 62.825 44.800 78.685 57.200 ;
        RECT 79.885 44.800 95.745 57.200 ;
        RECT 96.945 44.800 113.865 57.200 ;
        RECT 110.205 43.600 111.885 44.800 ;
        RECT 112.185 43.600 113.865 44.800 ;
        RECT 62.825 31.200 78.685 43.600 ;
        RECT 79.885 31.200 95.745 43.600 ;
        RECT 96.945 31.200 113.865 43.600 ;
        RECT 110.205 30.000 111.885 31.200 ;
        RECT 112.185 30.000 113.865 31.200 ;
        RECT 62.825 17.600 78.685 30.000 ;
        RECT 79.885 17.600 95.745 30.000 ;
        RECT 96.945 17.600 113.865 30.000 ;
        RECT 110.205 14.790 111.885 17.600 ;
        RECT 112.185 14.790 113.865 17.600 ;
        RECT 122.385 74.620 124.070 77.210 ;
        RECT 122.385 14.795 124.065 74.620 ;
        RECT 124.445 14.790 126.125 77.210 ;
        RECT 127.230 61.275 128.390 108.225 ;
        RECT 128.690 60.615 129.155 108.805 ;
        RECT 129.455 61.275 130.615 108.225 ;
        RECT 130.915 60.615 131.380 108.805 ;
        RECT 131.680 60.615 132.145 108.805 ;
        RECT 132.445 60.615 132.910 108.805 ;
      LAYER met4 ;
        RECT 67.960 172.865 103.025 173.670 ;
        RECT 67.960 170.665 68.905 172.865 ;
        RECT 85.020 170.665 85.965 172.865 ;
        RECT 102.080 170.665 103.025 172.865 ;
        RECT 70.605 162.600 71.125 163.595 ;
        RECT 64.060 150.990 77.670 162.600 ;
        RECT 79.005 162.120 79.525 163.595 ;
        RECT 87.665 162.600 88.185 163.595 ;
        RECT 70.605 149.000 71.125 150.990 ;
        RECT 64.060 137.390 77.670 149.000 ;
        RECT 70.605 135.400 71.125 137.390 ;
        RECT 64.060 123.790 77.670 135.400 ;
        RECT 70.605 122.415 71.310 123.790 ;
        RECT 79.005 122.795 79.950 162.120 ;
        RECT 81.120 150.990 94.730 162.600 ;
        RECT 96.065 162.120 96.585 163.595 ;
        RECT 104.725 162.600 105.245 163.595 ;
        RECT 87.665 149.000 88.185 150.990 ;
        RECT 81.120 137.390 94.730 149.000 ;
        RECT 87.665 135.400 88.185 137.390 ;
        RECT 81.120 123.790 94.730 135.400 ;
        RECT 87.580 122.415 88.285 123.790 ;
        RECT 96.065 122.795 97.010 162.120 ;
        RECT 98.180 150.990 111.790 162.600 ;
        RECT 113.125 162.120 113.645 163.595 ;
        RECT 113.125 158.145 114.070 162.120 ;
        RECT 113.125 152.810 113.645 158.145 ;
        RECT 104.725 149.000 105.245 150.990 ;
        RECT 98.180 137.390 111.790 149.000 ;
        RECT 104.725 135.400 105.245 137.390 ;
        RECT 98.180 123.790 111.790 135.400 ;
        RECT 104.480 122.415 105.515 123.790 ;
        RECT 113.125 122.795 114.070 152.810 ;
        RECT 70.545 122.410 114.195 122.415 ;
        RECT 70.545 120.605 130.085 122.410 ;
        RECT 113.690 120.600 130.085 120.605 ;
        RECT 67.120 67.070 102.185 67.875 ;
        RECT 67.120 64.870 68.065 67.070 ;
        RECT 84.180 64.870 85.125 67.070 ;
        RECT 101.240 64.870 102.185 67.070 ;
        RECT 69.765 56.805 70.285 57.800 ;
        RECT 63.220 45.195 76.830 56.805 ;
        RECT 78.165 56.325 78.685 57.800 ;
        RECT 86.825 56.805 87.345 57.800 ;
        RECT 69.765 43.205 70.285 45.195 ;
        RECT 63.220 31.595 76.830 43.205 ;
        RECT 69.765 29.605 70.285 31.595 ;
        RECT 63.220 17.995 76.830 29.605 ;
        RECT 69.765 16.620 70.470 17.995 ;
        RECT 78.165 17.000 79.110 56.325 ;
        RECT 80.280 45.195 93.890 56.805 ;
        RECT 95.225 56.325 95.745 57.800 ;
        RECT 103.885 56.805 104.405 57.800 ;
        RECT 86.825 43.205 87.345 45.195 ;
        RECT 80.280 31.595 93.890 43.205 ;
        RECT 86.825 29.605 87.345 31.595 ;
        RECT 80.280 17.995 93.890 29.605 ;
        RECT 86.740 16.620 87.445 17.995 ;
        RECT 95.225 17.000 96.170 56.325 ;
        RECT 97.340 45.195 110.950 56.805 ;
        RECT 112.285 56.325 112.805 57.800 ;
        RECT 112.285 52.350 113.230 56.325 ;
        RECT 112.285 47.015 112.805 52.350 ;
        RECT 103.885 43.205 104.405 45.195 ;
        RECT 97.340 31.595 110.950 43.205 ;
        RECT 103.885 29.605 104.405 31.595 ;
        RECT 97.340 17.995 110.950 29.605 ;
        RECT 103.640 16.620 104.675 17.995 ;
        RECT 112.285 17.000 113.230 47.015 ;
        RECT 69.705 16.615 113.355 16.620 ;
        RECT 69.705 14.810 129.245 16.615 ;
        RECT 112.850 14.805 129.245 14.810 ;
  END
END tt_um_LDO22t4
END LIBRARY

